VERSION 5.7 ;
  NOWIREEXTENSIONATPIN ON ;
  DIVIDERCHAR "/" ;
  BUSBITCHARS "[]" ;
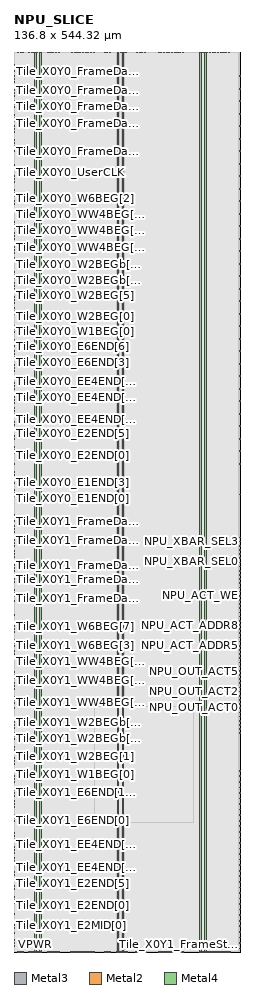
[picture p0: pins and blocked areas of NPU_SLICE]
MACRO NPU_SLICE
  CLASS BLOCK ;
  FOREIGN NPU_SLICE ;
  ORIGIN 0.000 0.000 ;
  SIZE 136.800 BY 544.320 ;
  PIN FAB_USER_CLK
    DIRECTION OUTPUT ;
    USE SIGNAL ;
    ANTENNADIFFAREA 2.724000 ;
    PORT
      LAYER Metal3 ;
        RECT 136.400 250.540 136.800 250.940 ;
    END
  END FAB_USER_CLK
  PIN NPU_ACT_ADDR0
    DIRECTION OUTPUT ;
    USE SIGNAL ;
    ANTENNADIFFAREA 2.647800 ;
    PORT
      LAYER Metal3 ;
        RECT 136.400 172.420 136.800 172.820 ;
    END
  END NPU_ACT_ADDR0
  PIN NPU_ACT_ADDR1
    DIRECTION OUTPUT ;
    USE SIGNAL ;
    ANTENNADIFFAREA 2.647800 ;
    PORT
      LAYER Metal3 ;
        RECT 136.400 174.940 136.800 175.340 ;
    END
  END NPU_ACT_ADDR1
  PIN NPU_ACT_ADDR2
    DIRECTION OUTPUT ;
    USE SIGNAL ;
    ANTENNADIFFAREA 2.647800 ;
    PORT
      LAYER Metal3 ;
        RECT 136.400 177.460 136.800 177.860 ;
    END
  END NPU_ACT_ADDR2
  PIN NPU_ACT_ADDR3
    DIRECTION OUTPUT ;
    USE SIGNAL ;
    ANTENNADIFFAREA 2.647800 ;
    PORT
      LAYER Metal3 ;
        RECT 136.400 179.980 136.800 180.380 ;
    END
  END NPU_ACT_ADDR3
  PIN NPU_ACT_ADDR4
    DIRECTION OUTPUT ;
    USE SIGNAL ;
    ANTENNADIFFAREA 2.647800 ;
    PORT
      LAYER Metal3 ;
        RECT 136.400 182.500 136.800 182.900 ;
    END
  END NPU_ACT_ADDR4
  PIN NPU_ACT_ADDR5
    DIRECTION OUTPUT ;
    USE SIGNAL ;
    ANTENNADIFFAREA 2.647800 ;
    PORT
      LAYER Metal3 ;
        RECT 136.400 185.020 136.800 185.420 ;
    END
  END NPU_ACT_ADDR5
  PIN NPU_ACT_ADDR6
    DIRECTION OUTPUT ;
    USE SIGNAL ;
    ANTENNADIFFAREA 2.647800 ;
    PORT
      LAYER Metal3 ;
        RECT 136.400 187.540 136.800 187.940 ;
    END
  END NPU_ACT_ADDR6
  PIN NPU_ACT_ADDR7
    DIRECTION OUTPUT ;
    USE SIGNAL ;
    ANTENNADIFFAREA 2.647800 ;
    PORT
      LAYER Metal3 ;
        RECT 136.400 190.060 136.800 190.460 ;
    END
  END NPU_ACT_ADDR7
  PIN NPU_ACT_ADDR8
    DIRECTION OUTPUT ;
    USE SIGNAL ;
    ANTENNADIFFAREA 2.647800 ;
    PORT
      LAYER Metal3 ;
        RECT 136.400 192.580 136.800 192.980 ;
    END
  END NPU_ACT_ADDR8
  PIN NPU_ACT_RDATA0
    DIRECTION INPUT ;
    USE SIGNAL ;
    ANTENNAGATEAREA 0.109200 ;
    PORT
      LAYER Metal3 ;
        RECT 136.400 132.100 136.800 132.500 ;
    END
  END NPU_ACT_RDATA0
  PIN NPU_ACT_RDATA1
    DIRECTION INPUT ;
    USE SIGNAL ;
    ANTENNAGATEAREA 0.109200 ;
    PORT
      LAYER Metal3 ;
        RECT 136.400 134.620 136.800 135.020 ;
    END
  END NPU_ACT_RDATA1
  PIN NPU_ACT_RDATA2
    DIRECTION INPUT ;
    USE SIGNAL ;
    ANTENNAGATEAREA 0.109200 ;
    PORT
      LAYER Metal3 ;
        RECT 136.400 137.140 136.800 137.540 ;
    END
  END NPU_ACT_RDATA2
  PIN NPU_ACT_RDATA3
    DIRECTION INPUT ;
    USE SIGNAL ;
    ANTENNAGATEAREA 0.109200 ;
    PORT
      LAYER Metal3 ;
        RECT 136.400 139.660 136.800 140.060 ;
    END
  END NPU_ACT_RDATA3
  PIN NPU_ACT_RDATA4
    DIRECTION INPUT ;
    USE SIGNAL ;
    ANTENNAGATEAREA 0.109200 ;
    PORT
      LAYER Metal3 ;
        RECT 136.400 142.180 136.800 142.580 ;
    END
  END NPU_ACT_RDATA4
  PIN NPU_ACT_RDATA5
    DIRECTION INPUT ;
    USE SIGNAL ;
    ANTENNAGATEAREA 0.109200 ;
    PORT
      LAYER Metal3 ;
        RECT 136.400 144.700 136.800 145.100 ;
    END
  END NPU_ACT_RDATA5
  PIN NPU_ACT_RDATA6
    DIRECTION INPUT ;
    USE SIGNAL ;
    ANTENNAGATEAREA 0.109200 ;
    PORT
      LAYER Metal3 ;
        RECT 136.400 147.220 136.800 147.620 ;
    END
  END NPU_ACT_RDATA6
  PIN NPU_ACT_RDATA7
    DIRECTION INPUT ;
    USE SIGNAL ;
    ANTENNAGATEAREA 0.109200 ;
    PORT
      LAYER Metal3 ;
        RECT 136.400 149.740 136.800 150.140 ;
    END
  END NPU_ACT_RDATA7
  PIN NPU_ACT_WDATA0
    DIRECTION OUTPUT ;
    USE SIGNAL ;
    ANTENNADIFFAREA 2.647800 ;
    PORT
      LAYER Metal3 ;
        RECT 136.400 195.100 136.800 195.500 ;
    END
  END NPU_ACT_WDATA0
  PIN NPU_ACT_WDATA1
    DIRECTION OUTPUT ;
    USE SIGNAL ;
    ANTENNADIFFAREA 2.647800 ;
    PORT
      LAYER Metal3 ;
        RECT 136.400 197.620 136.800 198.020 ;
    END
  END NPU_ACT_WDATA1
  PIN NPU_ACT_WDATA2
    DIRECTION OUTPUT ;
    USE SIGNAL ;
    ANTENNADIFFAREA 2.647800 ;
    PORT
      LAYER Metal3 ;
        RECT 136.400 200.140 136.800 200.540 ;
    END
  END NPU_ACT_WDATA2
  PIN NPU_ACT_WDATA3
    DIRECTION OUTPUT ;
    USE SIGNAL ;
    ANTENNADIFFAREA 2.647800 ;
    PORT
      LAYER Metal3 ;
        RECT 136.400 202.660 136.800 203.060 ;
    END
  END NPU_ACT_WDATA3
  PIN NPU_ACT_WDATA4
    DIRECTION OUTPUT ;
    USE SIGNAL ;
    ANTENNADIFFAREA 2.647800 ;
    PORT
      LAYER Metal3 ;
        RECT 136.400 205.180 136.800 205.580 ;
    END
  END NPU_ACT_WDATA4
  PIN NPU_ACT_WDATA5
    DIRECTION OUTPUT ;
    USE SIGNAL ;
    ANTENNADIFFAREA 2.647800 ;
    PORT
      LAYER Metal3 ;
        RECT 136.400 207.700 136.800 208.100 ;
    END
  END NPU_ACT_WDATA5
  PIN NPU_ACT_WDATA6
    DIRECTION OUTPUT ;
    USE SIGNAL ;
    ANTENNADIFFAREA 2.647800 ;
    PORT
      LAYER Metal3 ;
        RECT 136.400 210.220 136.800 210.620 ;
    END
  END NPU_ACT_WDATA6
  PIN NPU_ACT_WDATA7
    DIRECTION OUTPUT ;
    USE SIGNAL ;
    ANTENNADIFFAREA 2.647800 ;
    PORT
      LAYER Metal3 ;
        RECT 136.400 212.740 136.800 213.140 ;
    END
  END NPU_ACT_WDATA7
  PIN NPU_ACT_WE
    DIRECTION OUTPUT ;
    USE SIGNAL ;
    ANTENNADIFFAREA 2.647800 ;
    PORT
      LAYER Metal3 ;
        RECT 136.400 215.260 136.800 215.660 ;
    END
  END NPU_ACT_WE
  PIN NPU_OUT_ACT0
    DIRECTION INPUT ;
    USE SIGNAL ;
    ANTENNAGATEAREA 0.109200 ;
    ANTENNADIFFAREA 2.015400 ;
    PORT
      LAYER Metal3 ;
        RECT 136.400 152.260 136.800 152.660 ;
    END
  END NPU_OUT_ACT0
  PIN NPU_OUT_ACT1
    DIRECTION INPUT ;
    USE SIGNAL ;
    ANTENNAGATEAREA 0.109200 ;
    PORT
      LAYER Metal3 ;
        RECT 136.400 154.780 136.800 155.180 ;
    END
  END NPU_OUT_ACT1
  PIN NPU_OUT_ACT2
    DIRECTION INPUT ;
    USE SIGNAL ;
    ANTENNAGATEAREA 0.109200 ;
    PORT
      LAYER Metal3 ;
        RECT 136.400 157.300 136.800 157.700 ;
    END
  END NPU_OUT_ACT2
  PIN NPU_OUT_ACT3
    DIRECTION INPUT ;
    USE SIGNAL ;
    ANTENNAGATEAREA 0.109200 ;
    ANTENNADIFFAREA 2.015400 ;
    PORT
      LAYER Metal3 ;
        RECT 136.400 159.820 136.800 160.220 ;
    END
  END NPU_OUT_ACT3
  PIN NPU_OUT_ACT4
    DIRECTION INPUT ;
    USE SIGNAL ;
    ANTENNAGATEAREA 0.109200 ;
    ANTENNADIFFAREA 2.015400 ;
    PORT
      LAYER Metal3 ;
        RECT 136.400 162.340 136.800 162.740 ;
    END
  END NPU_OUT_ACT4
  PIN NPU_OUT_ACT5
    DIRECTION INPUT ;
    USE SIGNAL ;
    ANTENNAGATEAREA 0.109200 ;
    ANTENNADIFFAREA 2.015400 ;
    PORT
      LAYER Metal3 ;
        RECT 136.400 164.860 136.800 165.260 ;
    END
  END NPU_OUT_ACT5
  PIN NPU_OUT_ACT6
    DIRECTION INPUT ;
    USE SIGNAL ;
    ANTENNAGATEAREA 0.109200 ;
    ANTENNADIFFAREA 2.015400 ;
    PORT
      LAYER Metal3 ;
        RECT 136.400 167.380 136.800 167.780 ;
    END
  END NPU_OUT_ACT6
  PIN NPU_OUT_ACT7
    DIRECTION INPUT ;
    USE SIGNAL ;
    ANTENNAGATEAREA 0.109200 ;
    ANTENNADIFFAREA 2.015400 ;
    PORT
      LAYER Metal3 ;
        RECT 136.400 169.900 136.800 170.300 ;
    END
  END NPU_OUT_ACT7
  PIN NPU_WEIGHT_IN0
    DIRECTION OUTPUT ;
    USE SIGNAL ;
    ANTENNADIFFAREA 2.647800 ;
    PORT
      LAYER Metal3 ;
        RECT 136.400 217.780 136.800 218.180 ;
    END
  END NPU_WEIGHT_IN0
  PIN NPU_WEIGHT_IN1
    DIRECTION OUTPUT ;
    USE SIGNAL ;
    ANTENNADIFFAREA 2.647800 ;
    PORT
      LAYER Metal3 ;
        RECT 136.400 220.300 136.800 220.700 ;
    END
  END NPU_WEIGHT_IN1
  PIN NPU_WEIGHT_IN2
    DIRECTION OUTPUT ;
    USE SIGNAL ;
    ANTENNADIFFAREA 2.647800 ;
    PORT
      LAYER Metal3 ;
        RECT 136.400 222.820 136.800 223.220 ;
    END
  END NPU_WEIGHT_IN2
  PIN NPU_WEIGHT_IN3
    DIRECTION OUTPUT ;
    USE SIGNAL ;
    ANTENNADIFFAREA 2.647800 ;
    PORT
      LAYER Metal3 ;
        RECT 136.400 225.340 136.800 225.740 ;
    END
  END NPU_WEIGHT_IN3
  PIN NPU_WEIGHT_IN4
    DIRECTION OUTPUT ;
    USE SIGNAL ;
    ANTENNADIFFAREA 2.647800 ;
    PORT
      LAYER Metal3 ;
        RECT 136.400 227.860 136.800 228.260 ;
    END
  END NPU_WEIGHT_IN4
  PIN NPU_WEIGHT_IN5
    DIRECTION OUTPUT ;
    USE SIGNAL ;
    ANTENNADIFFAREA 2.647800 ;
    PORT
      LAYER Metal3 ;
        RECT 136.400 230.380 136.800 230.780 ;
    END
  END NPU_WEIGHT_IN5
  PIN NPU_WEIGHT_IN6
    DIRECTION OUTPUT ;
    USE SIGNAL ;
    ANTENNADIFFAREA 2.647800 ;
    PORT
      LAYER Metal3 ;
        RECT 136.400 232.900 136.800 233.300 ;
    END
  END NPU_WEIGHT_IN6
  PIN NPU_WEIGHT_IN7
    DIRECTION OUTPUT ;
    USE SIGNAL ;
    ANTENNADIFFAREA 2.647800 ;
    PORT
      LAYER Metal3 ;
        RECT 136.400 235.420 136.800 235.820 ;
    END
  END NPU_WEIGHT_IN7
  PIN NPU_WEIGHT_SHIFT_EN
    DIRECTION OUTPUT ;
    USE SIGNAL ;
    ANTENNADIFFAREA 2.647800 ;
    PORT
      LAYER Metal3 ;
        RECT 136.400 237.940 136.800 238.340 ;
    END
  END NPU_WEIGHT_SHIFT_EN
  PIN NPU_XBAR_SEL0
    DIRECTION OUTPUT ;
    USE SIGNAL ;
    ANTENNADIFFAREA 2.647800 ;
    PORT
      LAYER Metal3 ;
        RECT 136.400 240.460 136.800 240.860 ;
    END
  END NPU_XBAR_SEL0
  PIN NPU_XBAR_SEL1
    DIRECTION OUTPUT ;
    USE SIGNAL ;
    ANTENNADIFFAREA 2.647800 ;
    PORT
      LAYER Metal3 ;
        RECT 136.400 242.980 136.800 243.380 ;
    END
  END NPU_XBAR_SEL1
  PIN NPU_XBAR_SEL2
    DIRECTION OUTPUT ;
    USE SIGNAL ;
    ANTENNADIFFAREA 2.647800 ;
    PORT
      LAYER Metal3 ;
        RECT 136.400 245.500 136.800 245.900 ;
    END
  END NPU_XBAR_SEL2
  PIN NPU_XBAR_SEL3
    DIRECTION OUTPUT ;
    USE SIGNAL ;
    ANTENNADIFFAREA 2.647800 ;
    PORT
      LAYER Metal3 ;
        RECT 136.400 248.020 136.800 248.420 ;
    END
  END NPU_XBAR_SEL3
  PIN Tile_X0Y0_E1END[0]
    DIRECTION INPUT ;
    USE SIGNAL ;
    ANTENNAGATEAREA 1.279200 ;
    PORT
      LAYER Metal3 ;
        RECT 0.000 274.060 0.400 274.460 ;
    END
  END Tile_X0Y0_E1END[0]
  PIN Tile_X0Y0_E1END[1]
    DIRECTION INPUT ;
    USE SIGNAL ;
    ANTENNAGATEAREA 1.279200 ;
    PORT
      LAYER Metal3 ;
        RECT 0.000 275.740 0.400 276.140 ;
    END
  END Tile_X0Y0_E1END[1]
  PIN Tile_X0Y0_E1END[2]
    DIRECTION INPUT ;
    USE SIGNAL ;
    ANTENNAGATEAREA 1.279200 ;
    PORT
      LAYER Metal3 ;
        RECT 0.000 277.420 0.400 277.820 ;
    END
  END Tile_X0Y0_E1END[2]
  PIN Tile_X0Y0_E1END[3]
    DIRECTION INPUT ;
    USE SIGNAL ;
    ANTENNAGATEAREA 1.066000 ;
    PORT
      LAYER Metal3 ;
        RECT 0.000 279.100 0.400 279.500 ;
    END
  END Tile_X0Y0_E1END[3]
  PIN Tile_X0Y0_E2END[0]
    DIRECTION INPUT ;
    USE SIGNAL ;
    ANTENNAGATEAREA 0.639600 ;
    PORT
      LAYER Metal3 ;
        RECT 0.000 300.100 0.400 300.500 ;
    END
  END Tile_X0Y0_E2END[0]
  PIN Tile_X0Y0_E2END[1]
    DIRECTION INPUT ;
    USE SIGNAL ;
    ANTENNAGATEAREA 0.639600 ;
    PORT
      LAYER Metal3 ;
        RECT 0.000 301.780 0.400 302.180 ;
    END
  END Tile_X0Y0_E2END[1]
  PIN Tile_X0Y0_E2END[2]
    DIRECTION INPUT ;
    USE SIGNAL ;
    ANTENNAGATEAREA 0.639600 ;
    PORT
      LAYER Metal3 ;
        RECT 0.000 303.460 0.400 303.860 ;
    END
  END Tile_X0Y0_E2END[2]
  PIN Tile_X0Y0_E2END[3]
    DIRECTION INPUT ;
    USE SIGNAL ;
    ANTENNAGATEAREA 0.639600 ;
    PORT
      LAYER Metal3 ;
        RECT 0.000 305.140 0.400 305.540 ;
    END
  END Tile_X0Y0_E2END[3]
  PIN Tile_X0Y0_E2END[4]
    DIRECTION INPUT ;
    USE SIGNAL ;
    ANTENNAGATEAREA 0.639600 ;
    PORT
      LAYER Metal3 ;
        RECT 0.000 306.820 0.400 307.220 ;
    END
  END Tile_X0Y0_E2END[4]
  PIN Tile_X0Y0_E2END[5]
    DIRECTION INPUT ;
    USE SIGNAL ;
    ANTENNAGATEAREA 0.639600 ;
    PORT
      LAYER Metal3 ;
        RECT 0.000 308.500 0.400 308.900 ;
    END
  END Tile_X0Y0_E2END[5]
  PIN Tile_X0Y0_E2END[6]
    DIRECTION INPUT ;
    USE SIGNAL ;
    ANTENNAGATEAREA 0.639600 ;
    PORT
      LAYER Metal3 ;
        RECT 0.000 310.180 0.400 310.580 ;
    END
  END Tile_X0Y0_E2END[6]
  PIN Tile_X0Y0_E2END[7]
    DIRECTION INPUT ;
    USE SIGNAL ;
    ANTENNAGATEAREA 0.639600 ;
    PORT
      LAYER Metal3 ;
        RECT 0.000 311.860 0.400 312.260 ;
    END
  END Tile_X0Y0_E2END[7]
  PIN Tile_X0Y0_E2MID[0]
    DIRECTION INPUT ;
    USE SIGNAL ;
    ANTENNAGATEAREA 0.639600 ;
    PORT
      LAYER Metal3 ;
        RECT 0.000 283.300 0.400 283.700 ;
    END
  END Tile_X0Y0_E2MID[0]
  PIN Tile_X0Y0_E2MID[1]
    DIRECTION INPUT ;
    USE SIGNAL ;
    ANTENNAGATEAREA 0.639600 ;
    PORT
      LAYER Metal3 ;
        RECT 0.000 284.980 0.400 285.380 ;
    END
  END Tile_X0Y0_E2MID[1]
  PIN Tile_X0Y0_E2MID[2]
    DIRECTION INPUT ;
    USE SIGNAL ;
    ANTENNAGATEAREA 0.639600 ;
    PORT
      LAYER Metal3 ;
        RECT 0.000 286.660 0.400 287.060 ;
    END
  END Tile_X0Y0_E2MID[2]
  PIN Tile_X0Y0_E2MID[3]
    DIRECTION INPUT ;
    USE SIGNAL ;
    ANTENNAGATEAREA 0.639600 ;
    PORT
      LAYER Metal3 ;
        RECT 0.000 288.340 0.400 288.740 ;
    END
  END Tile_X0Y0_E2MID[3]
  PIN Tile_X0Y0_E2MID[4]
    DIRECTION INPUT ;
    USE SIGNAL ;
    ANTENNAGATEAREA 0.639600 ;
    PORT
      LAYER Metal3 ;
        RECT 0.000 290.020 0.400 290.420 ;
    END
  END Tile_X0Y0_E2MID[4]
  PIN Tile_X0Y0_E2MID[5]
    DIRECTION INPUT ;
    USE SIGNAL ;
    ANTENNAGATEAREA 0.639600 ;
    PORT
      LAYER Metal3 ;
        RECT 0.000 291.700 0.400 292.100 ;
    END
  END Tile_X0Y0_E2MID[5]
  PIN Tile_X0Y0_E2MID[6]
    DIRECTION INPUT ;
    USE SIGNAL ;
    ANTENNAGATEAREA 0.639600 ;
    PORT
      LAYER Metal3 ;
        RECT 0.000 293.380 0.400 293.780 ;
    END
  END Tile_X0Y0_E2MID[6]
  PIN Tile_X0Y0_E2MID[7]
    DIRECTION INPUT ;
    USE SIGNAL ;
    ANTENNAGATEAREA 0.639600 ;
    PORT
      LAYER Metal3 ;
        RECT 0.000 295.060 0.400 295.460 ;
    END
  END Tile_X0Y0_E2MID[7]
  PIN Tile_X0Y0_E6END[0]
    DIRECTION INPUT ;
    USE SIGNAL ;
    ANTENNAGATEAREA 0.852800 ;
    PORT
      LAYER Metal3 ;
        RECT 0.000 351.340 0.400 351.740 ;
    END
  END Tile_X0Y0_E6END[0]
  PIN Tile_X0Y0_E6END[10]
    DIRECTION INPUT ;
    USE SIGNAL ;
    ANTENNAGATEAREA 0.639600 ;
    PORT
      LAYER Metal3 ;
        RECT 0.000 368.140 0.400 368.540 ;
    END
  END Tile_X0Y0_E6END[10]
  PIN Tile_X0Y0_E6END[11]
    DIRECTION INPUT ;
    USE SIGNAL ;
    ANTENNAGATEAREA 0.639600 ;
    PORT
      LAYER Metal3 ;
        RECT 0.000 369.820 0.400 370.220 ;
    END
  END Tile_X0Y0_E6END[11]
  PIN Tile_X0Y0_E6END[1]
    DIRECTION INPUT ;
    USE SIGNAL ;
    ANTENNAGATEAREA 0.852800 ;
    PORT
      LAYER Metal3 ;
        RECT 0.000 353.020 0.400 353.420 ;
    END
  END Tile_X0Y0_E6END[1]
  PIN Tile_X0Y0_E6END[2]
    DIRECTION INPUT ;
    USE SIGNAL ;
    ANTENNAGATEAREA 0.852800 ;
    PORT
      LAYER Metal3 ;
        RECT 0.000 354.700 0.400 355.100 ;
    END
  END Tile_X0Y0_E6END[2]
  PIN Tile_X0Y0_E6END[3]
    DIRECTION INPUT ;
    USE SIGNAL ;
    ANTENNAGATEAREA 0.639600 ;
    PORT
      LAYER Metal3 ;
        RECT 0.000 356.380 0.400 356.780 ;
    END
  END Tile_X0Y0_E6END[3]
  PIN Tile_X0Y0_E6END[4]
    DIRECTION INPUT ;
    USE SIGNAL ;
    ANTENNAGATEAREA 0.639600 ;
    PORT
      LAYER Metal3 ;
        RECT 0.000 358.060 0.400 358.460 ;
    END
  END Tile_X0Y0_E6END[4]
  PIN Tile_X0Y0_E6END[5]
    DIRECTION INPUT ;
    USE SIGNAL ;
    ANTENNAGATEAREA 0.639600 ;
    PORT
      LAYER Metal3 ;
        RECT 0.000 359.740 0.400 360.140 ;
    END
  END Tile_X0Y0_E6END[5]
  PIN Tile_X0Y0_E6END[6]
    DIRECTION INPUT ;
    USE SIGNAL ;
    ANTENNAGATEAREA 0.639600 ;
    PORT
      LAYER Metal3 ;
        RECT 0.000 361.420 0.400 361.820 ;
    END
  END Tile_X0Y0_E6END[6]
  PIN Tile_X0Y0_E6END[7]
    DIRECTION INPUT ;
    USE SIGNAL ;
    ANTENNAGATEAREA 0.639600 ;
    PORT
      LAYER Metal3 ;
        RECT 0.000 363.100 0.400 363.500 ;
    END
  END Tile_X0Y0_E6END[7]
  PIN Tile_X0Y0_E6END[8]
    DIRECTION INPUT ;
    USE SIGNAL ;
    ANTENNAGATEAREA 0.639600 ;
    PORT
      LAYER Metal3 ;
        RECT 0.000 364.780 0.400 365.180 ;
    END
  END Tile_X0Y0_E6END[8]
  PIN Tile_X0Y0_E6END[9]
    DIRECTION INPUT ;
    USE SIGNAL ;
    ANTENNAGATEAREA 0.639600 ;
    PORT
      LAYER Metal3 ;
        RECT 0.000 366.460 0.400 366.860 ;
    END
  END Tile_X0Y0_E6END[9]
  PIN Tile_X0Y0_EE4END[0]
    DIRECTION INPUT ;
    USE SIGNAL ;
    ANTENNAGATEAREA 0.426400 ;
    PORT
      LAYER Metal3 ;
        RECT 0.000 318.580 0.400 318.980 ;
    END
  END Tile_X0Y0_EE4END[0]
  PIN Tile_X0Y0_EE4END[10]
    DIRECTION INPUT ;
    USE SIGNAL ;
    ANTENNAGATEAREA 0.426400 ;
    PORT
      LAYER Metal3 ;
        RECT 0.000 335.380 0.400 335.780 ;
    END
  END Tile_X0Y0_EE4END[10]
  PIN Tile_X0Y0_EE4END[11]
    DIRECTION INPUT ;
    USE SIGNAL ;
    ANTENNAGATEAREA 0.426400 ;
    PORT
      LAYER Metal3 ;
        RECT 0.000 337.060 0.400 337.460 ;
    END
  END Tile_X0Y0_EE4END[11]
  PIN Tile_X0Y0_EE4END[12]
    DIRECTION INPUT ;
    USE SIGNAL ;
    ANTENNAGATEAREA 0.426400 ;
    PORT
      LAYER Metal3 ;
        RECT 0.000 338.740 0.400 339.140 ;
    END
  END Tile_X0Y0_EE4END[12]
  PIN Tile_X0Y0_EE4END[13]
    DIRECTION INPUT ;
    USE SIGNAL ;
    ANTENNAGATEAREA 0.426400 ;
    PORT
      LAYER Metal3 ;
        RECT 0.000 340.420 0.400 340.820 ;
    END
  END Tile_X0Y0_EE4END[13]
  PIN Tile_X0Y0_EE4END[14]
    DIRECTION INPUT ;
    USE SIGNAL ;
    ANTENNAGATEAREA 0.426400 ;
    PORT
      LAYER Metal3 ;
        RECT 0.000 342.100 0.400 342.500 ;
    END
  END Tile_X0Y0_EE4END[14]
  PIN Tile_X0Y0_EE4END[15]
    DIRECTION INPUT ;
    USE SIGNAL ;
    ANTENNAGATEAREA 0.426400 ;
    PORT
      LAYER Metal3 ;
        RECT 0.000 343.780 0.400 344.180 ;
    END
  END Tile_X0Y0_EE4END[15]
  PIN Tile_X0Y0_EE4END[1]
    DIRECTION INPUT ;
    USE SIGNAL ;
    ANTENNAGATEAREA 0.426400 ;
    PORT
      LAYER Metal3 ;
        RECT 0.000 320.260 0.400 320.660 ;
    END
  END Tile_X0Y0_EE4END[1]
  PIN Tile_X0Y0_EE4END[2]
    DIRECTION INPUT ;
    USE SIGNAL ;
    ANTENNAGATEAREA 0.426400 ;
    PORT
      LAYER Metal3 ;
        RECT 0.000 321.940 0.400 322.340 ;
    END
  END Tile_X0Y0_EE4END[2]
  PIN Tile_X0Y0_EE4END[3]
    DIRECTION INPUT ;
    USE SIGNAL ;
    ANTENNAGATEAREA 0.426400 ;
    PORT
      LAYER Metal3 ;
        RECT 0.000 323.620 0.400 324.020 ;
    END
  END Tile_X0Y0_EE4END[3]
  PIN Tile_X0Y0_EE4END[4]
    DIRECTION INPUT ;
    USE SIGNAL ;
    ANTENNAGATEAREA 0.426400 ;
    PORT
      LAYER Metal3 ;
        RECT 0.000 325.300 0.400 325.700 ;
    END
  END Tile_X0Y0_EE4END[4]
  PIN Tile_X0Y0_EE4END[5]
    DIRECTION INPUT ;
    USE SIGNAL ;
    ANTENNAGATEAREA 0.426400 ;
    PORT
      LAYER Metal3 ;
        RECT 0.000 326.980 0.400 327.380 ;
    END
  END Tile_X0Y0_EE4END[5]
  PIN Tile_X0Y0_EE4END[6]
    DIRECTION INPUT ;
    USE SIGNAL ;
    ANTENNAGATEAREA 0.426400 ;
    PORT
      LAYER Metal3 ;
        RECT 0.000 328.660 0.400 329.060 ;
    END
  END Tile_X0Y0_EE4END[6]
  PIN Tile_X0Y0_EE4END[7]
    DIRECTION INPUT ;
    USE SIGNAL ;
    ANTENNAGATEAREA 0.426400 ;
    PORT
      LAYER Metal3 ;
        RECT 0.000 330.340 0.400 330.740 ;
    END
  END Tile_X0Y0_EE4END[7]
  PIN Tile_X0Y0_EE4END[8]
    DIRECTION INPUT ;
    USE SIGNAL ;
    ANTENNAGATEAREA 0.426400 ;
    PORT
      LAYER Metal3 ;
        RECT 0.000 332.020 0.400 332.420 ;
    END
  END Tile_X0Y0_EE4END[8]
  PIN Tile_X0Y0_EE4END[9]
    DIRECTION INPUT ;
    USE SIGNAL ;
    ANTENNAGATEAREA 0.426400 ;
    PORT
      LAYER Metal3 ;
        RECT 0.000 333.700 0.400 334.100 ;
    END
  END Tile_X0Y0_EE4END[9]
  PIN Tile_X0Y0_FrameData[0]
    DIRECTION INPUT ;
    USE SIGNAL ;
    ANTENNAGATEAREA 1.445600 ;
    PORT
      LAYER Metal3 ;
        RECT 0.000 484.060 0.400 484.460 ;
    END
  END Tile_X0Y0_FrameData[0]
  PIN Tile_X0Y0_FrameData[10]
    DIRECTION INPUT ;
    USE SIGNAL ;
    ANTENNAGATEAREA 1.626300 ;
    PORT
      LAYER Metal3 ;
        RECT 0.000 500.860 0.400 501.260 ;
    END
  END Tile_X0Y0_FrameData[10]
  PIN Tile_X0Y0_FrameData[11]
    DIRECTION INPUT ;
    USE SIGNAL ;
    ANTENNAGATEAREA 1.626300 ;
    PORT
      LAYER Metal3 ;
        RECT 0.000 502.540 0.400 502.940 ;
    END
  END Tile_X0Y0_FrameData[11]
  PIN Tile_X0Y0_FrameData[12]
    DIRECTION INPUT ;
    USE SIGNAL ;
    ANTENNAGATEAREA 1.626300 ;
    PORT
      LAYER Metal3 ;
        RECT 0.000 504.220 0.400 504.620 ;
    END
  END Tile_X0Y0_FrameData[12]
  PIN Tile_X0Y0_FrameData[13]
    DIRECTION INPUT ;
    USE SIGNAL ;
    ANTENNAGATEAREA 1.626300 ;
    PORT
      LAYER Metal3 ;
        RECT 0.000 505.900 0.400 506.300 ;
    END
  END Tile_X0Y0_FrameData[13]
  PIN Tile_X0Y0_FrameData[14]
    DIRECTION INPUT ;
    USE SIGNAL ;
    ANTENNAGATEAREA 1.626300 ;
    PORT
      LAYER Metal3 ;
        RECT 0.000 507.580 0.400 507.980 ;
    END
  END Tile_X0Y0_FrameData[14]
  PIN Tile_X0Y0_FrameData[15]
    DIRECTION INPUT ;
    USE SIGNAL ;
    ANTENNAGATEAREA 1.626300 ;
    PORT
      LAYER Metal3 ;
        RECT 0.000 509.260 0.400 509.660 ;
    END
  END Tile_X0Y0_FrameData[15]
  PIN Tile_X0Y0_FrameData[16]
    DIRECTION INPUT ;
    USE SIGNAL ;
    ANTENNAGATEAREA 1.626300 ;
    PORT
      LAYER Metal3 ;
        RECT 0.000 510.940 0.400 511.340 ;
    END
  END Tile_X0Y0_FrameData[16]
  PIN Tile_X0Y0_FrameData[17]
    DIRECTION INPUT ;
    USE SIGNAL ;
    ANTENNAGATEAREA 1.626300 ;
    PORT
      LAYER Metal3 ;
        RECT 0.000 512.620 0.400 513.020 ;
    END
  END Tile_X0Y0_FrameData[17]
  PIN Tile_X0Y0_FrameData[18]
    DIRECTION INPUT ;
    USE SIGNAL ;
    ANTENNAGATEAREA 1.626300 ;
    PORT
      LAYER Metal3 ;
        RECT 0.000 514.300 0.400 514.700 ;
    END
  END Tile_X0Y0_FrameData[18]
  PIN Tile_X0Y0_FrameData[19]
    DIRECTION INPUT ;
    USE SIGNAL ;
    ANTENNAGATEAREA 1.626300 ;
    PORT
      LAYER Metal3 ;
        RECT 0.000 515.980 0.400 516.380 ;
    END
  END Tile_X0Y0_FrameData[19]
  PIN Tile_X0Y0_FrameData[1]
    DIRECTION INPUT ;
    USE SIGNAL ;
    ANTENNAGATEAREA 1.445600 ;
    PORT
      LAYER Metal3 ;
        RECT 0.000 485.740 0.400 486.140 ;
    END
  END Tile_X0Y0_FrameData[1]
  PIN Tile_X0Y0_FrameData[20]
    DIRECTION INPUT ;
    USE SIGNAL ;
    ANTENNAGATEAREA 1.626300 ;
    PORT
      LAYER Metal3 ;
        RECT 0.000 517.660 0.400 518.060 ;
    END
  END Tile_X0Y0_FrameData[20]
  PIN Tile_X0Y0_FrameData[21]
    DIRECTION INPUT ;
    USE SIGNAL ;
    ANTENNAGATEAREA 1.626300 ;
    PORT
      LAYER Metal3 ;
        RECT 0.000 519.340 0.400 519.740 ;
    END
  END Tile_X0Y0_FrameData[21]
  PIN Tile_X0Y0_FrameData[22]
    DIRECTION INPUT ;
    USE SIGNAL ;
    ANTENNAGATEAREA 1.626300 ;
    PORT
      LAYER Metal3 ;
        RECT 0.000 521.020 0.400 521.420 ;
    END
  END Tile_X0Y0_FrameData[22]
  PIN Tile_X0Y0_FrameData[23]
    DIRECTION INPUT ;
    USE SIGNAL ;
    ANTENNAGATEAREA 1.626300 ;
    PORT
      LAYER Metal3 ;
        RECT 0.000 522.700 0.400 523.100 ;
    END
  END Tile_X0Y0_FrameData[23]
  PIN Tile_X0Y0_FrameData[24]
    DIRECTION INPUT ;
    USE SIGNAL ;
    ANTENNAGATEAREA 1.626300 ;
    PORT
      LAYER Metal3 ;
        RECT 0.000 524.380 0.400 524.780 ;
    END
  END Tile_X0Y0_FrameData[24]
  PIN Tile_X0Y0_FrameData[25]
    DIRECTION INPUT ;
    USE SIGNAL ;
    ANTENNAGATEAREA 1.626300 ;
    PORT
      LAYER Metal3 ;
        RECT 0.000 526.060 0.400 526.460 ;
    END
  END Tile_X0Y0_FrameData[25]
  PIN Tile_X0Y0_FrameData[26]
    DIRECTION INPUT ;
    USE SIGNAL ;
    ANTENNAGATEAREA 1.626300 ;
    PORT
      LAYER Metal3 ;
        RECT 0.000 527.740 0.400 528.140 ;
    END
  END Tile_X0Y0_FrameData[26]
  PIN Tile_X0Y0_FrameData[27]
    DIRECTION INPUT ;
    USE SIGNAL ;
    ANTENNAGATEAREA 1.626300 ;
    PORT
      LAYER Metal3 ;
        RECT 0.000 529.420 0.400 529.820 ;
    END
  END Tile_X0Y0_FrameData[27]
  PIN Tile_X0Y0_FrameData[28]
    DIRECTION INPUT ;
    USE SIGNAL ;
    ANTENNAGATEAREA 1.626300 ;
    PORT
      LAYER Metal3 ;
        RECT 0.000 531.100 0.400 531.500 ;
    END
  END Tile_X0Y0_FrameData[28]
  PIN Tile_X0Y0_FrameData[29]
    DIRECTION INPUT ;
    USE SIGNAL ;
    ANTENNAGATEAREA 1.626300 ;
    PORT
      LAYER Metal3 ;
        RECT 0.000 532.780 0.400 533.180 ;
    END
  END Tile_X0Y0_FrameData[29]
  PIN Tile_X0Y0_FrameData[2]
    DIRECTION INPUT ;
    USE SIGNAL ;
    ANTENNAGATEAREA 1.626300 ;
    PORT
      LAYER Metal3 ;
        RECT 0.000 487.420 0.400 487.820 ;
    END
  END Tile_X0Y0_FrameData[2]
  PIN Tile_X0Y0_FrameData[30]
    DIRECTION INPUT ;
    USE SIGNAL ;
    ANTENNAGATEAREA 1.626300 ;
    PORT
      LAYER Metal3 ;
        RECT 0.000 534.460 0.400 534.860 ;
    END
  END Tile_X0Y0_FrameData[30]
  PIN Tile_X0Y0_FrameData[31]
    DIRECTION INPUT ;
    USE SIGNAL ;
    ANTENNAGATEAREA 1.626300 ;
    PORT
      LAYER Metal3 ;
        RECT 0.000 536.140 0.400 536.540 ;
    END
  END Tile_X0Y0_FrameData[31]
  PIN Tile_X0Y0_FrameData[3]
    DIRECTION INPUT ;
    USE SIGNAL ;
    ANTENNAGATEAREA 1.626300 ;
    PORT
      LAYER Metal3 ;
        RECT 0.000 489.100 0.400 489.500 ;
    END
  END Tile_X0Y0_FrameData[3]
  PIN Tile_X0Y0_FrameData[4]
    DIRECTION INPUT ;
    USE SIGNAL ;
    ANTENNAGATEAREA 1.626300 ;
    PORT
      LAYER Metal3 ;
        RECT 0.000 490.780 0.400 491.180 ;
    END
  END Tile_X0Y0_FrameData[4]
  PIN Tile_X0Y0_FrameData[5]
    DIRECTION INPUT ;
    USE SIGNAL ;
    ANTENNAGATEAREA 1.626300 ;
    PORT
      LAYER Metal3 ;
        RECT 0.000 492.460 0.400 492.860 ;
    END
  END Tile_X0Y0_FrameData[5]
  PIN Tile_X0Y0_FrameData[6]
    DIRECTION INPUT ;
    USE SIGNAL ;
    ANTENNAGATEAREA 1.626300 ;
    PORT
      LAYER Metal3 ;
        RECT 0.000 494.140 0.400 494.540 ;
    END
  END Tile_X0Y0_FrameData[6]
  PIN Tile_X0Y0_FrameData[7]
    DIRECTION INPUT ;
    USE SIGNAL ;
    ANTENNAGATEAREA 1.626300 ;
    PORT
      LAYER Metal3 ;
        RECT 0.000 495.820 0.400 496.220 ;
    END
  END Tile_X0Y0_FrameData[7]
  PIN Tile_X0Y0_FrameData[8]
    DIRECTION INPUT ;
    USE SIGNAL ;
    ANTENNAGATEAREA 1.626300 ;
    PORT
      LAYER Metal3 ;
        RECT 0.000 497.500 0.400 497.900 ;
    END
  END Tile_X0Y0_FrameData[8]
  PIN Tile_X0Y0_FrameData[9]
    DIRECTION INPUT ;
    USE SIGNAL ;
    ANTENNAGATEAREA 1.626300 ;
    PORT
      LAYER Metal3 ;
        RECT 0.000 499.180 0.400 499.580 ;
    END
  END Tile_X0Y0_FrameData[9]
  PIN Tile_X0Y0_FrameData_O[0]
    DIRECTION OUTPUT ;
    USE SIGNAL ;
    ANTENNADIFFAREA 2.724000 ;
    PORT
      LAYER Metal3 ;
        RECT 136.400 295.060 136.800 295.460 ;
    END
  END Tile_X0Y0_FrameData_O[0]
  PIN Tile_X0Y0_FrameData_O[10]
    DIRECTION OUTPUT ;
    USE SIGNAL ;
    ANTENNADIFFAREA 2.724000 ;
    PORT
      LAYER Metal3 ;
        RECT 136.400 370.660 136.800 371.060 ;
    END
  END Tile_X0Y0_FrameData_O[10]
  PIN Tile_X0Y0_FrameData_O[11]
    DIRECTION OUTPUT ;
    USE SIGNAL ;
    ANTENNADIFFAREA 2.724000 ;
    PORT
      LAYER Metal3 ;
        RECT 136.400 378.220 136.800 378.620 ;
    END
  END Tile_X0Y0_FrameData_O[11]
  PIN Tile_X0Y0_FrameData_O[12]
    DIRECTION OUTPUT ;
    USE SIGNAL ;
    ANTENNADIFFAREA 2.724000 ;
    PORT
      LAYER Metal3 ;
        RECT 136.400 385.780 136.800 386.180 ;
    END
  END Tile_X0Y0_FrameData_O[12]
  PIN Tile_X0Y0_FrameData_O[13]
    DIRECTION OUTPUT ;
    USE SIGNAL ;
    ANTENNADIFFAREA 2.724000 ;
    PORT
      LAYER Metal3 ;
        RECT 136.400 393.340 136.800 393.740 ;
    END
  END Tile_X0Y0_FrameData_O[13]
  PIN Tile_X0Y0_FrameData_O[14]
    DIRECTION OUTPUT ;
    USE SIGNAL ;
    ANTENNADIFFAREA 2.724000 ;
    PORT
      LAYER Metal3 ;
        RECT 136.400 400.900 136.800 401.300 ;
    END
  END Tile_X0Y0_FrameData_O[14]
  PIN Tile_X0Y0_FrameData_O[15]
    DIRECTION OUTPUT ;
    USE SIGNAL ;
    ANTENNADIFFAREA 2.724000 ;
    PORT
      LAYER Metal3 ;
        RECT 136.400 408.460 136.800 408.860 ;
    END
  END Tile_X0Y0_FrameData_O[15]
  PIN Tile_X0Y0_FrameData_O[16]
    DIRECTION OUTPUT ;
    USE SIGNAL ;
    ANTENNADIFFAREA 2.724000 ;
    PORT
      LAYER Metal3 ;
        RECT 136.400 416.020 136.800 416.420 ;
    END
  END Tile_X0Y0_FrameData_O[16]
  PIN Tile_X0Y0_FrameData_O[17]
    DIRECTION OUTPUT ;
    USE SIGNAL ;
    ANTENNADIFFAREA 2.724000 ;
    PORT
      LAYER Metal3 ;
        RECT 136.400 423.580 136.800 423.980 ;
    END
  END Tile_X0Y0_FrameData_O[17]
  PIN Tile_X0Y0_FrameData_O[18]
    DIRECTION OUTPUT ;
    USE SIGNAL ;
    ANTENNADIFFAREA 2.724000 ;
    PORT
      LAYER Metal3 ;
        RECT 136.400 431.140 136.800 431.540 ;
    END
  END Tile_X0Y0_FrameData_O[18]
  PIN Tile_X0Y0_FrameData_O[19]
    DIRECTION OUTPUT ;
    USE SIGNAL ;
    ANTENNADIFFAREA 2.724000 ;
    PORT
      LAYER Metal3 ;
        RECT 136.400 438.700 136.800 439.100 ;
    END
  END Tile_X0Y0_FrameData_O[19]
  PIN Tile_X0Y0_FrameData_O[1]
    DIRECTION OUTPUT ;
    USE SIGNAL ;
    ANTENNADIFFAREA 2.724000 ;
    PORT
      LAYER Metal3 ;
        RECT 136.400 302.620 136.800 303.020 ;
    END
  END Tile_X0Y0_FrameData_O[1]
  PIN Tile_X0Y0_FrameData_O[20]
    DIRECTION OUTPUT ;
    USE SIGNAL ;
    ANTENNADIFFAREA 2.724000 ;
    PORT
      LAYER Metal3 ;
        RECT 136.400 446.260 136.800 446.660 ;
    END
  END Tile_X0Y0_FrameData_O[20]
  PIN Tile_X0Y0_FrameData_O[21]
    DIRECTION OUTPUT ;
    USE SIGNAL ;
    ANTENNADIFFAREA 2.724000 ;
    PORT
      LAYER Metal3 ;
        RECT 136.400 453.820 136.800 454.220 ;
    END
  END Tile_X0Y0_FrameData_O[21]
  PIN Tile_X0Y0_FrameData_O[22]
    DIRECTION OUTPUT ;
    USE SIGNAL ;
    ANTENNADIFFAREA 2.724000 ;
    PORT
      LAYER Metal3 ;
        RECT 136.400 461.380 136.800 461.780 ;
    END
  END Tile_X0Y0_FrameData_O[22]
  PIN Tile_X0Y0_FrameData_O[23]
    DIRECTION OUTPUT ;
    USE SIGNAL ;
    ANTENNADIFFAREA 2.724000 ;
    PORT
      LAYER Metal3 ;
        RECT 136.400 468.940 136.800 469.340 ;
    END
  END Tile_X0Y0_FrameData_O[23]
  PIN Tile_X0Y0_FrameData_O[24]
    DIRECTION OUTPUT ;
    USE SIGNAL ;
    ANTENNADIFFAREA 2.724000 ;
    PORT
      LAYER Metal3 ;
        RECT 136.400 476.500 136.800 476.900 ;
    END
  END Tile_X0Y0_FrameData_O[24]
  PIN Tile_X0Y0_FrameData_O[25]
    DIRECTION OUTPUT ;
    USE SIGNAL ;
    ANTENNADIFFAREA 2.724000 ;
    PORT
      LAYER Metal3 ;
        RECT 136.400 484.060 136.800 484.460 ;
    END
  END Tile_X0Y0_FrameData_O[25]
  PIN Tile_X0Y0_FrameData_O[26]
    DIRECTION OUTPUT ;
    USE SIGNAL ;
    ANTENNADIFFAREA 2.724000 ;
    PORT
      LAYER Metal3 ;
        RECT 136.400 491.620 136.800 492.020 ;
    END
  END Tile_X0Y0_FrameData_O[26]
  PIN Tile_X0Y0_FrameData_O[27]
    DIRECTION OUTPUT ;
    USE SIGNAL ;
    ANTENNADIFFAREA 2.724000 ;
    PORT
      LAYER Metal3 ;
        RECT 136.400 499.180 136.800 499.580 ;
    END
  END Tile_X0Y0_FrameData_O[27]
  PIN Tile_X0Y0_FrameData_O[28]
    DIRECTION OUTPUT ;
    USE SIGNAL ;
    ANTENNADIFFAREA 2.724000 ;
    PORT
      LAYER Metal3 ;
        RECT 136.400 506.740 136.800 507.140 ;
    END
  END Tile_X0Y0_FrameData_O[28]
  PIN Tile_X0Y0_FrameData_O[29]
    DIRECTION OUTPUT ;
    USE SIGNAL ;
    ANTENNADIFFAREA 2.724000 ;
    PORT
      LAYER Metal3 ;
        RECT 136.400 514.300 136.800 514.700 ;
    END
  END Tile_X0Y0_FrameData_O[29]
  PIN Tile_X0Y0_FrameData_O[2]
    DIRECTION OUTPUT ;
    USE SIGNAL ;
    ANTENNADIFFAREA 2.724000 ;
    PORT
      LAYER Metal3 ;
        RECT 136.400 310.180 136.800 310.580 ;
    END
  END Tile_X0Y0_FrameData_O[2]
  PIN Tile_X0Y0_FrameData_O[30]
    DIRECTION OUTPUT ;
    USE SIGNAL ;
    ANTENNADIFFAREA 2.724000 ;
    PORT
      LAYER Metal3 ;
        RECT 136.400 521.860 136.800 522.260 ;
    END
  END Tile_X0Y0_FrameData_O[30]
  PIN Tile_X0Y0_FrameData_O[31]
    DIRECTION OUTPUT ;
    USE SIGNAL ;
    ANTENNADIFFAREA 2.724000 ;
    PORT
      LAYER Metal3 ;
        RECT 136.400 529.420 136.800 529.820 ;
    END
  END Tile_X0Y0_FrameData_O[31]
  PIN Tile_X0Y0_FrameData_O[3]
    DIRECTION OUTPUT ;
    USE SIGNAL ;
    ANTENNADIFFAREA 2.724000 ;
    PORT
      LAYER Metal3 ;
        RECT 136.400 317.740 136.800 318.140 ;
    END
  END Tile_X0Y0_FrameData_O[3]
  PIN Tile_X0Y0_FrameData_O[4]
    DIRECTION OUTPUT ;
    USE SIGNAL ;
    ANTENNADIFFAREA 2.724000 ;
    PORT
      LAYER Metal3 ;
        RECT 136.400 325.300 136.800 325.700 ;
    END
  END Tile_X0Y0_FrameData_O[4]
  PIN Tile_X0Y0_FrameData_O[5]
    DIRECTION OUTPUT ;
    USE SIGNAL ;
    ANTENNADIFFAREA 2.724000 ;
    PORT
      LAYER Metal3 ;
        RECT 136.400 332.860 136.800 333.260 ;
    END
  END Tile_X0Y0_FrameData_O[5]
  PIN Tile_X0Y0_FrameData_O[6]
    DIRECTION OUTPUT ;
    USE SIGNAL ;
    ANTENNADIFFAREA 2.724000 ;
    PORT
      LAYER Metal3 ;
        RECT 136.400 340.420 136.800 340.820 ;
    END
  END Tile_X0Y0_FrameData_O[6]
  PIN Tile_X0Y0_FrameData_O[7]
    DIRECTION OUTPUT ;
    USE SIGNAL ;
    ANTENNADIFFAREA 2.724000 ;
    PORT
      LAYER Metal3 ;
        RECT 136.400 347.980 136.800 348.380 ;
    END
  END Tile_X0Y0_FrameData_O[7]
  PIN Tile_X0Y0_FrameData_O[8]
    DIRECTION OUTPUT ;
    USE SIGNAL ;
    ANTENNADIFFAREA 2.724000 ;
    PORT
      LAYER Metal3 ;
        RECT 136.400 355.540 136.800 355.940 ;
    END
  END Tile_X0Y0_FrameData_O[8]
  PIN Tile_X0Y0_FrameData_O[9]
    DIRECTION OUTPUT ;
    USE SIGNAL ;
    ANTENNADIFFAREA 2.724000 ;
    PORT
      LAYER Metal3 ;
        RECT 136.400 363.100 136.800 363.500 ;
    END
  END Tile_X0Y0_FrameData_O[9]
  PIN Tile_X0Y0_FrameStrobe_O[0]
    DIRECTION OUTPUT ;
    USE SIGNAL ;
    ANTENNADIFFAREA 2.724000 ;
    PORT
      LAYER Metal2 ;
        RECT 112.600 543.920 113.000 544.320 ;
    END
  END Tile_X0Y0_FrameStrobe_O[0]
  PIN Tile_X0Y0_FrameStrobe_O[10]
    DIRECTION OUTPUT ;
    USE SIGNAL ;
    ANTENNADIFFAREA 2.724000 ;
    PORT
      LAYER Metal2 ;
        RECT 122.200 543.920 122.600 544.320 ;
    END
  END Tile_X0Y0_FrameStrobe_O[10]
  PIN Tile_X0Y0_FrameStrobe_O[11]
    DIRECTION OUTPUT ;
    USE SIGNAL ;
    ANTENNADIFFAREA 2.724000 ;
    PORT
      LAYER Metal2 ;
        RECT 123.160 543.920 123.560 544.320 ;
    END
  END Tile_X0Y0_FrameStrobe_O[11]
  PIN Tile_X0Y0_FrameStrobe_O[12]
    DIRECTION OUTPUT ;
    USE SIGNAL ;
    ANTENNADIFFAREA 2.724000 ;
    PORT
      LAYER Metal2 ;
        RECT 124.120 543.920 124.520 544.320 ;
    END
  END Tile_X0Y0_FrameStrobe_O[12]
  PIN Tile_X0Y0_FrameStrobe_O[13]
    DIRECTION OUTPUT ;
    USE SIGNAL ;
    ANTENNADIFFAREA 2.724000 ;
    PORT
      LAYER Metal2 ;
        RECT 125.080 543.920 125.480 544.320 ;
    END
  END Tile_X0Y0_FrameStrobe_O[13]
  PIN Tile_X0Y0_FrameStrobe_O[14]
    DIRECTION OUTPUT ;
    USE SIGNAL ;
    ANTENNADIFFAREA 2.724000 ;
    PORT
      LAYER Metal2 ;
        RECT 126.040 543.920 126.440 544.320 ;
    END
  END Tile_X0Y0_FrameStrobe_O[14]
  PIN Tile_X0Y0_FrameStrobe_O[15]
    DIRECTION OUTPUT ;
    USE SIGNAL ;
    ANTENNADIFFAREA 2.724000 ;
    PORT
      LAYER Metal2 ;
        RECT 127.000 543.920 127.400 544.320 ;
    END
  END Tile_X0Y0_FrameStrobe_O[15]
  PIN Tile_X0Y0_FrameStrobe_O[16]
    DIRECTION OUTPUT ;
    USE SIGNAL ;
    ANTENNADIFFAREA 2.724000 ;
    PORT
      LAYER Metal2 ;
        RECT 127.960 543.920 128.360 544.320 ;
    END
  END Tile_X0Y0_FrameStrobe_O[16]
  PIN Tile_X0Y0_FrameStrobe_O[17]
    DIRECTION OUTPUT ;
    USE SIGNAL ;
    ANTENNADIFFAREA 2.724000 ;
    PORT
      LAYER Metal2 ;
        RECT 128.920 543.920 129.320 544.320 ;
    END
  END Tile_X0Y0_FrameStrobe_O[17]
  PIN Tile_X0Y0_FrameStrobe_O[18]
    DIRECTION OUTPUT ;
    USE SIGNAL ;
    ANTENNADIFFAREA 2.724000 ;
    PORT
      LAYER Metal2 ;
        RECT 129.880 543.920 130.280 544.320 ;
    END
  END Tile_X0Y0_FrameStrobe_O[18]
  PIN Tile_X0Y0_FrameStrobe_O[19]
    DIRECTION OUTPUT ;
    USE SIGNAL ;
    ANTENNADIFFAREA 2.724000 ;
    PORT
      LAYER Metal2 ;
        RECT 130.840 543.920 131.240 544.320 ;
    END
  END Tile_X0Y0_FrameStrobe_O[19]
  PIN Tile_X0Y0_FrameStrobe_O[1]
    DIRECTION OUTPUT ;
    USE SIGNAL ;
    ANTENNADIFFAREA 2.724000 ;
    PORT
      LAYER Metal2 ;
        RECT 113.560 543.920 113.960 544.320 ;
    END
  END Tile_X0Y0_FrameStrobe_O[1]
  PIN Tile_X0Y0_FrameStrobe_O[2]
    DIRECTION OUTPUT ;
    USE SIGNAL ;
    ANTENNADIFFAREA 2.724000 ;
    PORT
      LAYER Metal2 ;
        RECT 114.520 543.920 114.920 544.320 ;
    END
  END Tile_X0Y0_FrameStrobe_O[2]
  PIN Tile_X0Y0_FrameStrobe_O[3]
    DIRECTION OUTPUT ;
    USE SIGNAL ;
    ANTENNADIFFAREA 2.724000 ;
    PORT
      LAYER Metal2 ;
        RECT 115.480 543.920 115.880 544.320 ;
    END
  END Tile_X0Y0_FrameStrobe_O[3]
  PIN Tile_X0Y0_FrameStrobe_O[4]
    DIRECTION OUTPUT ;
    USE SIGNAL ;
    ANTENNADIFFAREA 2.724000 ;
    PORT
      LAYER Metal2 ;
        RECT 116.440 543.920 116.840 544.320 ;
    END
  END Tile_X0Y0_FrameStrobe_O[4]
  PIN Tile_X0Y0_FrameStrobe_O[5]
    DIRECTION OUTPUT ;
    USE SIGNAL ;
    ANTENNADIFFAREA 2.724000 ;
    PORT
      LAYER Metal2 ;
        RECT 117.400 543.920 117.800 544.320 ;
    END
  END Tile_X0Y0_FrameStrobe_O[5]
  PIN Tile_X0Y0_FrameStrobe_O[6]
    DIRECTION OUTPUT ;
    USE SIGNAL ;
    ANTENNADIFFAREA 2.724000 ;
    PORT
      LAYER Metal2 ;
        RECT 118.360 543.920 118.760 544.320 ;
    END
  END Tile_X0Y0_FrameStrobe_O[6]
  PIN Tile_X0Y0_FrameStrobe_O[7]
    DIRECTION OUTPUT ;
    USE SIGNAL ;
    ANTENNADIFFAREA 2.724000 ;
    PORT
      LAYER Metal2 ;
        RECT 119.320 543.920 119.720 544.320 ;
    END
  END Tile_X0Y0_FrameStrobe_O[7]
  PIN Tile_X0Y0_FrameStrobe_O[8]
    DIRECTION OUTPUT ;
    USE SIGNAL ;
    ANTENNADIFFAREA 2.724000 ;
    PORT
      LAYER Metal2 ;
        RECT 120.280 543.920 120.680 544.320 ;
    END
  END Tile_X0Y0_FrameStrobe_O[8]
  PIN Tile_X0Y0_FrameStrobe_O[9]
    DIRECTION OUTPUT ;
    USE SIGNAL ;
    ANTENNADIFFAREA 2.724000 ;
    PORT
      LAYER Metal2 ;
        RECT 121.240 543.920 121.640 544.320 ;
    END
  END Tile_X0Y0_FrameStrobe_O[9]
  PIN Tile_X0Y0_N1BEG[0]
    DIRECTION OUTPUT ;
    USE SIGNAL ;
    ANTENNADIFFAREA 2.724000 ;
    PORT
      LAYER Metal2 ;
        RECT 2.200 543.920 2.600 544.320 ;
    END
  END Tile_X0Y0_N1BEG[0]
  PIN Tile_X0Y0_N1BEG[1]
    DIRECTION OUTPUT ;
    USE SIGNAL ;
    ANTENNADIFFAREA 2.724000 ;
    PORT
      LAYER Metal2 ;
        RECT 3.160 543.920 3.560 544.320 ;
    END
  END Tile_X0Y0_N1BEG[1]
  PIN Tile_X0Y0_N1BEG[2]
    DIRECTION OUTPUT ;
    USE SIGNAL ;
    ANTENNADIFFAREA 2.724000 ;
    PORT
      LAYER Metal2 ;
        RECT 4.120 543.920 4.520 544.320 ;
    END
  END Tile_X0Y0_N1BEG[2]
  PIN Tile_X0Y0_N1BEG[3]
    DIRECTION OUTPUT ;
    USE SIGNAL ;
    ANTENNADIFFAREA 2.724000 ;
    PORT
      LAYER Metal2 ;
        RECT 5.080 543.920 5.480 544.320 ;
    END
  END Tile_X0Y0_N1BEG[3]
  PIN Tile_X0Y0_N2BEG[0]
    DIRECTION OUTPUT ;
    USE SIGNAL ;
    ANTENNADIFFAREA 2.724000 ;
    PORT
      LAYER Metal2 ;
        RECT 8.920 543.920 9.320 544.320 ;
    END
  END Tile_X0Y0_N2BEG[0]
  PIN Tile_X0Y0_N2BEG[1]
    DIRECTION OUTPUT ;
    USE SIGNAL ;
    ANTENNADIFFAREA 2.724000 ;
    PORT
      LAYER Metal2 ;
        RECT 9.880 543.920 10.280 544.320 ;
    END
  END Tile_X0Y0_N2BEG[1]
  PIN Tile_X0Y0_N2BEG[2]
    DIRECTION OUTPUT ;
    USE SIGNAL ;
    ANTENNADIFFAREA 2.724000 ;
    PORT
      LAYER Metal2 ;
        RECT 10.840 543.920 11.240 544.320 ;
    END
  END Tile_X0Y0_N2BEG[2]
  PIN Tile_X0Y0_N2BEG[3]
    DIRECTION OUTPUT ;
    USE SIGNAL ;
    ANTENNADIFFAREA 2.724000 ;
    PORT
      LAYER Metal2 ;
        RECT 11.800 543.920 12.200 544.320 ;
    END
  END Tile_X0Y0_N2BEG[3]
  PIN Tile_X0Y0_N2BEG[4]
    DIRECTION OUTPUT ;
    USE SIGNAL ;
    ANTENNADIFFAREA 2.724000 ;
    PORT
      LAYER Metal2 ;
        RECT 12.760 543.920 13.160 544.320 ;
    END
  END Tile_X0Y0_N2BEG[4]
  PIN Tile_X0Y0_N2BEG[5]
    DIRECTION OUTPUT ;
    USE SIGNAL ;
    ANTENNADIFFAREA 2.724000 ;
    PORT
      LAYER Metal2 ;
        RECT 13.720 543.920 14.120 544.320 ;
    END
  END Tile_X0Y0_N2BEG[5]
  PIN Tile_X0Y0_N2BEG[6]
    DIRECTION OUTPUT ;
    USE SIGNAL ;
    ANTENNADIFFAREA 2.724000 ;
    PORT
      LAYER Metal2 ;
        RECT 14.680 543.920 15.080 544.320 ;
    END
  END Tile_X0Y0_N2BEG[6]
  PIN Tile_X0Y0_N2BEG[7]
    DIRECTION OUTPUT ;
    USE SIGNAL ;
    ANTENNADIFFAREA 2.724000 ;
    PORT
      LAYER Metal2 ;
        RECT 15.640 543.920 16.040 544.320 ;
    END
  END Tile_X0Y0_N2BEG[7]
  PIN Tile_X0Y0_N2BEGb[0]
    DIRECTION OUTPUT ;
    USE SIGNAL ;
    ANTENNADIFFAREA 2.724000 ;
    PORT
      LAYER Metal2 ;
        RECT 20.440 543.920 20.840 544.320 ;
    END
  END Tile_X0Y0_N2BEGb[0]
  PIN Tile_X0Y0_N2BEGb[1]
    DIRECTION OUTPUT ;
    USE SIGNAL ;
    ANTENNADIFFAREA 2.724000 ;
    PORT
      LAYER Metal2 ;
        RECT 21.400 543.920 21.800 544.320 ;
    END
  END Tile_X0Y0_N2BEGb[1]
  PIN Tile_X0Y0_N2BEGb[2]
    DIRECTION OUTPUT ;
    USE SIGNAL ;
    ANTENNADIFFAREA 2.724000 ;
    PORT
      LAYER Metal2 ;
        RECT 22.360 543.920 22.760 544.320 ;
    END
  END Tile_X0Y0_N2BEGb[2]
  PIN Tile_X0Y0_N2BEGb[3]
    DIRECTION OUTPUT ;
    USE SIGNAL ;
    ANTENNADIFFAREA 2.724000 ;
    PORT
      LAYER Metal2 ;
        RECT 23.320 543.920 23.720 544.320 ;
    END
  END Tile_X0Y0_N2BEGb[3]
  PIN Tile_X0Y0_N2BEGb[4]
    DIRECTION OUTPUT ;
    USE SIGNAL ;
    ANTENNADIFFAREA 2.724000 ;
    PORT
      LAYER Metal2 ;
        RECT 24.280 543.920 24.680 544.320 ;
    END
  END Tile_X0Y0_N2BEGb[4]
  PIN Tile_X0Y0_N2BEGb[5]
    DIRECTION OUTPUT ;
    USE SIGNAL ;
    ANTENNADIFFAREA 2.724000 ;
    PORT
      LAYER Metal2 ;
        RECT 25.240 543.920 25.640 544.320 ;
    END
  END Tile_X0Y0_N2BEGb[5]
  PIN Tile_X0Y0_N2BEGb[6]
    DIRECTION OUTPUT ;
    USE SIGNAL ;
    ANTENNADIFFAREA 2.724000 ;
    PORT
      LAYER Metal2 ;
        RECT 26.200 543.920 26.600 544.320 ;
    END
  END Tile_X0Y0_N2BEGb[6]
  PIN Tile_X0Y0_N2BEGb[7]
    DIRECTION OUTPUT ;
    USE SIGNAL ;
    ANTENNADIFFAREA 2.724000 ;
    PORT
      LAYER Metal2 ;
        RECT 27.160 543.920 27.560 544.320 ;
    END
  END Tile_X0Y0_N2BEGb[7]
  PIN Tile_X0Y0_N4BEG[0]
    DIRECTION OUTPUT ;
    USE SIGNAL ;
    ANTENNADIFFAREA 2.724000 ;
    PORT
      LAYER Metal2 ;
        RECT 33.880 543.920 34.280 544.320 ;
    END
  END Tile_X0Y0_N4BEG[0]
  PIN Tile_X0Y0_N4BEG[10]
    DIRECTION OUTPUT ;
    USE SIGNAL ;
    ANTENNADIFFAREA 2.724000 ;
    PORT
      LAYER Metal2 ;
        RECT 43.480 543.920 43.880 544.320 ;
    END
  END Tile_X0Y0_N4BEG[10]
  PIN Tile_X0Y0_N4BEG[11]
    DIRECTION OUTPUT ;
    USE SIGNAL ;
    ANTENNADIFFAREA 2.724000 ;
    PORT
      LAYER Metal2 ;
        RECT 44.440 543.920 44.840 544.320 ;
    END
  END Tile_X0Y0_N4BEG[11]
  PIN Tile_X0Y0_N4BEG[12]
    DIRECTION OUTPUT ;
    USE SIGNAL ;
    ANTENNADIFFAREA 2.724000 ;
    PORT
      LAYER Metal2 ;
        RECT 45.400 543.920 45.800 544.320 ;
    END
  END Tile_X0Y0_N4BEG[12]
  PIN Tile_X0Y0_N4BEG[13]
    DIRECTION OUTPUT ;
    USE SIGNAL ;
    ANTENNADIFFAREA 2.724000 ;
    PORT
      LAYER Metal2 ;
        RECT 46.360 543.920 46.760 544.320 ;
    END
  END Tile_X0Y0_N4BEG[13]
  PIN Tile_X0Y0_N4BEG[14]
    DIRECTION OUTPUT ;
    USE SIGNAL ;
    ANTENNADIFFAREA 2.724000 ;
    PORT
      LAYER Metal2 ;
        RECT 47.320 543.920 47.720 544.320 ;
    END
  END Tile_X0Y0_N4BEG[14]
  PIN Tile_X0Y0_N4BEG[15]
    DIRECTION OUTPUT ;
    USE SIGNAL ;
    ANTENNADIFFAREA 2.724000 ;
    PORT
      LAYER Metal2 ;
        RECT 48.280 543.920 48.680 544.320 ;
    END
  END Tile_X0Y0_N4BEG[15]
  PIN Tile_X0Y0_N4BEG[1]
    DIRECTION OUTPUT ;
    USE SIGNAL ;
    ANTENNADIFFAREA 2.724000 ;
    PORT
      LAYER Metal2 ;
        RECT 34.840 543.920 35.240 544.320 ;
    END
  END Tile_X0Y0_N4BEG[1]
  PIN Tile_X0Y0_N4BEG[2]
    DIRECTION OUTPUT ;
    USE SIGNAL ;
    ANTENNADIFFAREA 2.724000 ;
    PORT
      LAYER Metal2 ;
        RECT 35.800 543.920 36.200 544.320 ;
    END
  END Tile_X0Y0_N4BEG[2]
  PIN Tile_X0Y0_N4BEG[3]
    DIRECTION OUTPUT ;
    USE SIGNAL ;
    ANTENNADIFFAREA 2.724000 ;
    PORT
      LAYER Metal2 ;
        RECT 36.760 543.920 37.160 544.320 ;
    END
  END Tile_X0Y0_N4BEG[3]
  PIN Tile_X0Y0_N4BEG[4]
    DIRECTION OUTPUT ;
    USE SIGNAL ;
    ANTENNADIFFAREA 2.724000 ;
    PORT
      LAYER Metal2 ;
        RECT 37.720 543.920 38.120 544.320 ;
    END
  END Tile_X0Y0_N4BEG[4]
  PIN Tile_X0Y0_N4BEG[5]
    DIRECTION OUTPUT ;
    USE SIGNAL ;
    ANTENNADIFFAREA 2.724000 ;
    PORT
      LAYER Metal2 ;
        RECT 38.680 543.920 39.080 544.320 ;
    END
  END Tile_X0Y0_N4BEG[5]
  PIN Tile_X0Y0_N4BEG[6]
    DIRECTION OUTPUT ;
    USE SIGNAL ;
    ANTENNADIFFAREA 2.724000 ;
    PORT
      LAYER Metal2 ;
        RECT 39.640 543.920 40.040 544.320 ;
    END
  END Tile_X0Y0_N4BEG[6]
  PIN Tile_X0Y0_N4BEG[7]
    DIRECTION OUTPUT ;
    USE SIGNAL ;
    ANTENNADIFFAREA 2.724000 ;
    PORT
      LAYER Metal2 ;
        RECT 40.600 543.920 41.000 544.320 ;
    END
  END Tile_X0Y0_N4BEG[7]
  PIN Tile_X0Y0_N4BEG[8]
    DIRECTION OUTPUT ;
    USE SIGNAL ;
    ANTENNADIFFAREA 2.724000 ;
    PORT
      LAYER Metal2 ;
        RECT 41.560 543.920 41.960 544.320 ;
    END
  END Tile_X0Y0_N4BEG[8]
  PIN Tile_X0Y0_N4BEG[9]
    DIRECTION OUTPUT ;
    USE SIGNAL ;
    ANTENNADIFFAREA 2.724000 ;
    PORT
      LAYER Metal2 ;
        RECT 42.520 543.920 42.920 544.320 ;
    END
  END Tile_X0Y0_N4BEG[9]
  PIN Tile_X0Y0_S1END[0]
    DIRECTION INPUT ;
    USE SIGNAL ;
    ANTENNAGATEAREA 1.279200 ;
    PORT
      LAYER Metal2 ;
        RECT 55.000 543.920 55.400 544.320 ;
    END
  END Tile_X0Y0_S1END[0]
  PIN Tile_X0Y0_S1END[1]
    DIRECTION INPUT ;
    USE SIGNAL ;
    ANTENNAGATEAREA 1.279200 ;
    PORT
      LAYER Metal2 ;
        RECT 55.960 543.920 56.360 544.320 ;
    END
  END Tile_X0Y0_S1END[1]
  PIN Tile_X0Y0_S1END[2]
    DIRECTION INPUT ;
    USE SIGNAL ;
    ANTENNAGATEAREA 1.279200 ;
    PORT
      LAYER Metal2 ;
        RECT 56.920 543.920 57.320 544.320 ;
    END
  END Tile_X0Y0_S1END[2]
  PIN Tile_X0Y0_S1END[3]
    DIRECTION INPUT ;
    USE SIGNAL ;
    ANTENNAGATEAREA 1.279200 ;
    PORT
      LAYER Metal2 ;
        RECT 57.880 543.920 58.280 544.320 ;
    END
  END Tile_X0Y0_S1END[3]
  PIN Tile_X0Y0_S2END[0]
    DIRECTION INPUT ;
    USE SIGNAL ;
    ANTENNAGATEAREA 0.213200 ;
    PORT
      LAYER Metal2 ;
        RECT 73.240 543.920 73.640 544.320 ;
    END
  END Tile_X0Y0_S2END[0]
  PIN Tile_X0Y0_S2END[1]
    DIRECTION INPUT ;
    USE SIGNAL ;
    ANTENNAGATEAREA 0.213200 ;
    PORT
      LAYER Metal2 ;
        RECT 74.200 543.920 74.600 544.320 ;
    END
  END Tile_X0Y0_S2END[1]
  PIN Tile_X0Y0_S2END[2]
    DIRECTION INPUT ;
    USE SIGNAL ;
    ANTENNAGATEAREA 0.213200 ;
    PORT
      LAYER Metal2 ;
        RECT 75.160 543.920 75.560 544.320 ;
    END
  END Tile_X0Y0_S2END[2]
  PIN Tile_X0Y0_S2END[3]
    DIRECTION INPUT ;
    USE SIGNAL ;
    ANTENNAGATEAREA 0.213200 ;
    PORT
      LAYER Metal2 ;
        RECT 76.120 543.920 76.520 544.320 ;
    END
  END Tile_X0Y0_S2END[3]
  PIN Tile_X0Y0_S2END[4]
    DIRECTION INPUT ;
    USE SIGNAL ;
    ANTENNAGATEAREA 0.213200 ;
    PORT
      LAYER Metal2 ;
        RECT 77.080 543.920 77.480 544.320 ;
    END
  END Tile_X0Y0_S2END[4]
  PIN Tile_X0Y0_S2END[5]
    DIRECTION INPUT ;
    USE SIGNAL ;
    ANTENNAGATEAREA 0.213200 ;
    PORT
      LAYER Metal2 ;
        RECT 78.040 543.920 78.440 544.320 ;
    END
  END Tile_X0Y0_S2END[5]
  PIN Tile_X0Y0_S2END[6]
    DIRECTION INPUT ;
    USE SIGNAL ;
    ANTENNAGATEAREA 0.213200 ;
    PORT
      LAYER Metal2 ;
        RECT 79.000 543.920 79.400 544.320 ;
    END
  END Tile_X0Y0_S2END[6]
  PIN Tile_X0Y0_S2END[7]
    DIRECTION INPUT ;
    USE SIGNAL ;
    ANTENNAGATEAREA 0.213200 ;
    PORT
      LAYER Metal2 ;
        RECT 79.960 543.920 80.360 544.320 ;
    END
  END Tile_X0Y0_S2END[7]
  PIN Tile_X0Y0_S2MID[0]
    DIRECTION INPUT ;
    USE SIGNAL ;
    ANTENNAGATEAREA 0.426400 ;
    ANTENNADIFFAREA 4.030800 ;
    PORT
      LAYER Metal2 ;
        RECT 61.720 543.920 62.120 544.320 ;
    END
  END Tile_X0Y0_S2MID[0]
  PIN Tile_X0Y0_S2MID[1]
    DIRECTION INPUT ;
    USE SIGNAL ;
    ANTENNAGATEAREA 0.426400 ;
    ANTENNADIFFAREA 4.030800 ;
    PORT
      LAYER Metal2 ;
        RECT 62.680 543.920 63.080 544.320 ;
    END
  END Tile_X0Y0_S2MID[1]
  PIN Tile_X0Y0_S2MID[2]
    DIRECTION INPUT ;
    USE SIGNAL ;
    ANTENNAGATEAREA 0.426400 ;
    ANTENNADIFFAREA 4.030800 ;
    PORT
      LAYER Metal2 ;
        RECT 63.640 543.920 64.040 544.320 ;
    END
  END Tile_X0Y0_S2MID[2]
  PIN Tile_X0Y0_S2MID[3]
    DIRECTION INPUT ;
    USE SIGNAL ;
    ANTENNAGATEAREA 0.426400 ;
    ANTENNADIFFAREA 4.030800 ;
    PORT
      LAYER Metal2 ;
        RECT 64.600 543.920 65.000 544.320 ;
    END
  END Tile_X0Y0_S2MID[3]
  PIN Tile_X0Y0_S2MID[4]
    DIRECTION INPUT ;
    USE SIGNAL ;
    ANTENNAGATEAREA 0.426400 ;
    ANTENNADIFFAREA 4.030800 ;
    PORT
      LAYER Metal2 ;
        RECT 65.560 543.920 65.960 544.320 ;
    END
  END Tile_X0Y0_S2MID[4]
  PIN Tile_X0Y0_S2MID[5]
    DIRECTION INPUT ;
    USE SIGNAL ;
    ANTENNAGATEAREA 0.426400 ;
    ANTENNADIFFAREA 4.030800 ;
    PORT
      LAYER Metal2 ;
        RECT 66.520 543.920 66.920 544.320 ;
    END
  END Tile_X0Y0_S2MID[5]
  PIN Tile_X0Y0_S2MID[6]
    DIRECTION INPUT ;
    USE SIGNAL ;
    ANTENNAGATEAREA 0.426400 ;
    ANTENNADIFFAREA 4.030800 ;
    PORT
      LAYER Metal2 ;
        RECT 67.480 543.920 67.880 544.320 ;
    END
  END Tile_X0Y0_S2MID[6]
  PIN Tile_X0Y0_S2MID[7]
    DIRECTION INPUT ;
    USE SIGNAL ;
    ANTENNAGATEAREA 0.426400 ;
    ANTENNADIFFAREA 4.030800 ;
    PORT
      LAYER Metal2 ;
        RECT 68.440 543.920 68.840 544.320 ;
    END
  END Tile_X0Y0_S2MID[7]
  PIN Tile_X0Y0_S4END[0]
    DIRECTION INPUT ;
    USE SIGNAL ;
    ANTENNAGATEAREA 1.066000 ;
    PORT
      LAYER Metal2 ;
        RECT 87.640 543.920 88.040 544.320 ;
    END
  END Tile_X0Y0_S4END[0]
  PIN Tile_X0Y0_S4END[10]
    DIRECTION INPUT ;
    USE SIGNAL ;
    ANTENNAGATEAREA 0.180700 ;
    PORT
      LAYER Metal2 ;
        RECT 97.240 543.920 97.640 544.320 ;
    END
  END Tile_X0Y0_S4END[10]
  PIN Tile_X0Y0_S4END[11]
    DIRECTION INPUT ;
    USE SIGNAL ;
    ANTENNAGATEAREA 0.180700 ;
    PORT
      LAYER Metal2 ;
        RECT 98.200 543.920 98.600 544.320 ;
    END
  END Tile_X0Y0_S4END[11]
  PIN Tile_X0Y0_S4END[12]
    DIRECTION INPUT ;
    USE SIGNAL ;
    ANTENNAGATEAREA 0.180700 ;
    ANTENNADIFFAREA 2.015400 ;
    PORT
      LAYER Metal2 ;
        RECT 99.160 543.920 99.560 544.320 ;
    END
  END Tile_X0Y0_S4END[12]
  PIN Tile_X0Y0_S4END[13]
    DIRECTION INPUT ;
    USE SIGNAL ;
    ANTENNAGATEAREA 0.180700 ;
    PORT
      LAYER Metal2 ;
        RECT 100.120 543.920 100.520 544.320 ;
    END
  END Tile_X0Y0_S4END[13]
  PIN Tile_X0Y0_S4END[14]
    DIRECTION INPUT ;
    USE SIGNAL ;
    ANTENNAGATEAREA 0.180700 ;
    ANTENNADIFFAREA 2.015400 ;
    PORT
      LAYER Metal2 ;
        RECT 101.080 543.920 101.480 544.320 ;
    END
  END Tile_X0Y0_S4END[14]
  PIN Tile_X0Y0_S4END[15]
    DIRECTION INPUT ;
    USE SIGNAL ;
    ANTENNAGATEAREA 0.180700 ;
    ANTENNADIFFAREA 2.015400 ;
    PORT
      LAYER Metal2 ;
        RECT 102.040 543.920 102.440 544.320 ;
    END
  END Tile_X0Y0_S4END[15]
  PIN Tile_X0Y0_S4END[1]
    DIRECTION INPUT ;
    USE SIGNAL ;
    ANTENNAGATEAREA 1.066000 ;
    PORT
      LAYER Metal2 ;
        RECT 88.600 543.920 89.000 544.320 ;
    END
  END Tile_X0Y0_S4END[1]
  PIN Tile_X0Y0_S4END[2]
    DIRECTION INPUT ;
    USE SIGNAL ;
    ANTENNAGATEAREA 1.066000 ;
    PORT
      LAYER Metal2 ;
        RECT 89.560 543.920 89.960 544.320 ;
    END
  END Tile_X0Y0_S4END[2]
  PIN Tile_X0Y0_S4END[3]
    DIRECTION INPUT ;
    USE SIGNAL ;
    ANTENNAGATEAREA 1.066000 ;
    PORT
      LAYER Metal2 ;
        RECT 90.520 543.920 90.920 544.320 ;
    END
  END Tile_X0Y0_S4END[3]
  PIN Tile_X0Y0_S4END[4]
    DIRECTION INPUT ;
    USE SIGNAL ;
    ANTENNAGATEAREA 1.066000 ;
    PORT
      LAYER Metal2 ;
        RECT 91.480 543.920 91.880 544.320 ;
    END
  END Tile_X0Y0_S4END[4]
  PIN Tile_X0Y0_S4END[5]
    DIRECTION INPUT ;
    USE SIGNAL ;
    ANTENNAGATEAREA 1.066000 ;
    PORT
      LAYER Metal2 ;
        RECT 92.440 543.920 92.840 544.320 ;
    END
  END Tile_X0Y0_S4END[5]
  PIN Tile_X0Y0_S4END[6]
    DIRECTION INPUT ;
    USE SIGNAL ;
    ANTENNAGATEAREA 1.066000 ;
    PORT
      LAYER Metal2 ;
        RECT 93.400 543.920 93.800 544.320 ;
    END
  END Tile_X0Y0_S4END[6]
  PIN Tile_X0Y0_S4END[7]
    DIRECTION INPUT ;
    USE SIGNAL ;
    ANTENNAGATEAREA 1.066000 ;
    PORT
      LAYER Metal2 ;
        RECT 94.360 543.920 94.760 544.320 ;
    END
  END Tile_X0Y0_S4END[7]
  PIN Tile_X0Y0_S4END[8]
    DIRECTION INPUT ;
    USE SIGNAL ;
    ANTENNAGATEAREA 0.180700 ;
    PORT
      LAYER Metal2 ;
        RECT 95.320 543.920 95.720 544.320 ;
    END
  END Tile_X0Y0_S4END[8]
  PIN Tile_X0Y0_S4END[9]
    DIRECTION INPUT ;
    USE SIGNAL ;
    ANTENNAGATEAREA 0.180700 ;
    PORT
      LAYER Metal2 ;
        RECT 96.280 543.920 96.680 544.320 ;
    END
  END Tile_X0Y0_S4END[9]
  PIN Tile_X0Y0_UserCLK
    DIRECTION INPUT ;
    USE SIGNAL ;
    ANTENNAGATEAREA 0.180700 ;
    PORT
      LAYER Metal3 ;
        RECT 0.000 475.660 0.400 476.060 ;
    END
  END Tile_X0Y0_UserCLK
  PIN Tile_X0Y0_UserCLKo
    DIRECTION OUTPUT ;
    USE SIGNAL ;
    ANTENNADIFFAREA 2.724000 ;
    PORT
      LAYER Metal3 ;
        RECT 136.400 276.580 136.800 276.980 ;
    END
  END Tile_X0Y0_UserCLKo
  PIN Tile_X0Y0_W1BEG[0]
    DIRECTION OUTPUT ;
    USE SIGNAL ;
    ANTENNADIFFAREA 2.724000 ;
    PORT
      LAYER Metal3 ;
        RECT 0.000 374.860 0.400 375.260 ;
    END
  END Tile_X0Y0_W1BEG[0]
  PIN Tile_X0Y0_W1BEG[1]
    DIRECTION OUTPUT ;
    USE SIGNAL ;
    ANTENNADIFFAREA 2.724000 ;
    PORT
      LAYER Metal3 ;
        RECT 0.000 376.540 0.400 376.940 ;
    END
  END Tile_X0Y0_W1BEG[1]
  PIN Tile_X0Y0_W1BEG[2]
    DIRECTION OUTPUT ;
    USE SIGNAL ;
    ANTENNADIFFAREA 2.724000 ;
    PORT
      LAYER Metal3 ;
        RECT 0.000 378.220 0.400 378.620 ;
    END
  END Tile_X0Y0_W1BEG[2]
  PIN Tile_X0Y0_W1BEG[3]
    DIRECTION OUTPUT ;
    USE SIGNAL ;
    ANTENNADIFFAREA 2.724000 ;
    PORT
      LAYER Metal3 ;
        RECT 0.000 379.900 0.400 380.300 ;
    END
  END Tile_X0Y0_W1BEG[3]
  PIN Tile_X0Y0_W2BEG[0]
    DIRECTION OUTPUT ;
    USE SIGNAL ;
    ANTENNADIFFAREA 2.724000 ;
    PORT
      LAYER Metal3 ;
        RECT 0.000 384.100 0.400 384.500 ;
    END
  END Tile_X0Y0_W2BEG[0]
  PIN Tile_X0Y0_W2BEG[1]
    DIRECTION OUTPUT ;
    USE SIGNAL ;
    ANTENNADIFFAREA 2.724000 ;
    PORT
      LAYER Metal3 ;
        RECT 0.000 385.780 0.400 386.180 ;
    END
  END Tile_X0Y0_W2BEG[1]
  PIN Tile_X0Y0_W2BEG[2]
    DIRECTION OUTPUT ;
    USE SIGNAL ;
    ANTENNADIFFAREA 2.724000 ;
    PORT
      LAYER Metal3 ;
        RECT 0.000 387.460 0.400 387.860 ;
    END
  END Tile_X0Y0_W2BEG[2]
  PIN Tile_X0Y0_W2BEG[3]
    DIRECTION OUTPUT ;
    USE SIGNAL ;
    ANTENNADIFFAREA 2.724000 ;
    PORT
      LAYER Metal3 ;
        RECT 0.000 389.140 0.400 389.540 ;
    END
  END Tile_X0Y0_W2BEG[3]
  PIN Tile_X0Y0_W2BEG[4]
    DIRECTION OUTPUT ;
    USE SIGNAL ;
    ANTENNADIFFAREA 2.724000 ;
    PORT
      LAYER Metal3 ;
        RECT 0.000 390.820 0.400 391.220 ;
    END
  END Tile_X0Y0_W2BEG[4]
  PIN Tile_X0Y0_W2BEG[5]
    DIRECTION OUTPUT ;
    USE SIGNAL ;
    ANTENNADIFFAREA 2.724000 ;
    PORT
      LAYER Metal3 ;
        RECT 0.000 392.500 0.400 392.900 ;
    END
  END Tile_X0Y0_W2BEG[5]
  PIN Tile_X0Y0_W2BEG[6]
    DIRECTION OUTPUT ;
    USE SIGNAL ;
    ANTENNADIFFAREA 2.724000 ;
    PORT
      LAYER Metal3 ;
        RECT 0.000 394.180 0.400 394.580 ;
    END
  END Tile_X0Y0_W2BEG[6]
  PIN Tile_X0Y0_W2BEG[7]
    DIRECTION OUTPUT ;
    USE SIGNAL ;
    ANTENNADIFFAREA 2.724000 ;
    PORT
      LAYER Metal3 ;
        RECT 0.000 395.860 0.400 396.260 ;
    END
  END Tile_X0Y0_W2BEG[7]
  PIN Tile_X0Y0_W2BEGb[0]
    DIRECTION OUTPUT ;
    USE SIGNAL ;
    ANTENNADIFFAREA 2.724000 ;
    PORT
      LAYER Metal3 ;
        RECT 0.000 400.900 0.400 401.300 ;
    END
  END Tile_X0Y0_W2BEGb[0]
  PIN Tile_X0Y0_W2BEGb[1]
    DIRECTION OUTPUT ;
    USE SIGNAL ;
    ANTENNADIFFAREA 2.724000 ;
    PORT
      LAYER Metal3 ;
        RECT 0.000 402.580 0.400 402.980 ;
    END
  END Tile_X0Y0_W2BEGb[1]
  PIN Tile_X0Y0_W2BEGb[2]
    DIRECTION OUTPUT ;
    USE SIGNAL ;
    ANTENNADIFFAREA 2.724000 ;
    PORT
      LAYER Metal3 ;
        RECT 0.000 404.260 0.400 404.660 ;
    END
  END Tile_X0Y0_W2BEGb[2]
  PIN Tile_X0Y0_W2BEGb[3]
    DIRECTION OUTPUT ;
    USE SIGNAL ;
    ANTENNADIFFAREA 2.724000 ;
    PORT
      LAYER Metal3 ;
        RECT 0.000 405.940 0.400 406.340 ;
    END
  END Tile_X0Y0_W2BEGb[3]
  PIN Tile_X0Y0_W2BEGb[4]
    DIRECTION OUTPUT ;
    USE SIGNAL ;
    ANTENNADIFFAREA 2.724000 ;
    PORT
      LAYER Metal3 ;
        RECT 0.000 407.620 0.400 408.020 ;
    END
  END Tile_X0Y0_W2BEGb[4]
  PIN Tile_X0Y0_W2BEGb[5]
    DIRECTION OUTPUT ;
    USE SIGNAL ;
    ANTENNADIFFAREA 2.724000 ;
    PORT
      LAYER Metal3 ;
        RECT 0.000 409.300 0.400 409.700 ;
    END
  END Tile_X0Y0_W2BEGb[5]
  PIN Tile_X0Y0_W2BEGb[6]
    DIRECTION OUTPUT ;
    USE SIGNAL ;
    ANTENNADIFFAREA 2.724000 ;
    PORT
      LAYER Metal3 ;
        RECT 0.000 410.980 0.400 411.380 ;
    END
  END Tile_X0Y0_W2BEGb[6]
  PIN Tile_X0Y0_W2BEGb[7]
    DIRECTION OUTPUT ;
    USE SIGNAL ;
    ANTENNADIFFAREA 2.724000 ;
    PORT
      LAYER Metal3 ;
        RECT 0.000 412.660 0.400 413.060 ;
    END
  END Tile_X0Y0_W2BEGb[7]
  PIN Tile_X0Y0_W6BEG[0]
    DIRECTION OUTPUT ;
    USE SIGNAL ;
    ANTENNADIFFAREA 2.724000 ;
    PORT
      LAYER Metal3 ;
        RECT 0.000 452.140 0.400 452.540 ;
    END
  END Tile_X0Y0_W6BEG[0]
  PIN Tile_X0Y0_W6BEG[10]
    DIRECTION OUTPUT ;
    USE SIGNAL ;
    ANTENNADIFFAREA 2.724000 ;
    PORT
      LAYER Metal3 ;
        RECT 0.000 468.940 0.400 469.340 ;
    END
  END Tile_X0Y0_W6BEG[10]
  PIN Tile_X0Y0_W6BEG[11]
    DIRECTION OUTPUT ;
    USE SIGNAL ;
    ANTENNADIFFAREA 2.724000 ;
    PORT
      LAYER Metal3 ;
        RECT 0.000 470.620 0.400 471.020 ;
    END
  END Tile_X0Y0_W6BEG[11]
  PIN Tile_X0Y0_W6BEG[1]
    DIRECTION OUTPUT ;
    USE SIGNAL ;
    ANTENNADIFFAREA 2.724000 ;
    PORT
      LAYER Metal3 ;
        RECT 0.000 453.820 0.400 454.220 ;
    END
  END Tile_X0Y0_W6BEG[1]
  PIN Tile_X0Y0_W6BEG[2]
    DIRECTION OUTPUT ;
    USE SIGNAL ;
    ANTENNADIFFAREA 2.724000 ;
    PORT
      LAYER Metal3 ;
        RECT 0.000 455.500 0.400 455.900 ;
    END
  END Tile_X0Y0_W6BEG[2]
  PIN Tile_X0Y0_W6BEG[3]
    DIRECTION OUTPUT ;
    USE SIGNAL ;
    ANTENNADIFFAREA 2.724000 ;
    PORT
      LAYER Metal3 ;
        RECT 0.000 457.180 0.400 457.580 ;
    END
  END Tile_X0Y0_W6BEG[3]
  PIN Tile_X0Y0_W6BEG[4]
    DIRECTION OUTPUT ;
    USE SIGNAL ;
    ANTENNADIFFAREA 2.724000 ;
    PORT
      LAYER Metal3 ;
        RECT 0.000 458.860 0.400 459.260 ;
    END
  END Tile_X0Y0_W6BEG[4]
  PIN Tile_X0Y0_W6BEG[5]
    DIRECTION OUTPUT ;
    USE SIGNAL ;
    ANTENNADIFFAREA 2.724000 ;
    PORT
      LAYER Metal3 ;
        RECT 0.000 460.540 0.400 460.940 ;
    END
  END Tile_X0Y0_W6BEG[5]
  PIN Tile_X0Y0_W6BEG[6]
    DIRECTION OUTPUT ;
    USE SIGNAL ;
    ANTENNADIFFAREA 2.724000 ;
    PORT
      LAYER Metal3 ;
        RECT 0.000 462.220 0.400 462.620 ;
    END
  END Tile_X0Y0_W6BEG[6]
  PIN Tile_X0Y0_W6BEG[7]
    DIRECTION OUTPUT ;
    USE SIGNAL ;
    ANTENNADIFFAREA 2.724000 ;
    PORT
      LAYER Metal3 ;
        RECT 0.000 463.900 0.400 464.300 ;
    END
  END Tile_X0Y0_W6BEG[7]
  PIN Tile_X0Y0_W6BEG[8]
    DIRECTION OUTPUT ;
    USE SIGNAL ;
    ANTENNADIFFAREA 2.724000 ;
    PORT
      LAYER Metal3 ;
        RECT 0.000 465.580 0.400 465.980 ;
    END
  END Tile_X0Y0_W6BEG[8]
  PIN Tile_X0Y0_W6BEG[9]
    DIRECTION OUTPUT ;
    USE SIGNAL ;
    ANTENNADIFFAREA 2.724000 ;
    PORT
      LAYER Metal3 ;
        RECT 0.000 467.260 0.400 467.660 ;
    END
  END Tile_X0Y0_W6BEG[9]
  PIN Tile_X0Y0_WW4BEG[0]
    DIRECTION OUTPUT ;
    USE SIGNAL ;
    ANTENNADIFFAREA 2.724000 ;
    PORT
      LAYER Metal3 ;
        RECT 0.000 419.380 0.400 419.780 ;
    END
  END Tile_X0Y0_WW4BEG[0]
  PIN Tile_X0Y0_WW4BEG[10]
    DIRECTION OUTPUT ;
    USE SIGNAL ;
    ANTENNADIFFAREA 2.724000 ;
    PORT
      LAYER Metal3 ;
        RECT 0.000 436.180 0.400 436.580 ;
    END
  END Tile_X0Y0_WW4BEG[10]
  PIN Tile_X0Y0_WW4BEG[11]
    DIRECTION OUTPUT ;
    USE SIGNAL ;
    ANTENNADIFFAREA 2.724000 ;
    PORT
      LAYER Metal3 ;
        RECT 0.000 437.860 0.400 438.260 ;
    END
  END Tile_X0Y0_WW4BEG[11]
  PIN Tile_X0Y0_WW4BEG[12]
    DIRECTION OUTPUT ;
    USE SIGNAL ;
    ANTENNADIFFAREA 2.724000 ;
    PORT
      LAYER Metal3 ;
        RECT 0.000 439.540 0.400 439.940 ;
    END
  END Tile_X0Y0_WW4BEG[12]
  PIN Tile_X0Y0_WW4BEG[13]
    DIRECTION OUTPUT ;
    USE SIGNAL ;
    ANTENNADIFFAREA 2.724000 ;
    PORT
      LAYER Metal3 ;
        RECT 0.000 441.220 0.400 441.620 ;
    END
  END Tile_X0Y0_WW4BEG[13]
  PIN Tile_X0Y0_WW4BEG[14]
    DIRECTION OUTPUT ;
    USE SIGNAL ;
    ANTENNADIFFAREA 2.724000 ;
    PORT
      LAYER Metal3 ;
        RECT 0.000 442.900 0.400 443.300 ;
    END
  END Tile_X0Y0_WW4BEG[14]
  PIN Tile_X0Y0_WW4BEG[15]
    DIRECTION OUTPUT ;
    USE SIGNAL ;
    ANTENNADIFFAREA 2.724000 ;
    PORT
      LAYER Metal3 ;
        RECT 0.000 444.580 0.400 444.980 ;
    END
  END Tile_X0Y0_WW4BEG[15]
  PIN Tile_X0Y0_WW4BEG[1]
    DIRECTION OUTPUT ;
    USE SIGNAL ;
    ANTENNADIFFAREA 2.724000 ;
    PORT
      LAYER Metal3 ;
        RECT 0.000 421.060 0.400 421.460 ;
    END
  END Tile_X0Y0_WW4BEG[1]
  PIN Tile_X0Y0_WW4BEG[2]
    DIRECTION OUTPUT ;
    USE SIGNAL ;
    ANTENNADIFFAREA 2.724000 ;
    PORT
      LAYER Metal3 ;
        RECT 0.000 422.740 0.400 423.140 ;
    END
  END Tile_X0Y0_WW4BEG[2]
  PIN Tile_X0Y0_WW4BEG[3]
    DIRECTION OUTPUT ;
    USE SIGNAL ;
    ANTENNADIFFAREA 2.724000 ;
    PORT
      LAYER Metal3 ;
        RECT 0.000 424.420 0.400 424.820 ;
    END
  END Tile_X0Y0_WW4BEG[3]
  PIN Tile_X0Y0_WW4BEG[4]
    DIRECTION OUTPUT ;
    USE SIGNAL ;
    ANTENNADIFFAREA 2.724000 ;
    PORT
      LAYER Metal3 ;
        RECT 0.000 426.100 0.400 426.500 ;
    END
  END Tile_X0Y0_WW4BEG[4]
  PIN Tile_X0Y0_WW4BEG[5]
    DIRECTION OUTPUT ;
    USE SIGNAL ;
    ANTENNADIFFAREA 2.724000 ;
    PORT
      LAYER Metal3 ;
        RECT 0.000 427.780 0.400 428.180 ;
    END
  END Tile_X0Y0_WW4BEG[5]
  PIN Tile_X0Y0_WW4BEG[6]
    DIRECTION OUTPUT ;
    USE SIGNAL ;
    ANTENNADIFFAREA 2.724000 ;
    PORT
      LAYER Metal3 ;
        RECT 0.000 429.460 0.400 429.860 ;
    END
  END Tile_X0Y0_WW4BEG[6]
  PIN Tile_X0Y0_WW4BEG[7]
    DIRECTION OUTPUT ;
    USE SIGNAL ;
    ANTENNADIFFAREA 2.724000 ;
    PORT
      LAYER Metal3 ;
        RECT 0.000 431.140 0.400 431.540 ;
    END
  END Tile_X0Y0_WW4BEG[7]
  PIN Tile_X0Y0_WW4BEG[8]
    DIRECTION OUTPUT ;
    USE SIGNAL ;
    ANTENNADIFFAREA 2.724000 ;
    PORT
      LAYER Metal3 ;
        RECT 0.000 432.820 0.400 433.220 ;
    END
  END Tile_X0Y0_WW4BEG[8]
  PIN Tile_X0Y0_WW4BEG[9]
    DIRECTION OUTPUT ;
    USE SIGNAL ;
    ANTENNADIFFAREA 2.724000 ;
    PORT
      LAYER Metal3 ;
        RECT 0.000 434.500 0.400 434.900 ;
    END
  END Tile_X0Y0_WW4BEG[9]
  PIN Tile_X0Y1_E1END[0]
    DIRECTION INPUT ;
    USE SIGNAL ;
    ANTENNAGATEAREA 1.279200 ;
    PORT
      LAYER Metal3 ;
        RECT 0.000 1.900 0.400 2.300 ;
    END
  END Tile_X0Y1_E1END[0]
  PIN Tile_X0Y1_E1END[1]
    DIRECTION INPUT ;
    USE SIGNAL ;
    ANTENNAGATEAREA 1.279200 ;
    PORT
      LAYER Metal3 ;
        RECT 0.000 3.580 0.400 3.980 ;
    END
  END Tile_X0Y1_E1END[1]
  PIN Tile_X0Y1_E1END[2]
    DIRECTION INPUT ;
    USE SIGNAL ;
    ANTENNAGATEAREA 1.279200 ;
    PORT
      LAYER Metal3 ;
        RECT 0.000 5.260 0.400 5.660 ;
    END
  END Tile_X0Y1_E1END[2]
  PIN Tile_X0Y1_E1END[3]
    DIRECTION INPUT ;
    USE SIGNAL ;
    ANTENNAGATEAREA 1.279200 ;
    PORT
      LAYER Metal3 ;
        RECT 0.000 6.940 0.400 7.340 ;
    END
  END Tile_X0Y1_E1END[3]
  PIN Tile_X0Y1_E2END[0]
    DIRECTION INPUT ;
    USE SIGNAL ;
    ANTENNAGATEAREA 0.426400 ;
    PORT
      LAYER Metal3 ;
        RECT 0.000 27.940 0.400 28.340 ;
    END
  END Tile_X0Y1_E2END[0]
  PIN Tile_X0Y1_E2END[1]
    DIRECTION INPUT ;
    USE SIGNAL ;
    ANTENNAGATEAREA 0.426400 ;
    PORT
      LAYER Metal3 ;
        RECT 0.000 29.620 0.400 30.020 ;
    END
  END Tile_X0Y1_E2END[1]
  PIN Tile_X0Y1_E2END[2]
    DIRECTION INPUT ;
    USE SIGNAL ;
    ANTENNAGATEAREA 0.639600 ;
    PORT
      LAYER Metal3 ;
        RECT 0.000 31.300 0.400 31.700 ;
    END
  END Tile_X0Y1_E2END[2]
  PIN Tile_X0Y1_E2END[3]
    DIRECTION INPUT ;
    USE SIGNAL ;
    ANTENNAGATEAREA 0.639600 ;
    PORT
      LAYER Metal3 ;
        RECT 0.000 32.980 0.400 33.380 ;
    END
  END Tile_X0Y1_E2END[3]
  PIN Tile_X0Y1_E2END[4]
    DIRECTION INPUT ;
    USE SIGNAL ;
    ANTENNAGATEAREA 0.426400 ;
    PORT
      LAYER Metal3 ;
        RECT 0.000 34.660 0.400 35.060 ;
    END
  END Tile_X0Y1_E2END[4]
  PIN Tile_X0Y1_E2END[5]
    DIRECTION INPUT ;
    USE SIGNAL ;
    ANTENNAGATEAREA 0.426400 ;
    PORT
      LAYER Metal3 ;
        RECT 0.000 36.340 0.400 36.740 ;
    END
  END Tile_X0Y1_E2END[5]
  PIN Tile_X0Y1_E2END[6]
    DIRECTION INPUT ;
    USE SIGNAL ;
    ANTENNAGATEAREA 0.426400 ;
    PORT
      LAYER Metal3 ;
        RECT 0.000 38.020 0.400 38.420 ;
    END
  END Tile_X0Y1_E2END[6]
  PIN Tile_X0Y1_E2END[7]
    DIRECTION INPUT ;
    USE SIGNAL ;
    ANTENNAGATEAREA 0.426400 ;
    PORT
      LAYER Metal3 ;
        RECT 0.000 39.700 0.400 40.100 ;
    END
  END Tile_X0Y1_E2END[7]
  PIN Tile_X0Y1_E2MID[0]
    DIRECTION INPUT ;
    USE SIGNAL ;
    ANTENNAGATEAREA 0.639600 ;
    PORT
      LAYER Metal3 ;
        RECT 0.000 11.140 0.400 11.540 ;
    END
  END Tile_X0Y1_E2MID[0]
  PIN Tile_X0Y1_E2MID[1]
    DIRECTION INPUT ;
    USE SIGNAL ;
    ANTENNAGATEAREA 0.639600 ;
    PORT
      LAYER Metal3 ;
        RECT 0.000 12.820 0.400 13.220 ;
    END
  END Tile_X0Y1_E2MID[1]
  PIN Tile_X0Y1_E2MID[2]
    DIRECTION INPUT ;
    USE SIGNAL ;
    ANTENNAGATEAREA 0.639600 ;
    PORT
      LAYER Metal3 ;
        RECT 0.000 14.500 0.400 14.900 ;
    END
  END Tile_X0Y1_E2MID[2]
  PIN Tile_X0Y1_E2MID[3]
    DIRECTION INPUT ;
    USE SIGNAL ;
    ANTENNAGATEAREA 0.639600 ;
    PORT
      LAYER Metal3 ;
        RECT 0.000 16.180 0.400 16.580 ;
    END
  END Tile_X0Y1_E2MID[3]
  PIN Tile_X0Y1_E2MID[4]
    DIRECTION INPUT ;
    USE SIGNAL ;
    ANTENNAGATEAREA 0.639600 ;
    PORT
      LAYER Metal3 ;
        RECT 0.000 17.860 0.400 18.260 ;
    END
  END Tile_X0Y1_E2MID[4]
  PIN Tile_X0Y1_E2MID[5]
    DIRECTION INPUT ;
    USE SIGNAL ;
    ANTENNAGATEAREA 0.639600 ;
    PORT
      LAYER Metal3 ;
        RECT 0.000 19.540 0.400 19.940 ;
    END
  END Tile_X0Y1_E2MID[5]
  PIN Tile_X0Y1_E2MID[6]
    DIRECTION INPUT ;
    USE SIGNAL ;
    ANTENNAGATEAREA 0.426400 ;
    PORT
      LAYER Metal3 ;
        RECT 0.000 21.220 0.400 21.620 ;
    END
  END Tile_X0Y1_E2MID[6]
  PIN Tile_X0Y1_E2MID[7]
    DIRECTION INPUT ;
    USE SIGNAL ;
    ANTENNAGATEAREA 0.426400 ;
    PORT
      LAYER Metal3 ;
        RECT 0.000 22.900 0.400 23.300 ;
    END
  END Tile_X0Y1_E2MID[7]
  PIN Tile_X0Y1_E6END[0]
    DIRECTION INPUT ;
    USE SIGNAL ;
    ANTENNAGATEAREA 0.639600 ;
    PORT
      LAYER Metal3 ;
        RECT 0.000 79.180 0.400 79.580 ;
    END
  END Tile_X0Y1_E6END[0]
  PIN Tile_X0Y1_E6END[10]
    DIRECTION INPUT ;
    USE SIGNAL ;
    ANTENNAGATEAREA 0.852800 ;
    PORT
      LAYER Metal3 ;
        RECT 0.000 95.980 0.400 96.380 ;
    END
  END Tile_X0Y1_E6END[10]
  PIN Tile_X0Y1_E6END[11]
    DIRECTION INPUT ;
    USE SIGNAL ;
    ANTENNAGATEAREA 0.852800 ;
    PORT
      LAYER Metal3 ;
        RECT 0.000 97.660 0.400 98.060 ;
    END
  END Tile_X0Y1_E6END[11]
  PIN Tile_X0Y1_E6END[1]
    DIRECTION INPUT ;
    USE SIGNAL ;
    ANTENNAGATEAREA 0.639600 ;
    PORT
      LAYER Metal3 ;
        RECT 0.000 80.860 0.400 81.260 ;
    END
  END Tile_X0Y1_E6END[1]
  PIN Tile_X0Y1_E6END[2]
    DIRECTION INPUT ;
    USE SIGNAL ;
    ANTENNAGATEAREA 0.639600 ;
    PORT
      LAYER Metal3 ;
        RECT 0.000 82.540 0.400 82.940 ;
    END
  END Tile_X0Y1_E6END[2]
  PIN Tile_X0Y1_E6END[3]
    DIRECTION INPUT ;
    USE SIGNAL ;
    ANTENNAGATEAREA 0.639600 ;
    PORT
      LAYER Metal3 ;
        RECT 0.000 84.220 0.400 84.620 ;
    END
  END Tile_X0Y1_E6END[3]
  PIN Tile_X0Y1_E6END[4]
    DIRECTION INPUT ;
    USE SIGNAL ;
    ANTENNAGATEAREA 0.852800 ;
    PORT
      LAYER Metal3 ;
        RECT 0.000 85.900 0.400 86.300 ;
    END
  END Tile_X0Y1_E6END[4]
  PIN Tile_X0Y1_E6END[5]
    DIRECTION INPUT ;
    USE SIGNAL ;
    ANTENNAGATEAREA 0.852800 ;
    PORT
      LAYER Metal3 ;
        RECT 0.000 87.580 0.400 87.980 ;
    END
  END Tile_X0Y1_E6END[5]
  PIN Tile_X0Y1_E6END[6]
    DIRECTION INPUT ;
    USE SIGNAL ;
    ANTENNAGATEAREA 0.852800 ;
    PORT
      LAYER Metal3 ;
        RECT 0.000 89.260 0.400 89.660 ;
    END
  END Tile_X0Y1_E6END[6]
  PIN Tile_X0Y1_E6END[7]
    DIRECTION INPUT ;
    USE SIGNAL ;
    ANTENNAGATEAREA 0.852800 ;
    PORT
      LAYER Metal3 ;
        RECT 0.000 90.940 0.400 91.340 ;
    END
  END Tile_X0Y1_E6END[7]
  PIN Tile_X0Y1_E6END[8]
    DIRECTION INPUT ;
    USE SIGNAL ;
    ANTENNAGATEAREA 0.852800 ;
    PORT
      LAYER Metal3 ;
        RECT 0.000 92.620 0.400 93.020 ;
    END
  END Tile_X0Y1_E6END[8]
  PIN Tile_X0Y1_E6END[9]
    DIRECTION INPUT ;
    USE SIGNAL ;
    ANTENNAGATEAREA 0.852800 ;
    PORT
      LAYER Metal3 ;
        RECT 0.000 94.300 0.400 94.700 ;
    END
  END Tile_X0Y1_E6END[9]
  PIN Tile_X0Y1_EE4END[0]
    DIRECTION INPUT ;
    USE SIGNAL ;
    ANTENNAGATEAREA 0.639600 ;
    PORT
      LAYER Metal3 ;
        RECT 0.000 46.420 0.400 46.820 ;
    END
  END Tile_X0Y1_EE4END[0]
  PIN Tile_X0Y1_EE4END[10]
    DIRECTION INPUT ;
    USE SIGNAL ;
    ANTENNAGATEAREA 0.426400 ;
    PORT
      LAYER Metal3 ;
        RECT 0.000 63.220 0.400 63.620 ;
    END
  END Tile_X0Y1_EE4END[10]
  PIN Tile_X0Y1_EE4END[11]
    DIRECTION INPUT ;
    USE SIGNAL ;
    ANTENNAGATEAREA 0.426400 ;
    PORT
      LAYER Metal3 ;
        RECT 0.000 64.900 0.400 65.300 ;
    END
  END Tile_X0Y1_EE4END[11]
  PIN Tile_X0Y1_EE4END[12]
    DIRECTION INPUT ;
    USE SIGNAL ;
    ANTENNAGATEAREA 0.639600 ;
    PORT
      LAYER Metal3 ;
        RECT 0.000 66.580 0.400 66.980 ;
    END
  END Tile_X0Y1_EE4END[12]
  PIN Tile_X0Y1_EE4END[13]
    DIRECTION INPUT ;
    USE SIGNAL ;
    ANTENNAGATEAREA 0.639600 ;
    PORT
      LAYER Metal3 ;
        RECT 0.000 68.260 0.400 68.660 ;
    END
  END Tile_X0Y1_EE4END[13]
  PIN Tile_X0Y1_EE4END[14]
    DIRECTION INPUT ;
    USE SIGNAL ;
    ANTENNAGATEAREA 0.639600 ;
    PORT
      LAYER Metal3 ;
        RECT 0.000 69.940 0.400 70.340 ;
    END
  END Tile_X0Y1_EE4END[14]
  PIN Tile_X0Y1_EE4END[15]
    DIRECTION INPUT ;
    USE SIGNAL ;
    ANTENNAGATEAREA 0.639600 ;
    PORT
      LAYER Metal3 ;
        RECT 0.000 71.620 0.400 72.020 ;
    END
  END Tile_X0Y1_EE4END[15]
  PIN Tile_X0Y1_EE4END[1]
    DIRECTION INPUT ;
    USE SIGNAL ;
    ANTENNAGATEAREA 0.639600 ;
    PORT
      LAYER Metal3 ;
        RECT 0.000 48.100 0.400 48.500 ;
    END
  END Tile_X0Y1_EE4END[1]
  PIN Tile_X0Y1_EE4END[2]
    DIRECTION INPUT ;
    USE SIGNAL ;
    ANTENNAGATEAREA 0.639600 ;
    PORT
      LAYER Metal3 ;
        RECT 0.000 49.780 0.400 50.180 ;
    END
  END Tile_X0Y1_EE4END[2]
  PIN Tile_X0Y1_EE4END[3]
    DIRECTION INPUT ;
    USE SIGNAL ;
    ANTENNAGATEAREA 0.639600 ;
    PORT
      LAYER Metal3 ;
        RECT 0.000 51.460 0.400 51.860 ;
    END
  END Tile_X0Y1_EE4END[3]
  PIN Tile_X0Y1_EE4END[4]
    DIRECTION INPUT ;
    USE SIGNAL ;
    ANTENNAGATEAREA 0.639600 ;
    PORT
      LAYER Metal3 ;
        RECT 0.000 53.140 0.400 53.540 ;
    END
  END Tile_X0Y1_EE4END[4]
  PIN Tile_X0Y1_EE4END[5]
    DIRECTION INPUT ;
    USE SIGNAL ;
    ANTENNAGATEAREA 0.639600 ;
    PORT
      LAYER Metal3 ;
        RECT 0.000 54.820 0.400 55.220 ;
    END
  END Tile_X0Y1_EE4END[5]
  PIN Tile_X0Y1_EE4END[6]
    DIRECTION INPUT ;
    USE SIGNAL ;
    ANTENNAGATEAREA 0.426400 ;
    PORT
      LAYER Metal3 ;
        RECT 0.000 56.500 0.400 56.900 ;
    END
  END Tile_X0Y1_EE4END[6]
  PIN Tile_X0Y1_EE4END[7]
    DIRECTION INPUT ;
    USE SIGNAL ;
    ANTENNAGATEAREA 0.426400 ;
    PORT
      LAYER Metal3 ;
        RECT 0.000 58.180 0.400 58.580 ;
    END
  END Tile_X0Y1_EE4END[7]
  PIN Tile_X0Y1_EE4END[8]
    DIRECTION INPUT ;
    USE SIGNAL ;
    ANTENNAGATEAREA 0.639600 ;
    PORT
      LAYER Metal3 ;
        RECT 0.000 59.860 0.400 60.260 ;
    END
  END Tile_X0Y1_EE4END[8]
  PIN Tile_X0Y1_EE4END[9]
    DIRECTION INPUT ;
    USE SIGNAL ;
    ANTENNAGATEAREA 0.639600 ;
    PORT
      LAYER Metal3 ;
        RECT 0.000 61.540 0.400 61.940 ;
    END
  END Tile_X0Y1_EE4END[9]
  PIN Tile_X0Y1_FrameData[0]
    DIRECTION INPUT ;
    USE SIGNAL ;
    ANTENNAGATEAREA 1.626300 ;
    PORT
      LAYER Metal3 ;
        RECT 0.000 211.900 0.400 212.300 ;
    END
  END Tile_X0Y1_FrameData[0]
  PIN Tile_X0Y1_FrameData[10]
    DIRECTION INPUT ;
    USE SIGNAL ;
    ANTENNAGATEAREA 1.626300 ;
    PORT
      LAYER Metal3 ;
        RECT 0.000 228.700 0.400 229.100 ;
    END
  END Tile_X0Y1_FrameData[10]
  PIN Tile_X0Y1_FrameData[11]
    DIRECTION INPUT ;
    USE SIGNAL ;
    ANTENNAGATEAREA 1.626300 ;
    PORT
      LAYER Metal3 ;
        RECT 0.000 230.380 0.400 230.780 ;
    END
  END Tile_X0Y1_FrameData[11]
  PIN Tile_X0Y1_FrameData[12]
    DIRECTION INPUT ;
    USE SIGNAL ;
    ANTENNAGATEAREA 1.626300 ;
    PORT
      LAYER Metal3 ;
        RECT 0.000 232.060 0.400 232.460 ;
    END
  END Tile_X0Y1_FrameData[12]
  PIN Tile_X0Y1_FrameData[13]
    DIRECTION INPUT ;
    USE SIGNAL ;
    ANTENNAGATEAREA 1.626300 ;
    PORT
      LAYER Metal3 ;
        RECT 0.000 233.740 0.400 234.140 ;
    END
  END Tile_X0Y1_FrameData[13]
  PIN Tile_X0Y1_FrameData[14]
    DIRECTION INPUT ;
    USE SIGNAL ;
    ANTENNAGATEAREA 1.626300 ;
    PORT
      LAYER Metal3 ;
        RECT 0.000 235.420 0.400 235.820 ;
    END
  END Tile_X0Y1_FrameData[14]
  PIN Tile_X0Y1_FrameData[15]
    DIRECTION INPUT ;
    USE SIGNAL ;
    ANTENNAGATEAREA 1.626300 ;
    PORT
      LAYER Metal3 ;
        RECT 0.000 237.100 0.400 237.500 ;
    END
  END Tile_X0Y1_FrameData[15]
  PIN Tile_X0Y1_FrameData[16]
    DIRECTION INPUT ;
    USE SIGNAL ;
    ANTENNAGATEAREA 1.626300 ;
    PORT
      LAYER Metal3 ;
        RECT 0.000 238.780 0.400 239.180 ;
    END
  END Tile_X0Y1_FrameData[16]
  PIN Tile_X0Y1_FrameData[17]
    DIRECTION INPUT ;
    USE SIGNAL ;
    ANTENNAGATEAREA 1.626300 ;
    PORT
      LAYER Metal3 ;
        RECT 0.000 240.460 0.400 240.860 ;
    END
  END Tile_X0Y1_FrameData[17]
  PIN Tile_X0Y1_FrameData[18]
    DIRECTION INPUT ;
    USE SIGNAL ;
    ANTENNAGATEAREA 1.626300 ;
    PORT
      LAYER Metal3 ;
        RECT 0.000 242.140 0.400 242.540 ;
    END
  END Tile_X0Y1_FrameData[18]
  PIN Tile_X0Y1_FrameData[19]
    DIRECTION INPUT ;
    USE SIGNAL ;
    ANTENNAGATEAREA 1.626300 ;
    ANTENNADIFFAREA 50.384998 ;
    PORT
      LAYER Metal3 ;
        RECT 0.000 243.820 0.400 244.220 ;
    END
  END Tile_X0Y1_FrameData[19]
  PIN Tile_X0Y1_FrameData[1]
    DIRECTION INPUT ;
    USE SIGNAL ;
    ANTENNAGATEAREA 1.626300 ;
    PORT
      LAYER Metal3 ;
        RECT 0.000 213.580 0.400 213.980 ;
    END
  END Tile_X0Y1_FrameData[1]
  PIN Tile_X0Y1_FrameData[20]
    DIRECTION INPUT ;
    USE SIGNAL ;
    ANTENNAGATEAREA 1.626300 ;
    PORT
      LAYER Metal3 ;
        RECT 0.000 245.500 0.400 245.900 ;
    END
  END Tile_X0Y1_FrameData[20]
  PIN Tile_X0Y1_FrameData[21]
    DIRECTION INPUT ;
    USE SIGNAL ;
    ANTENNAGATEAREA 1.626300 ;
    PORT
      LAYER Metal3 ;
        RECT 0.000 247.180 0.400 247.580 ;
    END
  END Tile_X0Y1_FrameData[21]
  PIN Tile_X0Y1_FrameData[22]
    DIRECTION INPUT ;
    USE SIGNAL ;
    ANTENNAGATEAREA 1.626300 ;
    PORT
      LAYER Metal3 ;
        RECT 0.000 248.860 0.400 249.260 ;
    END
  END Tile_X0Y1_FrameData[22]
  PIN Tile_X0Y1_FrameData[23]
    DIRECTION INPUT ;
    USE SIGNAL ;
    ANTENNAGATEAREA 1.626300 ;
    ANTENNADIFFAREA 42.323399 ;
    PORT
      LAYER Metal3 ;
        RECT 0.000 250.540 0.400 250.940 ;
    END
  END Tile_X0Y1_FrameData[23]
  PIN Tile_X0Y1_FrameData[24]
    DIRECTION INPUT ;
    USE SIGNAL ;
    ANTENNAGATEAREA 1.626300 ;
    PORT
      LAYER Metal3 ;
        RECT 0.000 252.220 0.400 252.620 ;
    END
  END Tile_X0Y1_FrameData[24]
  PIN Tile_X0Y1_FrameData[25]
    DIRECTION INPUT ;
    USE SIGNAL ;
    ANTENNAGATEAREA 1.626300 ;
    PORT
      LAYER Metal3 ;
        RECT 0.000 253.900 0.400 254.300 ;
    END
  END Tile_X0Y1_FrameData[25]
  PIN Tile_X0Y1_FrameData[26]
    DIRECTION INPUT ;
    USE SIGNAL ;
    ANTENNAGATEAREA 1.807000 ;
    PORT
      LAYER Metal3 ;
        RECT 0.000 255.580 0.400 255.980 ;
    END
  END Tile_X0Y1_FrameData[26]
  PIN Tile_X0Y1_FrameData[27]
    DIRECTION INPUT ;
    USE SIGNAL ;
    ANTENNAGATEAREA 1.807000 ;
    PORT
      LAYER Metal3 ;
        RECT 0.000 257.260 0.400 257.660 ;
    END
  END Tile_X0Y1_FrameData[27]
  PIN Tile_X0Y1_FrameData[28]
    DIRECTION INPUT ;
    USE SIGNAL ;
    ANTENNAGATEAREA 1.807000 ;
    PORT
      LAYER Metal3 ;
        RECT 0.000 258.940 0.400 259.340 ;
    END
  END Tile_X0Y1_FrameData[28]
  PIN Tile_X0Y1_FrameData[29]
    DIRECTION INPUT ;
    USE SIGNAL ;
    ANTENNAGATEAREA 1.807000 ;
    PORT
      LAYER Metal3 ;
        RECT 0.000 260.620 0.400 261.020 ;
    END
  END Tile_X0Y1_FrameData[29]
  PIN Tile_X0Y1_FrameData[2]
    DIRECTION INPUT ;
    USE SIGNAL ;
    ANTENNAGATEAREA 1.626300 ;
    PORT
      LAYER Metal3 ;
        RECT 0.000 215.260 0.400 215.660 ;
    END
  END Tile_X0Y1_FrameData[2]
  PIN Tile_X0Y1_FrameData[30]
    DIRECTION INPUT ;
    USE SIGNAL ;
    ANTENNAGATEAREA 1.807000 ;
    PORT
      LAYER Metal3 ;
        RECT 0.000 262.300 0.400 262.700 ;
    END
  END Tile_X0Y1_FrameData[30]
  PIN Tile_X0Y1_FrameData[31]
    DIRECTION INPUT ;
    USE SIGNAL ;
    ANTENNAGATEAREA 1.807000 ;
    PORT
      LAYER Metal3 ;
        RECT 0.000 263.980 0.400 264.380 ;
    END
  END Tile_X0Y1_FrameData[31]
  PIN Tile_X0Y1_FrameData[3]
    DIRECTION INPUT ;
    USE SIGNAL ;
    ANTENNAGATEAREA 1.626300 ;
    PORT
      LAYER Metal3 ;
        RECT 0.000 216.940 0.400 217.340 ;
    END
  END Tile_X0Y1_FrameData[3]
  PIN Tile_X0Y1_FrameData[4]
    DIRECTION INPUT ;
    USE SIGNAL ;
    ANTENNAGATEAREA 1.626300 ;
    PORT
      LAYER Metal3 ;
        RECT 0.000 218.620 0.400 219.020 ;
    END
  END Tile_X0Y1_FrameData[4]
  PIN Tile_X0Y1_FrameData[5]
    DIRECTION INPUT ;
    USE SIGNAL ;
    ANTENNAGATEAREA 1.626300 ;
    PORT
      LAYER Metal3 ;
        RECT 0.000 220.300 0.400 220.700 ;
    END
  END Tile_X0Y1_FrameData[5]
  PIN Tile_X0Y1_FrameData[6]
    DIRECTION INPUT ;
    USE SIGNAL ;
    ANTENNAGATEAREA 1.626300 ;
    PORT
      LAYER Metal3 ;
        RECT 0.000 221.980 0.400 222.380 ;
    END
  END Tile_X0Y1_FrameData[6]
  PIN Tile_X0Y1_FrameData[7]
    DIRECTION INPUT ;
    USE SIGNAL ;
    ANTENNAGATEAREA 1.626300 ;
    PORT
      LAYER Metal3 ;
        RECT 0.000 223.660 0.400 224.060 ;
    END
  END Tile_X0Y1_FrameData[7]
  PIN Tile_X0Y1_FrameData[8]
    DIRECTION INPUT ;
    USE SIGNAL ;
    ANTENNAGATEAREA 1.626300 ;
    PORT
      LAYER Metal3 ;
        RECT 0.000 225.340 0.400 225.740 ;
    END
  END Tile_X0Y1_FrameData[8]
  PIN Tile_X0Y1_FrameData[9]
    DIRECTION INPUT ;
    USE SIGNAL ;
    ANTENNAGATEAREA 1.626300 ;
    PORT
      LAYER Metal3 ;
        RECT 0.000 227.020 0.400 227.420 ;
    END
  END Tile_X0Y1_FrameData[9]
  PIN Tile_X0Y1_FrameData_O[0]
    DIRECTION OUTPUT ;
    USE SIGNAL ;
    ANTENNADIFFAREA 2.724000 ;
    PORT
      LAYER Metal3 ;
        RECT 136.400 5.260 136.800 5.660 ;
    END
  END Tile_X0Y1_FrameData_O[0]
  PIN Tile_X0Y1_FrameData_O[10]
    DIRECTION OUTPUT ;
    USE SIGNAL ;
    ANTENNADIFFAREA 2.724000 ;
    PORT
      LAYER Metal3 ;
        RECT 136.400 38.860 136.800 39.260 ;
    END
  END Tile_X0Y1_FrameData_O[10]
  PIN Tile_X0Y1_FrameData_O[11]
    DIRECTION OUTPUT ;
    USE SIGNAL ;
    ANTENNADIFFAREA 2.724000 ;
    PORT
      LAYER Metal3 ;
        RECT 136.400 42.220 136.800 42.620 ;
    END
  END Tile_X0Y1_FrameData_O[11]
  PIN Tile_X0Y1_FrameData_O[12]
    DIRECTION OUTPUT ;
    USE SIGNAL ;
    ANTENNADIFFAREA 2.724000 ;
    PORT
      LAYER Metal3 ;
        RECT 136.400 45.580 136.800 45.980 ;
    END
  END Tile_X0Y1_FrameData_O[12]
  PIN Tile_X0Y1_FrameData_O[13]
    DIRECTION OUTPUT ;
    USE SIGNAL ;
    ANTENNADIFFAREA 2.724000 ;
    PORT
      LAYER Metal3 ;
        RECT 136.400 48.940 136.800 49.340 ;
    END
  END Tile_X0Y1_FrameData_O[13]
  PIN Tile_X0Y1_FrameData_O[14]
    DIRECTION OUTPUT ;
    USE SIGNAL ;
    ANTENNADIFFAREA 2.724000 ;
    PORT
      LAYER Metal3 ;
        RECT 136.400 52.300 136.800 52.700 ;
    END
  END Tile_X0Y1_FrameData_O[14]
  PIN Tile_X0Y1_FrameData_O[15]
    DIRECTION OUTPUT ;
    USE SIGNAL ;
    ANTENNADIFFAREA 2.724000 ;
    PORT
      LAYER Metal3 ;
        RECT 136.400 55.660 136.800 56.060 ;
    END
  END Tile_X0Y1_FrameData_O[15]
  PIN Tile_X0Y1_FrameData_O[16]
    DIRECTION OUTPUT ;
    USE SIGNAL ;
    ANTENNADIFFAREA 2.724000 ;
    PORT
      LAYER Metal3 ;
        RECT 136.400 59.020 136.800 59.420 ;
    END
  END Tile_X0Y1_FrameData_O[16]
  PIN Tile_X0Y1_FrameData_O[17]
    DIRECTION OUTPUT ;
    USE SIGNAL ;
    ANTENNADIFFAREA 2.724000 ;
    PORT
      LAYER Metal3 ;
        RECT 136.400 62.380 136.800 62.780 ;
    END
  END Tile_X0Y1_FrameData_O[17]
  PIN Tile_X0Y1_FrameData_O[18]
    DIRECTION OUTPUT ;
    USE SIGNAL ;
    ANTENNADIFFAREA 2.724000 ;
    PORT
      LAYER Metal3 ;
        RECT 136.400 65.740 136.800 66.140 ;
    END
  END Tile_X0Y1_FrameData_O[18]
  PIN Tile_X0Y1_FrameData_O[19]
    DIRECTION OUTPUT ;
    USE SIGNAL ;
    ANTENNADIFFAREA 2.724000 ;
    PORT
      LAYER Metal3 ;
        RECT 136.400 69.100 136.800 69.500 ;
    END
  END Tile_X0Y1_FrameData_O[19]
  PIN Tile_X0Y1_FrameData_O[1]
    DIRECTION OUTPUT ;
    USE SIGNAL ;
    ANTENNADIFFAREA 2.724000 ;
    PORT
      LAYER Metal3 ;
        RECT 136.400 8.620 136.800 9.020 ;
    END
  END Tile_X0Y1_FrameData_O[1]
  PIN Tile_X0Y1_FrameData_O[20]
    DIRECTION OUTPUT ;
    USE SIGNAL ;
    ANTENNADIFFAREA 2.724000 ;
    PORT
      LAYER Metal3 ;
        RECT 136.400 72.460 136.800 72.860 ;
    END
  END Tile_X0Y1_FrameData_O[20]
  PIN Tile_X0Y1_FrameData_O[21]
    DIRECTION OUTPUT ;
    USE SIGNAL ;
    ANTENNADIFFAREA 2.724000 ;
    PORT
      LAYER Metal3 ;
        RECT 136.400 75.820 136.800 76.220 ;
    END
  END Tile_X0Y1_FrameData_O[21]
  PIN Tile_X0Y1_FrameData_O[22]
    DIRECTION OUTPUT ;
    USE SIGNAL ;
    ANTENNADIFFAREA 2.724000 ;
    PORT
      LAYER Metal3 ;
        RECT 136.400 79.180 136.800 79.580 ;
    END
  END Tile_X0Y1_FrameData_O[22]
  PIN Tile_X0Y1_FrameData_O[23]
    DIRECTION OUTPUT ;
    USE SIGNAL ;
    ANTENNADIFFAREA 2.724000 ;
    PORT
      LAYER Metal3 ;
        RECT 136.400 82.540 136.800 82.940 ;
    END
  END Tile_X0Y1_FrameData_O[23]
  PIN Tile_X0Y1_FrameData_O[24]
    DIRECTION OUTPUT ;
    USE SIGNAL ;
    ANTENNADIFFAREA 2.724000 ;
    PORT
      LAYER Metal3 ;
        RECT 136.400 85.900 136.800 86.300 ;
    END
  END Tile_X0Y1_FrameData_O[24]
  PIN Tile_X0Y1_FrameData_O[25]
    DIRECTION OUTPUT ;
    USE SIGNAL ;
    ANTENNADIFFAREA 2.724000 ;
    PORT
      LAYER Metal3 ;
        RECT 136.400 89.260 136.800 89.660 ;
    END
  END Tile_X0Y1_FrameData_O[25]
  PIN Tile_X0Y1_FrameData_O[26]
    DIRECTION OUTPUT ;
    USE SIGNAL ;
    ANTENNADIFFAREA 2.724000 ;
    PORT
      LAYER Metal3 ;
        RECT 136.400 92.620 136.800 93.020 ;
    END
  END Tile_X0Y1_FrameData_O[26]
  PIN Tile_X0Y1_FrameData_O[27]
    DIRECTION OUTPUT ;
    USE SIGNAL ;
    ANTENNADIFFAREA 2.724000 ;
    PORT
      LAYER Metal3 ;
        RECT 136.400 95.980 136.800 96.380 ;
    END
  END Tile_X0Y1_FrameData_O[27]
  PIN Tile_X0Y1_FrameData_O[28]
    DIRECTION OUTPUT ;
    USE SIGNAL ;
    ANTENNADIFFAREA 2.724000 ;
    PORT
      LAYER Metal3 ;
        RECT 136.400 99.340 136.800 99.740 ;
    END
  END Tile_X0Y1_FrameData_O[28]
  PIN Tile_X0Y1_FrameData_O[29]
    DIRECTION OUTPUT ;
    USE SIGNAL ;
    ANTENNADIFFAREA 2.724000 ;
    PORT
      LAYER Metal3 ;
        RECT 136.400 102.700 136.800 103.100 ;
    END
  END Tile_X0Y1_FrameData_O[29]
  PIN Tile_X0Y1_FrameData_O[2]
    DIRECTION OUTPUT ;
    USE SIGNAL ;
    ANTENNADIFFAREA 2.724000 ;
    PORT
      LAYER Metal3 ;
        RECT 136.400 11.980 136.800 12.380 ;
    END
  END Tile_X0Y1_FrameData_O[2]
  PIN Tile_X0Y1_FrameData_O[30]
    DIRECTION OUTPUT ;
    USE SIGNAL ;
    ANTENNADIFFAREA 2.724000 ;
    PORT
      LAYER Metal3 ;
        RECT 136.400 106.060 136.800 106.460 ;
    END
  END Tile_X0Y1_FrameData_O[30]
  PIN Tile_X0Y1_FrameData_O[31]
    DIRECTION OUTPUT ;
    USE SIGNAL ;
    ANTENNADIFFAREA 2.724000 ;
    PORT
      LAYER Metal3 ;
        RECT 136.400 109.420 136.800 109.820 ;
    END
  END Tile_X0Y1_FrameData_O[31]
  PIN Tile_X0Y1_FrameData_O[3]
    DIRECTION OUTPUT ;
    USE SIGNAL ;
    ANTENNADIFFAREA 2.724000 ;
    PORT
      LAYER Metal3 ;
        RECT 136.400 15.340 136.800 15.740 ;
    END
  END Tile_X0Y1_FrameData_O[3]
  PIN Tile_X0Y1_FrameData_O[4]
    DIRECTION OUTPUT ;
    USE SIGNAL ;
    ANTENNADIFFAREA 2.724000 ;
    PORT
      LAYER Metal3 ;
        RECT 136.400 18.700 136.800 19.100 ;
    END
  END Tile_X0Y1_FrameData_O[4]
  PIN Tile_X0Y1_FrameData_O[5]
    DIRECTION OUTPUT ;
    USE SIGNAL ;
    ANTENNADIFFAREA 2.724000 ;
    PORT
      LAYER Metal3 ;
        RECT 136.400 22.060 136.800 22.460 ;
    END
  END Tile_X0Y1_FrameData_O[5]
  PIN Tile_X0Y1_FrameData_O[6]
    DIRECTION OUTPUT ;
    USE SIGNAL ;
    ANTENNADIFFAREA 2.724000 ;
    PORT
      LAYER Metal3 ;
        RECT 136.400 25.420 136.800 25.820 ;
    END
  END Tile_X0Y1_FrameData_O[6]
  PIN Tile_X0Y1_FrameData_O[7]
    DIRECTION OUTPUT ;
    USE SIGNAL ;
    ANTENNADIFFAREA 2.724000 ;
    PORT
      LAYER Metal3 ;
        RECT 136.400 28.780 136.800 29.180 ;
    END
  END Tile_X0Y1_FrameData_O[7]
  PIN Tile_X0Y1_FrameData_O[8]
    DIRECTION OUTPUT ;
    USE SIGNAL ;
    ANTENNADIFFAREA 2.724000 ;
    PORT
      LAYER Metal3 ;
        RECT 136.400 32.140 136.800 32.540 ;
    END
  END Tile_X0Y1_FrameData_O[8]
  PIN Tile_X0Y1_FrameData_O[9]
    DIRECTION OUTPUT ;
    USE SIGNAL ;
    ANTENNADIFFAREA 2.724000 ;
    PORT
      LAYER Metal3 ;
        RECT 136.400 35.500 136.800 35.900 ;
    END
  END Tile_X0Y1_FrameData_O[9]
  PIN Tile_X0Y1_FrameStrobe[0]
    DIRECTION INPUT ;
    USE SIGNAL ;
    ANTENNAGATEAREA 23.310299 ;
    PORT
      LAYER Metal2 ;
        RECT 112.600 0.000 113.000 0.400 ;
    END
  END Tile_X0Y1_FrameStrobe[0]
  PIN Tile_X0Y1_FrameStrobe[10]
    DIRECTION INPUT ;
    USE SIGNAL ;
    ANTENNAGATEAREA 0.180700 ;
    PORT
      LAYER Metal2 ;
        RECT 122.200 0.000 122.600 0.400 ;
    END
  END Tile_X0Y1_FrameStrobe[10]
  PIN Tile_X0Y1_FrameStrobe[11]
    DIRECTION INPUT ;
    USE SIGNAL ;
    ANTENNAGATEAREA 0.180700 ;
    PORT
      LAYER Metal2 ;
        RECT 123.160 0.000 123.560 0.400 ;
    END
  END Tile_X0Y1_FrameStrobe[11]
  PIN Tile_X0Y1_FrameStrobe[12]
    DIRECTION INPUT ;
    USE SIGNAL ;
    ANTENNAGATEAREA 0.180700 ;
    PORT
      LAYER Metal2 ;
        RECT 124.120 0.000 124.520 0.400 ;
    END
  END Tile_X0Y1_FrameStrobe[12]
  PIN Tile_X0Y1_FrameStrobe[13]
    DIRECTION INPUT ;
    USE SIGNAL ;
    ANTENNAGATEAREA 0.180700 ;
    PORT
      LAYER Metal2 ;
        RECT 125.080 0.000 125.480 0.400 ;
    END
  END Tile_X0Y1_FrameStrobe[13]
  PIN Tile_X0Y1_FrameStrobe[14]
    DIRECTION INPUT ;
    USE SIGNAL ;
    ANTENNAGATEAREA 0.180700 ;
    PORT
      LAYER Metal2 ;
        RECT 126.040 0.000 126.440 0.400 ;
    END
  END Tile_X0Y1_FrameStrobe[14]
  PIN Tile_X0Y1_FrameStrobe[15]
    DIRECTION INPUT ;
    USE SIGNAL ;
    ANTENNAGATEAREA 0.180700 ;
    PORT
      LAYER Metal2 ;
        RECT 127.000 0.000 127.400 0.400 ;
    END
  END Tile_X0Y1_FrameStrobe[15]
  PIN Tile_X0Y1_FrameStrobe[16]
    DIRECTION INPUT ;
    USE SIGNAL ;
    ANTENNAGATEAREA 0.180700 ;
    PORT
      LAYER Metal2 ;
        RECT 127.960 0.000 128.360 0.400 ;
    END
  END Tile_X0Y1_FrameStrobe[16]
  PIN Tile_X0Y1_FrameStrobe[17]
    DIRECTION INPUT ;
    USE SIGNAL ;
    ANTENNAGATEAREA 0.180700 ;
    PORT
      LAYER Metal2 ;
        RECT 128.920 0.000 129.320 0.400 ;
    END
  END Tile_X0Y1_FrameStrobe[17]
  PIN Tile_X0Y1_FrameStrobe[18]
    DIRECTION INPUT ;
    USE SIGNAL ;
    ANTENNAGATEAREA 0.180700 ;
    PORT
      LAYER Metal2 ;
        RECT 129.880 0.000 130.280 0.400 ;
    END
  END Tile_X0Y1_FrameStrobe[18]
  PIN Tile_X0Y1_FrameStrobe[19]
    DIRECTION INPUT ;
    USE SIGNAL ;
    ANTENNAGATEAREA 0.180700 ;
    PORT
      LAYER Metal2 ;
        RECT 130.840 0.000 131.240 0.400 ;
    END
  END Tile_X0Y1_FrameStrobe[19]
  PIN Tile_X0Y1_FrameStrobe[1]
    DIRECTION INPUT ;
    USE SIGNAL ;
    ANTENNAGATEAREA 23.310299 ;
    PORT
      LAYER Metal2 ;
        RECT 113.560 0.000 113.960 0.400 ;
    END
  END Tile_X0Y1_FrameStrobe[1]
  PIN Tile_X0Y1_FrameStrobe[2]
    DIRECTION INPUT ;
    USE SIGNAL ;
    ANTENNAGATEAREA 23.310299 ;
    PORT
      LAYER Metal2 ;
        RECT 114.520 0.000 114.920 0.400 ;
    END
  END Tile_X0Y1_FrameStrobe[2]
  PIN Tile_X0Y1_FrameStrobe[3]
    DIRECTION INPUT ;
    USE SIGNAL ;
    ANTENNAGATEAREA 23.310299 ;
    PORT
      LAYER Metal2 ;
        RECT 115.480 0.000 115.880 0.400 ;
    END
  END Tile_X0Y1_FrameStrobe[3]
  PIN Tile_X0Y1_FrameStrobe[4]
    DIRECTION INPUT ;
    USE SIGNAL ;
    ANTENNAGATEAREA 23.310299 ;
    PORT
      LAYER Metal2 ;
        RECT 116.440 0.000 116.840 0.400 ;
    END
  END Tile_X0Y1_FrameStrobe[4]
  PIN Tile_X0Y1_FrameStrobe[5]
    DIRECTION INPUT ;
    USE SIGNAL ;
    ANTENNAGATEAREA 23.310299 ;
    PORT
      LAYER Metal2 ;
        RECT 117.400 0.000 117.800 0.400 ;
    END
  END Tile_X0Y1_FrameStrobe[5]
  PIN Tile_X0Y1_FrameStrobe[6]
    DIRECTION INPUT ;
    USE SIGNAL ;
    ANTENNAGATEAREA 23.310299 ;
    PORT
      LAYER Metal2 ;
        RECT 118.360 0.000 118.760 0.400 ;
    END
  END Tile_X0Y1_FrameStrobe[6]
  PIN Tile_X0Y1_FrameStrobe[7]
    DIRECTION INPUT ;
    USE SIGNAL ;
    ANTENNAGATEAREA 22.587500 ;
    PORT
      LAYER Metal2 ;
        RECT 119.320 0.000 119.720 0.400 ;
    END
  END Tile_X0Y1_FrameStrobe[7]
  PIN Tile_X0Y1_FrameStrobe[8]
    DIRECTION INPUT ;
    USE SIGNAL ;
    ANTENNAGATEAREA 2.349100 ;
    PORT
      LAYER Metal2 ;
        RECT 120.280 0.000 120.680 0.400 ;
    END
  END Tile_X0Y1_FrameStrobe[8]
  PIN Tile_X0Y1_FrameStrobe[9]
    DIRECTION INPUT ;
    USE SIGNAL ;
    ANTENNAGATEAREA 0.180700 ;
    PORT
      LAYER Metal2 ;
        RECT 121.240 0.000 121.640 0.400 ;
    END
  END Tile_X0Y1_FrameStrobe[9]
  PIN Tile_X0Y1_N1END[0]
    DIRECTION INPUT ;
    USE SIGNAL ;
    ANTENNAGATEAREA 1.279200 ;
    PORT
      LAYER Metal2 ;
        RECT 2.200 0.000 2.600 0.400 ;
    END
  END Tile_X0Y1_N1END[0]
  PIN Tile_X0Y1_N1END[1]
    DIRECTION INPUT ;
    USE SIGNAL ;
    ANTENNAGATEAREA 1.279200 ;
    PORT
      LAYER Metal2 ;
        RECT 3.160 0.000 3.560 0.400 ;
    END
  END Tile_X0Y1_N1END[1]
  PIN Tile_X0Y1_N1END[2]
    DIRECTION INPUT ;
    USE SIGNAL ;
    ANTENNAGATEAREA 1.279200 ;
    PORT
      LAYER Metal2 ;
        RECT 4.120 0.000 4.520 0.400 ;
    END
  END Tile_X0Y1_N1END[2]
  PIN Tile_X0Y1_N1END[3]
    DIRECTION INPUT ;
    USE SIGNAL ;
    ANTENNAGATEAREA 1.279200 ;
    PORT
      LAYER Metal2 ;
        RECT 5.080 0.000 5.480 0.400 ;
    END
  END Tile_X0Y1_N1END[3]
  PIN Tile_X0Y1_N2END[0]
    DIRECTION INPUT ;
    USE SIGNAL ;
    ANTENNAGATEAREA 0.213200 ;
    PORT
      LAYER Metal2 ;
        RECT 20.440 0.000 20.840 0.400 ;
    END
  END Tile_X0Y1_N2END[0]
  PIN Tile_X0Y1_N2END[1]
    DIRECTION INPUT ;
    USE SIGNAL ;
    ANTENNAGATEAREA 0.213200 ;
    PORT
      LAYER Metal2 ;
        RECT 21.400 0.000 21.800 0.400 ;
    END
  END Tile_X0Y1_N2END[1]
  PIN Tile_X0Y1_N2END[2]
    DIRECTION INPUT ;
    USE SIGNAL ;
    ANTENNAGATEAREA 0.213200 ;
    PORT
      LAYER Metal2 ;
        RECT 22.360 0.000 22.760 0.400 ;
    END
  END Tile_X0Y1_N2END[2]
  PIN Tile_X0Y1_N2END[3]
    DIRECTION INPUT ;
    USE SIGNAL ;
    ANTENNAGATEAREA 0.213200 ;
    PORT
      LAYER Metal2 ;
        RECT 23.320 0.000 23.720 0.400 ;
    END
  END Tile_X0Y1_N2END[3]
  PIN Tile_X0Y1_N2END[4]
    DIRECTION INPUT ;
    USE SIGNAL ;
    ANTENNAGATEAREA 0.213200 ;
    PORT
      LAYER Metal2 ;
        RECT 24.280 0.000 24.680 0.400 ;
    END
  END Tile_X0Y1_N2END[4]
  PIN Tile_X0Y1_N2END[5]
    DIRECTION INPUT ;
    USE SIGNAL ;
    ANTENNAGATEAREA 0.213200 ;
    PORT
      LAYER Metal2 ;
        RECT 25.240 0.000 25.640 0.400 ;
    END
  END Tile_X0Y1_N2END[5]
  PIN Tile_X0Y1_N2END[6]
    DIRECTION INPUT ;
    USE SIGNAL ;
    ANTENNAGATEAREA 0.213200 ;
    PORT
      LAYER Metal2 ;
        RECT 26.200 0.000 26.600 0.400 ;
    END
  END Tile_X0Y1_N2END[6]
  PIN Tile_X0Y1_N2END[7]
    DIRECTION INPUT ;
    USE SIGNAL ;
    ANTENNAGATEAREA 0.213200 ;
    PORT
      LAYER Metal2 ;
        RECT 27.160 0.000 27.560 0.400 ;
    END
  END Tile_X0Y1_N2END[7]
  PIN Tile_X0Y1_N2MID[0]
    DIRECTION INPUT ;
    USE SIGNAL ;
    ANTENNAGATEAREA 0.426400 ;
    ANTENNADIFFAREA 10.077000 ;
    PORT
      LAYER Metal2 ;
        RECT 8.920 0.000 9.320 0.400 ;
    END
  END Tile_X0Y1_N2MID[0]
  PIN Tile_X0Y1_N2MID[1]
    DIRECTION INPUT ;
    USE SIGNAL ;
    ANTENNAGATEAREA 0.426400 ;
    ANTENNADIFFAREA 10.077000 ;
    PORT
      LAYER Metal2 ;
        RECT 9.880 0.000 10.280 0.400 ;
    END
  END Tile_X0Y1_N2MID[1]
  PIN Tile_X0Y1_N2MID[2]
    DIRECTION INPUT ;
    USE SIGNAL ;
    ANTENNAGATEAREA 0.426400 ;
    ANTENNADIFFAREA 8.061600 ;
    PORT
      LAYER Metal2 ;
        RECT 10.840 0.000 11.240 0.400 ;
    END
  END Tile_X0Y1_N2MID[2]
  PIN Tile_X0Y1_N2MID[3]
    DIRECTION INPUT ;
    USE SIGNAL ;
    ANTENNAGATEAREA 0.426400 ;
    ANTENNADIFFAREA 10.077000 ;
    PORT
      LAYER Metal2 ;
        RECT 11.800 0.000 12.200 0.400 ;
    END
  END Tile_X0Y1_N2MID[3]
  PIN Tile_X0Y1_N2MID[4]
    DIRECTION INPUT ;
    USE SIGNAL ;
    ANTENNAGATEAREA 0.426400 ;
    PORT
      LAYER Metal2 ;
        RECT 12.760 0.000 13.160 0.400 ;
    END
  END Tile_X0Y1_N2MID[4]
  PIN Tile_X0Y1_N2MID[5]
    DIRECTION INPUT ;
    USE SIGNAL ;
    ANTENNAGATEAREA 0.426400 ;
    ANTENNADIFFAREA 10.077000 ;
    PORT
      LAYER Metal2 ;
        RECT 13.720 0.000 14.120 0.400 ;
    END
  END Tile_X0Y1_N2MID[5]
  PIN Tile_X0Y1_N2MID[6]
    DIRECTION INPUT ;
    USE SIGNAL ;
    ANTENNAGATEAREA 0.426400 ;
    ANTENNADIFFAREA 10.077000 ;
    PORT
      LAYER Metal2 ;
        RECT 14.680 0.000 15.080 0.400 ;
    END
  END Tile_X0Y1_N2MID[6]
  PIN Tile_X0Y1_N2MID[7]
    DIRECTION INPUT ;
    USE SIGNAL ;
    ANTENNAGATEAREA 0.426400 ;
    PORT
      LAYER Metal2 ;
        RECT 15.640 0.000 16.040 0.400 ;
    END
  END Tile_X0Y1_N2MID[7]
  PIN Tile_X0Y1_N4END[0]
    DIRECTION INPUT ;
    USE SIGNAL ;
    ANTENNAGATEAREA 1.066000 ;
    PORT
      LAYER Metal2 ;
        RECT 33.880 0.000 34.280 0.400 ;
    END
  END Tile_X0Y1_N4END[0]
  PIN Tile_X0Y1_N4END[10]
    DIRECTION INPUT ;
    USE SIGNAL ;
    ANTENNAGATEAREA 0.180700 ;
    PORT
      LAYER Metal2 ;
        RECT 43.480 0.000 43.880 0.400 ;
    END
  END Tile_X0Y1_N4END[10]
  PIN Tile_X0Y1_N4END[11]
    DIRECTION INPUT ;
    USE SIGNAL ;
    ANTENNAGATEAREA 0.180700 ;
    PORT
      LAYER Metal2 ;
        RECT 44.440 0.000 44.840 0.400 ;
    END
  END Tile_X0Y1_N4END[11]
  PIN Tile_X0Y1_N4END[12]
    DIRECTION INPUT ;
    USE SIGNAL ;
    ANTENNAGATEAREA 0.180700 ;
    PORT
      LAYER Metal2 ;
        RECT 45.400 0.000 45.800 0.400 ;
    END
  END Tile_X0Y1_N4END[12]
  PIN Tile_X0Y1_N4END[13]
    DIRECTION INPUT ;
    USE SIGNAL ;
    ANTENNAGATEAREA 0.180700 ;
    PORT
      LAYER Metal2 ;
        RECT 46.360 0.000 46.760 0.400 ;
    END
  END Tile_X0Y1_N4END[13]
  PIN Tile_X0Y1_N4END[14]
    DIRECTION INPUT ;
    USE SIGNAL ;
    ANTENNAGATEAREA 0.180700 ;
    PORT
      LAYER Metal2 ;
        RECT 47.320 0.000 47.720 0.400 ;
    END
  END Tile_X0Y1_N4END[14]
  PIN Tile_X0Y1_N4END[15]
    DIRECTION INPUT ;
    USE SIGNAL ;
    ANTENNAGATEAREA 0.180700 ;
    PORT
      LAYER Metal2 ;
        RECT 48.280 0.000 48.680 0.400 ;
    END
  END Tile_X0Y1_N4END[15]
  PIN Tile_X0Y1_N4END[1]
    DIRECTION INPUT ;
    USE SIGNAL ;
    ANTENNAGATEAREA 1.066000 ;
    PORT
      LAYER Metal2 ;
        RECT 34.840 0.000 35.240 0.400 ;
    END
  END Tile_X0Y1_N4END[1]
  PIN Tile_X0Y1_N4END[2]
    DIRECTION INPUT ;
    USE SIGNAL ;
    ANTENNAGATEAREA 1.066000 ;
    PORT
      LAYER Metal2 ;
        RECT 35.800 0.000 36.200 0.400 ;
    END
  END Tile_X0Y1_N4END[2]
  PIN Tile_X0Y1_N4END[3]
    DIRECTION INPUT ;
    USE SIGNAL ;
    ANTENNAGATEAREA 1.066000 ;
    PORT
      LAYER Metal2 ;
        RECT 36.760 0.000 37.160 0.400 ;
    END
  END Tile_X0Y1_N4END[3]
  PIN Tile_X0Y1_N4END[4]
    DIRECTION INPUT ;
    USE SIGNAL ;
    ANTENNAGATEAREA 1.066000 ;
    ANTENNADIFFAREA 50.384998 ;
    PORT
      LAYER Metal2 ;
        RECT 37.720 0.000 38.120 0.400 ;
    END
  END Tile_X0Y1_N4END[4]
  PIN Tile_X0Y1_N4END[5]
    DIRECTION INPUT ;
    USE SIGNAL ;
    ANTENNAGATEAREA 1.066000 ;
    PORT
      LAYER Metal2 ;
        RECT 38.680 0.000 39.080 0.400 ;
    END
  END Tile_X0Y1_N4END[5]
  PIN Tile_X0Y1_N4END[6]
    DIRECTION INPUT ;
    USE SIGNAL ;
    ANTENNAGATEAREA 1.066000 ;
    PORT
      LAYER Metal2 ;
        RECT 39.640 0.000 40.040 0.400 ;
    END
  END Tile_X0Y1_N4END[6]
  PIN Tile_X0Y1_N4END[7]
    DIRECTION INPUT ;
    USE SIGNAL ;
    ANTENNAGATEAREA 1.066000 ;
    PORT
      LAYER Metal2 ;
        RECT 40.600 0.000 41.000 0.400 ;
    END
  END Tile_X0Y1_N4END[7]
  PIN Tile_X0Y1_N4END[8]
    DIRECTION INPUT ;
    USE SIGNAL ;
    ANTENNAGATEAREA 0.180700 ;
    PORT
      LAYER Metal2 ;
        RECT 41.560 0.000 41.960 0.400 ;
    END
  END Tile_X0Y1_N4END[8]
  PIN Tile_X0Y1_N4END[9]
    DIRECTION INPUT ;
    USE SIGNAL ;
    ANTENNAGATEAREA 0.180700 ;
    PORT
      LAYER Metal2 ;
        RECT 42.520 0.000 42.920 0.400 ;
    END
  END Tile_X0Y1_N4END[9]
  PIN Tile_X0Y1_S1BEG[0]
    DIRECTION OUTPUT ;
    USE SIGNAL ;
    ANTENNADIFFAREA 2.724000 ;
    PORT
      LAYER Metal2 ;
        RECT 55.000 0.000 55.400 0.400 ;
    END
  END Tile_X0Y1_S1BEG[0]
  PIN Tile_X0Y1_S1BEG[1]
    DIRECTION OUTPUT ;
    USE SIGNAL ;
    ANTENNADIFFAREA 2.724000 ;
    PORT
      LAYER Metal2 ;
        RECT 55.960 0.000 56.360 0.400 ;
    END
  END Tile_X0Y1_S1BEG[1]
  PIN Tile_X0Y1_S1BEG[2]
    DIRECTION OUTPUT ;
    USE SIGNAL ;
    ANTENNADIFFAREA 2.724000 ;
    PORT
      LAYER Metal2 ;
        RECT 56.920 0.000 57.320 0.400 ;
    END
  END Tile_X0Y1_S1BEG[2]
  PIN Tile_X0Y1_S1BEG[3]
    DIRECTION OUTPUT ;
    USE SIGNAL ;
    ANTENNADIFFAREA 2.724000 ;
    PORT
      LAYER Metal2 ;
        RECT 57.880 0.000 58.280 0.400 ;
    END
  END Tile_X0Y1_S1BEG[3]
  PIN Tile_X0Y1_S2BEG[0]
    DIRECTION OUTPUT ;
    USE SIGNAL ;
    ANTENNADIFFAREA 2.724000 ;
    PORT
      LAYER Metal2 ;
        RECT 61.720 0.000 62.120 0.400 ;
    END
  END Tile_X0Y1_S2BEG[0]
  PIN Tile_X0Y1_S2BEG[1]
    DIRECTION OUTPUT ;
    USE SIGNAL ;
    ANTENNADIFFAREA 2.724000 ;
    PORT
      LAYER Metal2 ;
        RECT 62.680 0.000 63.080 0.400 ;
    END
  END Tile_X0Y1_S2BEG[1]
  PIN Tile_X0Y1_S2BEG[2]
    DIRECTION OUTPUT ;
    USE SIGNAL ;
    ANTENNADIFFAREA 2.724000 ;
    PORT
      LAYER Metal2 ;
        RECT 63.640 0.000 64.040 0.400 ;
    END
  END Tile_X0Y1_S2BEG[2]
  PIN Tile_X0Y1_S2BEG[3]
    DIRECTION OUTPUT ;
    USE SIGNAL ;
    ANTENNADIFFAREA 2.724000 ;
    PORT
      LAYER Metal2 ;
        RECT 64.600 0.000 65.000 0.400 ;
    END
  END Tile_X0Y1_S2BEG[3]
  PIN Tile_X0Y1_S2BEG[4]
    DIRECTION OUTPUT ;
    USE SIGNAL ;
    ANTENNADIFFAREA 2.724000 ;
    PORT
      LAYER Metal2 ;
        RECT 65.560 0.000 65.960 0.400 ;
    END
  END Tile_X0Y1_S2BEG[4]
  PIN Tile_X0Y1_S2BEG[5]
    DIRECTION OUTPUT ;
    USE SIGNAL ;
    ANTENNADIFFAREA 2.724000 ;
    PORT
      LAYER Metal2 ;
        RECT 66.520 0.000 66.920 0.400 ;
    END
  END Tile_X0Y1_S2BEG[5]
  PIN Tile_X0Y1_S2BEG[6]
    DIRECTION OUTPUT ;
    USE SIGNAL ;
    ANTENNADIFFAREA 2.724000 ;
    PORT
      LAYER Metal2 ;
        RECT 67.480 0.000 67.880 0.400 ;
    END
  END Tile_X0Y1_S2BEG[6]
  PIN Tile_X0Y1_S2BEG[7]
    DIRECTION OUTPUT ;
    USE SIGNAL ;
    ANTENNADIFFAREA 2.724000 ;
    PORT
      LAYER Metal2 ;
        RECT 68.440 0.000 68.840 0.400 ;
    END
  END Tile_X0Y1_S2BEG[7]
  PIN Tile_X0Y1_S2BEGb[0]
    DIRECTION OUTPUT ;
    USE SIGNAL ;
    ANTENNADIFFAREA 2.724000 ;
    PORT
      LAYER Metal2 ;
        RECT 73.240 0.000 73.640 0.400 ;
    END
  END Tile_X0Y1_S2BEGb[0]
  PIN Tile_X0Y1_S2BEGb[1]
    DIRECTION OUTPUT ;
    USE SIGNAL ;
    ANTENNADIFFAREA 2.724000 ;
    PORT
      LAYER Metal2 ;
        RECT 74.200 0.000 74.600 0.400 ;
    END
  END Tile_X0Y1_S2BEGb[1]
  PIN Tile_X0Y1_S2BEGb[2]
    DIRECTION OUTPUT ;
    USE SIGNAL ;
    ANTENNADIFFAREA 2.724000 ;
    PORT
      LAYER Metal2 ;
        RECT 75.160 0.000 75.560 0.400 ;
    END
  END Tile_X0Y1_S2BEGb[2]
  PIN Tile_X0Y1_S2BEGb[3]
    DIRECTION OUTPUT ;
    USE SIGNAL ;
    ANTENNADIFFAREA 2.724000 ;
    PORT
      LAYER Metal2 ;
        RECT 76.120 0.000 76.520 0.400 ;
    END
  END Tile_X0Y1_S2BEGb[3]
  PIN Tile_X0Y1_S2BEGb[4]
    DIRECTION OUTPUT ;
    USE SIGNAL ;
    ANTENNADIFFAREA 2.724000 ;
    PORT
      LAYER Metal2 ;
        RECT 77.080 0.000 77.480 0.400 ;
    END
  END Tile_X0Y1_S2BEGb[4]
  PIN Tile_X0Y1_S2BEGb[5]
    DIRECTION OUTPUT ;
    USE SIGNAL ;
    ANTENNADIFFAREA 2.724000 ;
    PORT
      LAYER Metal2 ;
        RECT 78.040 0.000 78.440 0.400 ;
    END
  END Tile_X0Y1_S2BEGb[5]
  PIN Tile_X0Y1_S2BEGb[6]
    DIRECTION OUTPUT ;
    USE SIGNAL ;
    ANTENNADIFFAREA 2.724000 ;
    PORT
      LAYER Metal2 ;
        RECT 79.000 0.000 79.400 0.400 ;
    END
  END Tile_X0Y1_S2BEGb[6]
  PIN Tile_X0Y1_S2BEGb[7]
    DIRECTION OUTPUT ;
    USE SIGNAL ;
    ANTENNADIFFAREA 2.724000 ;
    PORT
      LAYER Metal2 ;
        RECT 79.960 0.000 80.360 0.400 ;
    END
  END Tile_X0Y1_S2BEGb[7]
  PIN Tile_X0Y1_S4BEG[0]
    DIRECTION OUTPUT ;
    USE SIGNAL ;
    ANTENNADIFFAREA 2.724000 ;
    PORT
      LAYER Metal2 ;
        RECT 87.640 0.000 88.040 0.400 ;
    END
  END Tile_X0Y1_S4BEG[0]
  PIN Tile_X0Y1_S4BEG[10]
    DIRECTION OUTPUT ;
    USE SIGNAL ;
    ANTENNADIFFAREA 2.724000 ;
    PORT
      LAYER Metal2 ;
        RECT 97.240 0.000 97.640 0.400 ;
    END
  END Tile_X0Y1_S4BEG[10]
  PIN Tile_X0Y1_S4BEG[11]
    DIRECTION OUTPUT ;
    USE SIGNAL ;
    ANTENNADIFFAREA 2.724000 ;
    PORT
      LAYER Metal2 ;
        RECT 98.200 0.000 98.600 0.400 ;
    END
  END Tile_X0Y1_S4BEG[11]
  PIN Tile_X0Y1_S4BEG[12]
    DIRECTION OUTPUT ;
    USE SIGNAL ;
    ANTENNADIFFAREA 2.724000 ;
    PORT
      LAYER Metal2 ;
        RECT 99.160 0.000 99.560 0.400 ;
    END
  END Tile_X0Y1_S4BEG[12]
  PIN Tile_X0Y1_S4BEG[13]
    DIRECTION OUTPUT ;
    USE SIGNAL ;
    ANTENNADIFFAREA 2.724000 ;
    PORT
      LAYER Metal2 ;
        RECT 100.120 0.000 100.520 0.400 ;
    END
  END Tile_X0Y1_S4BEG[13]
  PIN Tile_X0Y1_S4BEG[14]
    DIRECTION OUTPUT ;
    USE SIGNAL ;
    ANTENNADIFFAREA 2.724000 ;
    PORT
      LAYER Metal2 ;
        RECT 101.080 0.000 101.480 0.400 ;
    END
  END Tile_X0Y1_S4BEG[14]
  PIN Tile_X0Y1_S4BEG[15]
    DIRECTION OUTPUT ;
    USE SIGNAL ;
    ANTENNADIFFAREA 2.724000 ;
    PORT
      LAYER Metal2 ;
        RECT 102.040 0.000 102.440 0.400 ;
    END
  END Tile_X0Y1_S4BEG[15]
  PIN Tile_X0Y1_S4BEG[1]
    DIRECTION OUTPUT ;
    USE SIGNAL ;
    ANTENNADIFFAREA 2.724000 ;
    PORT
      LAYER Metal2 ;
        RECT 88.600 0.000 89.000 0.400 ;
    END
  END Tile_X0Y1_S4BEG[1]
  PIN Tile_X0Y1_S4BEG[2]
    DIRECTION OUTPUT ;
    USE SIGNAL ;
    ANTENNADIFFAREA 2.724000 ;
    PORT
      LAYER Metal2 ;
        RECT 89.560 0.000 89.960 0.400 ;
    END
  END Tile_X0Y1_S4BEG[2]
  PIN Tile_X0Y1_S4BEG[3]
    DIRECTION OUTPUT ;
    USE SIGNAL ;
    ANTENNADIFFAREA 2.724000 ;
    PORT
      LAYER Metal2 ;
        RECT 90.520 0.000 90.920 0.400 ;
    END
  END Tile_X0Y1_S4BEG[3]
  PIN Tile_X0Y1_S4BEG[4]
    DIRECTION OUTPUT ;
    USE SIGNAL ;
    ANTENNADIFFAREA 2.724000 ;
    PORT
      LAYER Metal2 ;
        RECT 91.480 0.000 91.880 0.400 ;
    END
  END Tile_X0Y1_S4BEG[4]
  PIN Tile_X0Y1_S4BEG[5]
    DIRECTION OUTPUT ;
    USE SIGNAL ;
    ANTENNADIFFAREA 2.724000 ;
    PORT
      LAYER Metal2 ;
        RECT 92.440 0.000 92.840 0.400 ;
    END
  END Tile_X0Y1_S4BEG[5]
  PIN Tile_X0Y1_S4BEG[6]
    DIRECTION OUTPUT ;
    USE SIGNAL ;
    ANTENNADIFFAREA 2.724000 ;
    PORT
      LAYER Metal2 ;
        RECT 93.400 0.000 93.800 0.400 ;
    END
  END Tile_X0Y1_S4BEG[6]
  PIN Tile_X0Y1_S4BEG[7]
    DIRECTION OUTPUT ;
    USE SIGNAL ;
    ANTENNADIFFAREA 2.724000 ;
    PORT
      LAYER Metal2 ;
        RECT 94.360 0.000 94.760 0.400 ;
    END
  END Tile_X0Y1_S4BEG[7]
  PIN Tile_X0Y1_S4BEG[8]
    DIRECTION OUTPUT ;
    USE SIGNAL ;
    ANTENNADIFFAREA 2.724000 ;
    PORT
      LAYER Metal2 ;
        RECT 95.320 0.000 95.720 0.400 ;
    END
  END Tile_X0Y1_S4BEG[8]
  PIN Tile_X0Y1_S4BEG[9]
    DIRECTION OUTPUT ;
    USE SIGNAL ;
    ANTENNADIFFAREA 2.724000 ;
    PORT
      LAYER Metal2 ;
        RECT 96.280 0.000 96.680 0.400 ;
    END
  END Tile_X0Y1_S4BEG[9]
  PIN Tile_X0Y1_UserCLK
    DIRECTION INPUT ;
    USE SIGNAL ;
    ANTENNAGATEAREA 11.726000 ;
    PORT
      LAYER Metal3 ;
        RECT 0.000 203.500 0.400 203.900 ;
    END
  END Tile_X0Y1_UserCLK
  PIN Tile_X0Y1_UserCLKo
    DIRECTION OUTPUT ;
    USE SIGNAL ;
    ANTENNADIFFAREA 2.724000 ;
    PORT
      LAYER Metal3 ;
        RECT 136.400 1.900 136.800 2.300 ;
    END
  END Tile_X0Y1_UserCLKo
  PIN Tile_X0Y1_W1BEG[0]
    DIRECTION OUTPUT ;
    USE SIGNAL ;
    ANTENNADIFFAREA 2.724000 ;
    PORT
      LAYER Metal3 ;
        RECT 0.000 102.700 0.400 103.100 ;
    END
  END Tile_X0Y1_W1BEG[0]
  PIN Tile_X0Y1_W1BEG[1]
    DIRECTION OUTPUT ;
    USE SIGNAL ;
    ANTENNADIFFAREA 2.724000 ;
    PORT
      LAYER Metal3 ;
        RECT 0.000 104.380 0.400 104.780 ;
    END
  END Tile_X0Y1_W1BEG[1]
  PIN Tile_X0Y1_W1BEG[2]
    DIRECTION OUTPUT ;
    USE SIGNAL ;
    ANTENNADIFFAREA 2.724000 ;
    PORT
      LAYER Metal3 ;
        RECT 0.000 106.060 0.400 106.460 ;
    END
  END Tile_X0Y1_W1BEG[2]
  PIN Tile_X0Y1_W1BEG[3]
    DIRECTION OUTPUT ;
    USE SIGNAL ;
    ANTENNADIFFAREA 2.724000 ;
    PORT
      LAYER Metal3 ;
        RECT 0.000 107.740 0.400 108.140 ;
    END
  END Tile_X0Y1_W1BEG[3]
  PIN Tile_X0Y1_W2BEG[0]
    DIRECTION OUTPUT ;
    USE SIGNAL ;
    ANTENNADIFFAREA 2.724000 ;
    PORT
      LAYER Metal3 ;
        RECT 0.000 111.940 0.400 112.340 ;
    END
  END Tile_X0Y1_W2BEG[0]
  PIN Tile_X0Y1_W2BEG[1]
    DIRECTION OUTPUT ;
    USE SIGNAL ;
    ANTENNADIFFAREA 2.724000 ;
    PORT
      LAYER Metal3 ;
        RECT 0.000 113.620 0.400 114.020 ;
    END
  END Tile_X0Y1_W2BEG[1]
  PIN Tile_X0Y1_W2BEG[2]
    DIRECTION OUTPUT ;
    USE SIGNAL ;
    ANTENNADIFFAREA 2.724000 ;
    PORT
      LAYER Metal3 ;
        RECT 0.000 115.300 0.400 115.700 ;
    END
  END Tile_X0Y1_W2BEG[2]
  PIN Tile_X0Y1_W2BEG[3]
    DIRECTION OUTPUT ;
    USE SIGNAL ;
    ANTENNADIFFAREA 2.724000 ;
    PORT
      LAYER Metal3 ;
        RECT 0.000 116.980 0.400 117.380 ;
    END
  END Tile_X0Y1_W2BEG[3]
  PIN Tile_X0Y1_W2BEG[4]
    DIRECTION OUTPUT ;
    USE SIGNAL ;
    ANTENNADIFFAREA 2.724000 ;
    PORT
      LAYER Metal3 ;
        RECT 0.000 118.660 0.400 119.060 ;
    END
  END Tile_X0Y1_W2BEG[4]
  PIN Tile_X0Y1_W2BEG[5]
    DIRECTION OUTPUT ;
    USE SIGNAL ;
    ANTENNADIFFAREA 2.724000 ;
    PORT
      LAYER Metal3 ;
        RECT 0.000 120.340 0.400 120.740 ;
    END
  END Tile_X0Y1_W2BEG[5]
  PIN Tile_X0Y1_W2BEG[6]
    DIRECTION OUTPUT ;
    USE SIGNAL ;
    ANTENNADIFFAREA 2.724000 ;
    PORT
      LAYER Metal3 ;
        RECT 0.000 122.020 0.400 122.420 ;
    END
  END Tile_X0Y1_W2BEG[6]
  PIN Tile_X0Y1_W2BEG[7]
    DIRECTION OUTPUT ;
    USE SIGNAL ;
    ANTENNADIFFAREA 2.724000 ;
    PORT
      LAYER Metal3 ;
        RECT 0.000 123.700 0.400 124.100 ;
    END
  END Tile_X0Y1_W2BEG[7]
  PIN Tile_X0Y1_W2BEGb[0]
    DIRECTION OUTPUT ;
    USE SIGNAL ;
    ANTENNADIFFAREA 2.724000 ;
    PORT
      LAYER Metal3 ;
        RECT 0.000 128.740 0.400 129.140 ;
    END
  END Tile_X0Y1_W2BEGb[0]
  PIN Tile_X0Y1_W2BEGb[1]
    DIRECTION OUTPUT ;
    USE SIGNAL ;
    ANTENNADIFFAREA 2.724000 ;
    PORT
      LAYER Metal3 ;
        RECT 0.000 130.420 0.400 130.820 ;
    END
  END Tile_X0Y1_W2BEGb[1]
  PIN Tile_X0Y1_W2BEGb[2]
    DIRECTION OUTPUT ;
    USE SIGNAL ;
    ANTENNADIFFAREA 2.724000 ;
    PORT
      LAYER Metal3 ;
        RECT 0.000 132.100 0.400 132.500 ;
    END
  END Tile_X0Y1_W2BEGb[2]
  PIN Tile_X0Y1_W2BEGb[3]
    DIRECTION OUTPUT ;
    USE SIGNAL ;
    ANTENNADIFFAREA 2.724000 ;
    PORT
      LAYER Metal3 ;
        RECT 0.000 133.780 0.400 134.180 ;
    END
  END Tile_X0Y1_W2BEGb[3]
  PIN Tile_X0Y1_W2BEGb[4]
    DIRECTION OUTPUT ;
    USE SIGNAL ;
    ANTENNADIFFAREA 2.724000 ;
    PORT
      LAYER Metal3 ;
        RECT 0.000 135.460 0.400 135.860 ;
    END
  END Tile_X0Y1_W2BEGb[4]
  PIN Tile_X0Y1_W2BEGb[5]
    DIRECTION OUTPUT ;
    USE SIGNAL ;
    ANTENNADIFFAREA 2.724000 ;
    PORT
      LAYER Metal3 ;
        RECT 0.000 137.140 0.400 137.540 ;
    END
  END Tile_X0Y1_W2BEGb[5]
  PIN Tile_X0Y1_W2BEGb[6]
    DIRECTION OUTPUT ;
    USE SIGNAL ;
    ANTENNADIFFAREA 2.724000 ;
    PORT
      LAYER Metal3 ;
        RECT 0.000 138.820 0.400 139.220 ;
    END
  END Tile_X0Y1_W2BEGb[6]
  PIN Tile_X0Y1_W2BEGb[7]
    DIRECTION OUTPUT ;
    USE SIGNAL ;
    ANTENNADIFFAREA 2.724000 ;
    PORT
      LAYER Metal3 ;
        RECT 0.000 140.500 0.400 140.900 ;
    END
  END Tile_X0Y1_W2BEGb[7]
  PIN Tile_X0Y1_W6BEG[0]
    DIRECTION OUTPUT ;
    USE SIGNAL ;
    ANTENNADIFFAREA 2.724000 ;
    PORT
      LAYER Metal3 ;
        RECT 0.000 179.980 0.400 180.380 ;
    END
  END Tile_X0Y1_W6BEG[0]
  PIN Tile_X0Y1_W6BEG[10]
    DIRECTION OUTPUT ;
    USE SIGNAL ;
    ANTENNADIFFAREA 2.724000 ;
    PORT
      LAYER Metal3 ;
        RECT 0.000 196.780 0.400 197.180 ;
    END
  END Tile_X0Y1_W6BEG[10]
  PIN Tile_X0Y1_W6BEG[11]
    DIRECTION OUTPUT ;
    USE SIGNAL ;
    ANTENNADIFFAREA 2.724000 ;
    PORT
      LAYER Metal3 ;
        RECT 0.000 198.460 0.400 198.860 ;
    END
  END Tile_X0Y1_W6BEG[11]
  PIN Tile_X0Y1_W6BEG[1]
    DIRECTION OUTPUT ;
    USE SIGNAL ;
    ANTENNADIFFAREA 2.724000 ;
    PORT
      LAYER Metal3 ;
        RECT 0.000 181.660 0.400 182.060 ;
    END
  END Tile_X0Y1_W6BEG[1]
  PIN Tile_X0Y1_W6BEG[2]
    DIRECTION OUTPUT ;
    USE SIGNAL ;
    ANTENNADIFFAREA 2.724000 ;
    PORT
      LAYER Metal3 ;
        RECT 0.000 183.340 0.400 183.740 ;
    END
  END Tile_X0Y1_W6BEG[2]
  PIN Tile_X0Y1_W6BEG[3]
    DIRECTION OUTPUT ;
    USE SIGNAL ;
    ANTENNADIFFAREA 2.724000 ;
    PORT
      LAYER Metal3 ;
        RECT 0.000 185.020 0.400 185.420 ;
    END
  END Tile_X0Y1_W6BEG[3]
  PIN Tile_X0Y1_W6BEG[4]
    DIRECTION OUTPUT ;
    USE SIGNAL ;
    ANTENNADIFFAREA 2.724000 ;
    PORT
      LAYER Metal3 ;
        RECT 0.000 186.700 0.400 187.100 ;
    END
  END Tile_X0Y1_W6BEG[4]
  PIN Tile_X0Y1_W6BEG[5]
    DIRECTION OUTPUT ;
    USE SIGNAL ;
    ANTENNADIFFAREA 2.724000 ;
    PORT
      LAYER Metal3 ;
        RECT 0.000 188.380 0.400 188.780 ;
    END
  END Tile_X0Y1_W6BEG[5]
  PIN Tile_X0Y1_W6BEG[6]
    DIRECTION OUTPUT ;
    USE SIGNAL ;
    ANTENNADIFFAREA 2.724000 ;
    PORT
      LAYER Metal3 ;
        RECT 0.000 190.060 0.400 190.460 ;
    END
  END Tile_X0Y1_W6BEG[6]
  PIN Tile_X0Y1_W6BEG[7]
    DIRECTION OUTPUT ;
    USE SIGNAL ;
    ANTENNADIFFAREA 2.724000 ;
    PORT
      LAYER Metal3 ;
        RECT 0.000 191.740 0.400 192.140 ;
    END
  END Tile_X0Y1_W6BEG[7]
  PIN Tile_X0Y1_W6BEG[8]
    DIRECTION OUTPUT ;
    USE SIGNAL ;
    ANTENNADIFFAREA 2.724000 ;
    PORT
      LAYER Metal3 ;
        RECT 0.000 193.420 0.400 193.820 ;
    END
  END Tile_X0Y1_W6BEG[8]
  PIN Tile_X0Y1_W6BEG[9]
    DIRECTION OUTPUT ;
    USE SIGNAL ;
    ANTENNADIFFAREA 2.724000 ;
    PORT
      LAYER Metal3 ;
        RECT 0.000 195.100 0.400 195.500 ;
    END
  END Tile_X0Y1_W6BEG[9]
  PIN Tile_X0Y1_WW4BEG[0]
    DIRECTION OUTPUT ;
    USE SIGNAL ;
    ANTENNADIFFAREA 2.724000 ;
    PORT
      LAYER Metal3 ;
        RECT 0.000 147.220 0.400 147.620 ;
    END
  END Tile_X0Y1_WW4BEG[0]
  PIN Tile_X0Y1_WW4BEG[10]
    DIRECTION OUTPUT ;
    USE SIGNAL ;
    ANTENNADIFFAREA 2.724000 ;
    PORT
      LAYER Metal3 ;
        RECT 0.000 164.020 0.400 164.420 ;
    END
  END Tile_X0Y1_WW4BEG[10]
  PIN Tile_X0Y1_WW4BEG[11]
    DIRECTION OUTPUT ;
    USE SIGNAL ;
    ANTENNADIFFAREA 2.724000 ;
    PORT
      LAYER Metal3 ;
        RECT 0.000 165.700 0.400 166.100 ;
    END
  END Tile_X0Y1_WW4BEG[11]
  PIN Tile_X0Y1_WW4BEG[12]
    DIRECTION OUTPUT ;
    USE SIGNAL ;
    ANTENNADIFFAREA 2.724000 ;
    PORT
      LAYER Metal3 ;
        RECT 0.000 167.380 0.400 167.780 ;
    END
  END Tile_X0Y1_WW4BEG[12]
  PIN Tile_X0Y1_WW4BEG[13]
    DIRECTION OUTPUT ;
    USE SIGNAL ;
    ANTENNADIFFAREA 2.724000 ;
    PORT
      LAYER Metal3 ;
        RECT 0.000 169.060 0.400 169.460 ;
    END
  END Tile_X0Y1_WW4BEG[13]
  PIN Tile_X0Y1_WW4BEG[14]
    DIRECTION OUTPUT ;
    USE SIGNAL ;
    ANTENNADIFFAREA 2.724000 ;
    PORT
      LAYER Metal3 ;
        RECT 0.000 170.740 0.400 171.140 ;
    END
  END Tile_X0Y1_WW4BEG[14]
  PIN Tile_X0Y1_WW4BEG[15]
    DIRECTION OUTPUT ;
    USE SIGNAL ;
    ANTENNADIFFAREA 2.724000 ;
    PORT
      LAYER Metal3 ;
        RECT 0.000 172.420 0.400 172.820 ;
    END
  END Tile_X0Y1_WW4BEG[15]
  PIN Tile_X0Y1_WW4BEG[1]
    DIRECTION OUTPUT ;
    USE SIGNAL ;
    ANTENNADIFFAREA 2.724000 ;
    PORT
      LAYER Metal3 ;
        RECT 0.000 148.900 0.400 149.300 ;
    END
  END Tile_X0Y1_WW4BEG[1]
  PIN Tile_X0Y1_WW4BEG[2]
    DIRECTION OUTPUT ;
    USE SIGNAL ;
    ANTENNADIFFAREA 2.724000 ;
    PORT
      LAYER Metal3 ;
        RECT 0.000 150.580 0.400 150.980 ;
    END
  END Tile_X0Y1_WW4BEG[2]
  PIN Tile_X0Y1_WW4BEG[3]
    DIRECTION OUTPUT ;
    USE SIGNAL ;
    ANTENNADIFFAREA 2.724000 ;
    PORT
      LAYER Metal3 ;
        RECT 0.000 152.260 0.400 152.660 ;
    END
  END Tile_X0Y1_WW4BEG[3]
  PIN Tile_X0Y1_WW4BEG[4]
    DIRECTION OUTPUT ;
    USE SIGNAL ;
    ANTENNADIFFAREA 2.724000 ;
    PORT
      LAYER Metal3 ;
        RECT 0.000 153.940 0.400 154.340 ;
    END
  END Tile_X0Y1_WW4BEG[4]
  PIN Tile_X0Y1_WW4BEG[5]
    DIRECTION OUTPUT ;
    USE SIGNAL ;
    ANTENNADIFFAREA 2.724000 ;
    PORT
      LAYER Metal3 ;
        RECT 0.000 155.620 0.400 156.020 ;
    END
  END Tile_X0Y1_WW4BEG[5]
  PIN Tile_X0Y1_WW4BEG[6]
    DIRECTION OUTPUT ;
    USE SIGNAL ;
    ANTENNADIFFAREA 2.724000 ;
    PORT
      LAYER Metal3 ;
        RECT 0.000 157.300 0.400 157.700 ;
    END
  END Tile_X0Y1_WW4BEG[6]
  PIN Tile_X0Y1_WW4BEG[7]
    DIRECTION OUTPUT ;
    USE SIGNAL ;
    ANTENNADIFFAREA 2.724000 ;
    PORT
      LAYER Metal3 ;
        RECT 0.000 158.980 0.400 159.380 ;
    END
  END Tile_X0Y1_WW4BEG[7]
  PIN Tile_X0Y1_WW4BEG[8]
    DIRECTION OUTPUT ;
    USE SIGNAL ;
    ANTENNADIFFAREA 2.724000 ;
    PORT
      LAYER Metal3 ;
        RECT 0.000 160.660 0.400 161.060 ;
    END
  END Tile_X0Y1_WW4BEG[8]
  PIN Tile_X0Y1_WW4BEG[9]
    DIRECTION OUTPUT ;
    USE SIGNAL ;
    ANTENNADIFFAREA 2.724000 ;
    PORT
      LAYER Metal3 ;
        RECT 0.000 162.340 0.400 162.740 ;
    END
  END Tile_X0Y1_WW4BEG[9]
  PIN VGND
    DIRECTION INOUT ;
    USE GROUND ;
    PORT
      LAYER Metal4 ;
        RECT 15.380 0.000 16.380 544.320 ;
    END
    PORT
      LAYER Metal4 ;
        RECT 65.380 0.000 66.380 544.320 ;
    END
    PORT
      LAYER Metal4 ;
        RECT 115.380 0.000 116.380 544.320 ;
    END
  END VGND
  PIN VPWR
    DIRECTION INOUT ;
    USE POWER ;
    PORT
      LAYER Metal4 ;
        RECT 12.380 0.000 13.380 544.320 ;
    END
    PORT
      LAYER Metal4 ;
        RECT 62.380 0.000 63.380 544.320 ;
    END
    PORT
      LAYER Metal4 ;
        RECT 112.380 0.000 113.380 544.320 ;
    END
  END VPWR
  OBS
      LAYER GatPoly ;
        RECT 2.880 3.630 133.920 540.690 ;
      LAYER Metal1 ;
        RECT 2.880 3.560 133.920 540.760 ;
      LAYER Metal2 ;
        RECT 0.375 543.710 1.990 544.045 ;
        RECT 2.810 543.710 2.950 544.045 ;
        RECT 3.770 543.710 3.910 544.045 ;
        RECT 4.730 543.710 4.870 544.045 ;
        RECT 5.690 543.710 8.710 544.045 ;
        RECT 9.530 543.710 9.670 544.045 ;
        RECT 10.490 543.710 10.630 544.045 ;
        RECT 11.450 543.710 11.590 544.045 ;
        RECT 12.410 543.710 12.550 544.045 ;
        RECT 13.370 543.710 13.510 544.045 ;
        RECT 14.330 543.710 14.470 544.045 ;
        RECT 15.290 543.710 15.430 544.045 ;
        RECT 16.250 543.710 20.230 544.045 ;
        RECT 21.050 543.710 21.190 544.045 ;
        RECT 22.010 543.710 22.150 544.045 ;
        RECT 22.970 543.710 23.110 544.045 ;
        RECT 23.930 543.710 24.070 544.045 ;
        RECT 24.890 543.710 25.030 544.045 ;
        RECT 25.850 543.710 25.990 544.045 ;
        RECT 26.810 543.710 26.950 544.045 ;
        RECT 27.770 543.710 33.670 544.045 ;
        RECT 34.490 543.710 34.630 544.045 ;
        RECT 35.450 543.710 35.590 544.045 ;
        RECT 36.410 543.710 36.550 544.045 ;
        RECT 37.370 543.710 37.510 544.045 ;
        RECT 38.330 543.710 38.470 544.045 ;
        RECT 39.290 543.710 39.430 544.045 ;
        RECT 40.250 543.710 40.390 544.045 ;
        RECT 41.210 543.710 41.350 544.045 ;
        RECT 42.170 543.710 42.310 544.045 ;
        RECT 43.130 543.710 43.270 544.045 ;
        RECT 44.090 543.710 44.230 544.045 ;
        RECT 45.050 543.710 45.190 544.045 ;
        RECT 46.010 543.710 46.150 544.045 ;
        RECT 46.970 543.710 47.110 544.045 ;
        RECT 47.930 543.710 48.070 544.045 ;
        RECT 48.890 543.710 54.790 544.045 ;
        RECT 55.610 543.710 55.750 544.045 ;
        RECT 56.570 543.710 56.710 544.045 ;
        RECT 57.530 543.710 57.670 544.045 ;
        RECT 58.490 543.710 61.510 544.045 ;
        RECT 62.330 543.710 62.470 544.045 ;
        RECT 63.290 543.710 63.430 544.045 ;
        RECT 64.250 543.710 64.390 544.045 ;
        RECT 65.210 543.710 65.350 544.045 ;
        RECT 66.170 543.710 66.310 544.045 ;
        RECT 67.130 543.710 67.270 544.045 ;
        RECT 68.090 543.710 68.230 544.045 ;
        RECT 69.050 543.710 73.030 544.045 ;
        RECT 73.850 543.710 73.990 544.045 ;
        RECT 74.810 543.710 74.950 544.045 ;
        RECT 75.770 543.710 75.910 544.045 ;
        RECT 76.730 543.710 76.870 544.045 ;
        RECT 77.690 543.710 77.830 544.045 ;
        RECT 78.650 543.710 78.790 544.045 ;
        RECT 79.610 543.710 79.750 544.045 ;
        RECT 80.570 543.710 87.430 544.045 ;
        RECT 88.250 543.710 88.390 544.045 ;
        RECT 89.210 543.710 89.350 544.045 ;
        RECT 90.170 543.710 90.310 544.045 ;
        RECT 91.130 543.710 91.270 544.045 ;
        RECT 92.090 543.710 92.230 544.045 ;
        RECT 93.050 543.710 93.190 544.045 ;
        RECT 94.010 543.710 94.150 544.045 ;
        RECT 94.970 543.710 95.110 544.045 ;
        RECT 95.930 543.710 96.070 544.045 ;
        RECT 96.890 543.710 97.030 544.045 ;
        RECT 97.850 543.710 97.990 544.045 ;
        RECT 98.810 543.710 98.950 544.045 ;
        RECT 99.770 543.710 99.910 544.045 ;
        RECT 100.730 543.710 100.870 544.045 ;
        RECT 101.690 543.710 101.830 544.045 ;
        RECT 102.650 543.710 112.390 544.045 ;
        RECT 113.210 543.710 113.350 544.045 ;
        RECT 114.170 543.710 114.310 544.045 ;
        RECT 115.130 543.710 115.270 544.045 ;
        RECT 116.090 543.710 116.230 544.045 ;
        RECT 117.050 543.710 117.190 544.045 ;
        RECT 118.010 543.710 118.150 544.045 ;
        RECT 118.970 543.710 119.110 544.045 ;
        RECT 119.930 543.710 120.070 544.045 ;
        RECT 120.890 543.710 121.030 544.045 ;
        RECT 121.850 543.710 121.990 544.045 ;
        RECT 122.810 543.710 122.950 544.045 ;
        RECT 123.770 543.710 123.910 544.045 ;
        RECT 124.730 543.710 124.870 544.045 ;
        RECT 125.690 543.710 125.830 544.045 ;
        RECT 126.650 543.710 126.790 544.045 ;
        RECT 127.610 543.710 127.750 544.045 ;
        RECT 128.570 543.710 128.710 544.045 ;
        RECT 129.530 543.710 129.670 544.045 ;
        RECT 130.490 543.710 130.630 544.045 ;
        RECT 131.450 543.710 136.425 544.045 ;
        RECT 0.375 0.610 136.425 543.710 ;
        RECT 0.375 0.320 1.990 0.610 ;
        RECT 2.810 0.320 2.950 0.610 ;
        RECT 3.770 0.320 3.910 0.610 ;
        RECT 4.730 0.320 4.870 0.610 ;
        RECT 5.690 0.320 8.710 0.610 ;
        RECT 9.530 0.320 9.670 0.610 ;
        RECT 10.490 0.320 10.630 0.610 ;
        RECT 11.450 0.320 11.590 0.610 ;
        RECT 12.410 0.320 12.550 0.610 ;
        RECT 13.370 0.320 13.510 0.610 ;
        RECT 14.330 0.320 14.470 0.610 ;
        RECT 15.290 0.320 15.430 0.610 ;
        RECT 16.250 0.320 20.230 0.610 ;
        RECT 21.050 0.320 21.190 0.610 ;
        RECT 22.010 0.320 22.150 0.610 ;
        RECT 22.970 0.320 23.110 0.610 ;
        RECT 23.930 0.320 24.070 0.610 ;
        RECT 24.890 0.320 25.030 0.610 ;
        RECT 25.850 0.320 25.990 0.610 ;
        RECT 26.810 0.320 26.950 0.610 ;
        RECT 27.770 0.320 33.670 0.610 ;
        RECT 34.490 0.320 34.630 0.610 ;
        RECT 35.450 0.320 35.590 0.610 ;
        RECT 36.410 0.320 36.550 0.610 ;
        RECT 37.370 0.320 37.510 0.610 ;
        RECT 38.330 0.320 38.470 0.610 ;
        RECT 39.290 0.320 39.430 0.610 ;
        RECT 40.250 0.320 40.390 0.610 ;
        RECT 41.210 0.320 41.350 0.610 ;
        RECT 42.170 0.320 42.310 0.610 ;
        RECT 43.130 0.320 43.270 0.610 ;
        RECT 44.090 0.320 44.230 0.610 ;
        RECT 45.050 0.320 45.190 0.610 ;
        RECT 46.010 0.320 46.150 0.610 ;
        RECT 46.970 0.320 47.110 0.610 ;
        RECT 47.930 0.320 48.070 0.610 ;
        RECT 48.890 0.320 54.790 0.610 ;
        RECT 55.610 0.320 55.750 0.610 ;
        RECT 56.570 0.320 56.710 0.610 ;
        RECT 57.530 0.320 57.670 0.610 ;
        RECT 58.490 0.320 61.510 0.610 ;
        RECT 62.330 0.320 62.470 0.610 ;
        RECT 63.290 0.320 63.430 0.610 ;
        RECT 64.250 0.320 64.390 0.610 ;
        RECT 65.210 0.320 65.350 0.610 ;
        RECT 66.170 0.320 66.310 0.610 ;
        RECT 67.130 0.320 67.270 0.610 ;
        RECT 68.090 0.320 68.230 0.610 ;
        RECT 69.050 0.320 73.030 0.610 ;
        RECT 73.850 0.320 73.990 0.610 ;
        RECT 74.810 0.320 74.950 0.610 ;
        RECT 75.770 0.320 75.910 0.610 ;
        RECT 76.730 0.320 76.870 0.610 ;
        RECT 77.690 0.320 77.830 0.610 ;
        RECT 78.650 0.320 78.790 0.610 ;
        RECT 79.610 0.320 79.750 0.610 ;
        RECT 80.570 0.320 87.430 0.610 ;
        RECT 88.250 0.320 88.390 0.610 ;
        RECT 89.210 0.320 89.350 0.610 ;
        RECT 90.170 0.320 90.310 0.610 ;
        RECT 91.130 0.320 91.270 0.610 ;
        RECT 92.090 0.320 92.230 0.610 ;
        RECT 93.050 0.320 93.190 0.610 ;
        RECT 94.010 0.320 94.150 0.610 ;
        RECT 94.970 0.320 95.110 0.610 ;
        RECT 95.930 0.320 96.070 0.610 ;
        RECT 96.890 0.320 97.030 0.610 ;
        RECT 97.850 0.320 97.990 0.610 ;
        RECT 98.810 0.320 98.950 0.610 ;
        RECT 99.770 0.320 99.910 0.610 ;
        RECT 100.730 0.320 100.870 0.610 ;
        RECT 101.690 0.320 101.830 0.610 ;
        RECT 102.650 0.320 112.390 0.610 ;
        RECT 113.210 0.320 113.350 0.610 ;
        RECT 114.170 0.320 114.310 0.610 ;
        RECT 115.130 0.320 115.270 0.610 ;
        RECT 116.090 0.320 116.230 0.610 ;
        RECT 117.050 0.320 117.190 0.610 ;
        RECT 118.010 0.320 118.150 0.610 ;
        RECT 118.970 0.320 119.110 0.610 ;
        RECT 119.930 0.320 120.070 0.610 ;
        RECT 120.890 0.320 121.030 0.610 ;
        RECT 121.850 0.320 121.990 0.610 ;
        RECT 122.810 0.320 122.950 0.610 ;
        RECT 123.770 0.320 123.910 0.610 ;
        RECT 124.730 0.320 124.870 0.610 ;
        RECT 125.690 0.320 125.830 0.610 ;
        RECT 126.650 0.320 126.790 0.610 ;
        RECT 127.610 0.320 127.750 0.610 ;
        RECT 128.570 0.320 128.710 0.610 ;
        RECT 129.530 0.320 129.670 0.610 ;
        RECT 130.490 0.320 130.630 0.610 ;
        RECT 131.450 0.320 136.425 0.610 ;
      LAYER Metal3 ;
        RECT 0.335 536.750 136.465 544.005 ;
        RECT 0.610 535.930 136.465 536.750 ;
        RECT 0.335 535.070 136.465 535.930 ;
        RECT 0.610 534.250 136.465 535.070 ;
        RECT 0.335 533.390 136.465 534.250 ;
        RECT 0.610 532.570 136.465 533.390 ;
        RECT 0.335 531.710 136.465 532.570 ;
        RECT 0.610 530.890 136.465 531.710 ;
        RECT 0.335 530.030 136.465 530.890 ;
        RECT 0.610 529.210 136.190 530.030 ;
        RECT 0.335 528.350 136.465 529.210 ;
        RECT 0.610 527.530 136.465 528.350 ;
        RECT 0.335 526.670 136.465 527.530 ;
        RECT 0.610 525.850 136.465 526.670 ;
        RECT 0.335 524.990 136.465 525.850 ;
        RECT 0.610 524.170 136.465 524.990 ;
        RECT 0.335 523.310 136.465 524.170 ;
        RECT 0.610 522.490 136.465 523.310 ;
        RECT 0.335 522.470 136.465 522.490 ;
        RECT 0.335 521.650 136.190 522.470 ;
        RECT 0.335 521.630 136.465 521.650 ;
        RECT 0.610 520.810 136.465 521.630 ;
        RECT 0.335 519.950 136.465 520.810 ;
        RECT 0.610 519.130 136.465 519.950 ;
        RECT 0.335 518.270 136.465 519.130 ;
        RECT 0.610 517.450 136.465 518.270 ;
        RECT 0.335 516.590 136.465 517.450 ;
        RECT 0.610 515.770 136.465 516.590 ;
        RECT 0.335 514.910 136.465 515.770 ;
        RECT 0.610 514.090 136.190 514.910 ;
        RECT 0.335 513.230 136.465 514.090 ;
        RECT 0.610 512.410 136.465 513.230 ;
        RECT 0.335 511.550 136.465 512.410 ;
        RECT 0.610 510.730 136.465 511.550 ;
        RECT 0.335 509.870 136.465 510.730 ;
        RECT 0.610 509.050 136.465 509.870 ;
        RECT 0.335 508.190 136.465 509.050 ;
        RECT 0.610 507.370 136.465 508.190 ;
        RECT 0.335 507.350 136.465 507.370 ;
        RECT 0.335 506.530 136.190 507.350 ;
        RECT 0.335 506.510 136.465 506.530 ;
        RECT 0.610 505.690 136.465 506.510 ;
        RECT 0.335 504.830 136.465 505.690 ;
        RECT 0.610 504.010 136.465 504.830 ;
        RECT 0.335 503.150 136.465 504.010 ;
        RECT 0.610 502.330 136.465 503.150 ;
        RECT 0.335 501.470 136.465 502.330 ;
        RECT 0.610 500.650 136.465 501.470 ;
        RECT 0.335 499.790 136.465 500.650 ;
        RECT 0.610 498.970 136.190 499.790 ;
        RECT 0.335 498.110 136.465 498.970 ;
        RECT 0.610 497.290 136.465 498.110 ;
        RECT 0.335 496.430 136.465 497.290 ;
        RECT 0.610 495.610 136.465 496.430 ;
        RECT 0.335 494.750 136.465 495.610 ;
        RECT 0.610 493.930 136.465 494.750 ;
        RECT 0.335 493.070 136.465 493.930 ;
        RECT 0.610 492.250 136.465 493.070 ;
        RECT 0.335 492.230 136.465 492.250 ;
        RECT 0.335 491.410 136.190 492.230 ;
        RECT 0.335 491.390 136.465 491.410 ;
        RECT 0.610 490.570 136.465 491.390 ;
        RECT 0.335 489.710 136.465 490.570 ;
        RECT 0.610 488.890 136.465 489.710 ;
        RECT 0.335 488.030 136.465 488.890 ;
        RECT 0.610 487.210 136.465 488.030 ;
        RECT 0.335 486.350 136.465 487.210 ;
        RECT 0.610 485.530 136.465 486.350 ;
        RECT 0.335 484.670 136.465 485.530 ;
        RECT 0.610 483.850 136.190 484.670 ;
        RECT 0.335 477.110 136.465 483.850 ;
        RECT 0.335 476.290 136.190 477.110 ;
        RECT 0.335 476.270 136.465 476.290 ;
        RECT 0.610 475.450 136.465 476.270 ;
        RECT 0.335 471.230 136.465 475.450 ;
        RECT 0.610 470.410 136.465 471.230 ;
        RECT 0.335 469.550 136.465 470.410 ;
        RECT 0.610 468.730 136.190 469.550 ;
        RECT 0.335 467.870 136.465 468.730 ;
        RECT 0.610 467.050 136.465 467.870 ;
        RECT 0.335 466.190 136.465 467.050 ;
        RECT 0.610 465.370 136.465 466.190 ;
        RECT 0.335 464.510 136.465 465.370 ;
        RECT 0.610 463.690 136.465 464.510 ;
        RECT 0.335 462.830 136.465 463.690 ;
        RECT 0.610 462.010 136.465 462.830 ;
        RECT 0.335 461.990 136.465 462.010 ;
        RECT 0.335 461.170 136.190 461.990 ;
        RECT 0.335 461.150 136.465 461.170 ;
        RECT 0.610 460.330 136.465 461.150 ;
        RECT 0.335 459.470 136.465 460.330 ;
        RECT 0.610 458.650 136.465 459.470 ;
        RECT 0.335 457.790 136.465 458.650 ;
        RECT 0.610 456.970 136.465 457.790 ;
        RECT 0.335 456.110 136.465 456.970 ;
        RECT 0.610 455.290 136.465 456.110 ;
        RECT 0.335 454.430 136.465 455.290 ;
        RECT 0.610 453.610 136.190 454.430 ;
        RECT 0.335 452.750 136.465 453.610 ;
        RECT 0.610 451.930 136.465 452.750 ;
        RECT 0.335 446.870 136.465 451.930 ;
        RECT 0.335 446.050 136.190 446.870 ;
        RECT 0.335 445.190 136.465 446.050 ;
        RECT 0.610 444.370 136.465 445.190 ;
        RECT 0.335 443.510 136.465 444.370 ;
        RECT 0.610 442.690 136.465 443.510 ;
        RECT 0.335 441.830 136.465 442.690 ;
        RECT 0.610 441.010 136.465 441.830 ;
        RECT 0.335 440.150 136.465 441.010 ;
        RECT 0.610 439.330 136.465 440.150 ;
        RECT 0.335 439.310 136.465 439.330 ;
        RECT 0.335 438.490 136.190 439.310 ;
        RECT 0.335 438.470 136.465 438.490 ;
        RECT 0.610 437.650 136.465 438.470 ;
        RECT 0.335 436.790 136.465 437.650 ;
        RECT 0.610 435.970 136.465 436.790 ;
        RECT 0.335 435.110 136.465 435.970 ;
        RECT 0.610 434.290 136.465 435.110 ;
        RECT 0.335 433.430 136.465 434.290 ;
        RECT 0.610 432.610 136.465 433.430 ;
        RECT 0.335 431.750 136.465 432.610 ;
        RECT 0.610 430.930 136.190 431.750 ;
        RECT 0.335 430.070 136.465 430.930 ;
        RECT 0.610 429.250 136.465 430.070 ;
        RECT 0.335 428.390 136.465 429.250 ;
        RECT 0.610 427.570 136.465 428.390 ;
        RECT 0.335 426.710 136.465 427.570 ;
        RECT 0.610 425.890 136.465 426.710 ;
        RECT 0.335 425.030 136.465 425.890 ;
        RECT 0.610 424.210 136.465 425.030 ;
        RECT 0.335 424.190 136.465 424.210 ;
        RECT 0.335 423.370 136.190 424.190 ;
        RECT 0.335 423.350 136.465 423.370 ;
        RECT 0.610 422.530 136.465 423.350 ;
        RECT 0.335 421.670 136.465 422.530 ;
        RECT 0.610 420.850 136.465 421.670 ;
        RECT 0.335 419.990 136.465 420.850 ;
        RECT 0.610 419.170 136.465 419.990 ;
        RECT 0.335 416.630 136.465 419.170 ;
        RECT 0.335 415.810 136.190 416.630 ;
        RECT 0.335 413.270 136.465 415.810 ;
        RECT 0.610 412.450 136.465 413.270 ;
        RECT 0.335 411.590 136.465 412.450 ;
        RECT 0.610 410.770 136.465 411.590 ;
        RECT 0.335 409.910 136.465 410.770 ;
        RECT 0.610 409.090 136.465 409.910 ;
        RECT 0.335 409.070 136.465 409.090 ;
        RECT 0.335 408.250 136.190 409.070 ;
        RECT 0.335 408.230 136.465 408.250 ;
        RECT 0.610 407.410 136.465 408.230 ;
        RECT 0.335 406.550 136.465 407.410 ;
        RECT 0.610 405.730 136.465 406.550 ;
        RECT 0.335 404.870 136.465 405.730 ;
        RECT 0.610 404.050 136.465 404.870 ;
        RECT 0.335 403.190 136.465 404.050 ;
        RECT 0.610 402.370 136.465 403.190 ;
        RECT 0.335 401.510 136.465 402.370 ;
        RECT 0.610 400.690 136.190 401.510 ;
        RECT 0.335 396.470 136.465 400.690 ;
        RECT 0.610 395.650 136.465 396.470 ;
        RECT 0.335 394.790 136.465 395.650 ;
        RECT 0.610 393.970 136.465 394.790 ;
        RECT 0.335 393.950 136.465 393.970 ;
        RECT 0.335 393.130 136.190 393.950 ;
        RECT 0.335 393.110 136.465 393.130 ;
        RECT 0.610 392.290 136.465 393.110 ;
        RECT 0.335 391.430 136.465 392.290 ;
        RECT 0.610 390.610 136.465 391.430 ;
        RECT 0.335 389.750 136.465 390.610 ;
        RECT 0.610 388.930 136.465 389.750 ;
        RECT 0.335 388.070 136.465 388.930 ;
        RECT 0.610 387.250 136.465 388.070 ;
        RECT 0.335 386.390 136.465 387.250 ;
        RECT 0.610 385.570 136.190 386.390 ;
        RECT 0.335 384.710 136.465 385.570 ;
        RECT 0.610 383.890 136.465 384.710 ;
        RECT 0.335 380.510 136.465 383.890 ;
        RECT 0.610 379.690 136.465 380.510 ;
        RECT 0.335 378.830 136.465 379.690 ;
        RECT 0.610 378.010 136.190 378.830 ;
        RECT 0.335 377.150 136.465 378.010 ;
        RECT 0.610 376.330 136.465 377.150 ;
        RECT 0.335 375.470 136.465 376.330 ;
        RECT 0.610 374.650 136.465 375.470 ;
        RECT 0.335 371.270 136.465 374.650 ;
        RECT 0.335 370.450 136.190 371.270 ;
        RECT 0.335 370.430 136.465 370.450 ;
        RECT 0.610 369.610 136.465 370.430 ;
        RECT 0.335 368.750 136.465 369.610 ;
        RECT 0.610 367.930 136.465 368.750 ;
        RECT 0.335 367.070 136.465 367.930 ;
        RECT 0.610 366.250 136.465 367.070 ;
        RECT 0.335 365.390 136.465 366.250 ;
        RECT 0.610 364.570 136.465 365.390 ;
        RECT 0.335 363.710 136.465 364.570 ;
        RECT 0.610 362.890 136.190 363.710 ;
        RECT 0.335 362.030 136.465 362.890 ;
        RECT 0.610 361.210 136.465 362.030 ;
        RECT 0.335 360.350 136.465 361.210 ;
        RECT 0.610 359.530 136.465 360.350 ;
        RECT 0.335 358.670 136.465 359.530 ;
        RECT 0.610 357.850 136.465 358.670 ;
        RECT 0.335 356.990 136.465 357.850 ;
        RECT 0.610 356.170 136.465 356.990 ;
        RECT 0.335 356.150 136.465 356.170 ;
        RECT 0.335 355.330 136.190 356.150 ;
        RECT 0.335 355.310 136.465 355.330 ;
        RECT 0.610 354.490 136.465 355.310 ;
        RECT 0.335 353.630 136.465 354.490 ;
        RECT 0.610 352.810 136.465 353.630 ;
        RECT 0.335 351.950 136.465 352.810 ;
        RECT 0.610 351.130 136.465 351.950 ;
        RECT 0.335 348.590 136.465 351.130 ;
        RECT 0.335 347.770 136.190 348.590 ;
        RECT 0.335 344.390 136.465 347.770 ;
        RECT 0.610 343.570 136.465 344.390 ;
        RECT 0.335 342.710 136.465 343.570 ;
        RECT 0.610 341.890 136.465 342.710 ;
        RECT 0.335 341.030 136.465 341.890 ;
        RECT 0.610 340.210 136.190 341.030 ;
        RECT 0.335 339.350 136.465 340.210 ;
        RECT 0.610 338.530 136.465 339.350 ;
        RECT 0.335 337.670 136.465 338.530 ;
        RECT 0.610 336.850 136.465 337.670 ;
        RECT 0.335 335.990 136.465 336.850 ;
        RECT 0.610 335.170 136.465 335.990 ;
        RECT 0.335 334.310 136.465 335.170 ;
        RECT 0.610 333.490 136.465 334.310 ;
        RECT 0.335 333.470 136.465 333.490 ;
        RECT 0.335 332.650 136.190 333.470 ;
        RECT 0.335 332.630 136.465 332.650 ;
        RECT 0.610 331.810 136.465 332.630 ;
        RECT 0.335 330.950 136.465 331.810 ;
        RECT 0.610 330.130 136.465 330.950 ;
        RECT 0.335 329.270 136.465 330.130 ;
        RECT 0.610 328.450 136.465 329.270 ;
        RECT 0.335 327.590 136.465 328.450 ;
        RECT 0.610 326.770 136.465 327.590 ;
        RECT 0.335 325.910 136.465 326.770 ;
        RECT 0.610 325.090 136.190 325.910 ;
        RECT 0.335 324.230 136.465 325.090 ;
        RECT 0.610 323.410 136.465 324.230 ;
        RECT 0.335 322.550 136.465 323.410 ;
        RECT 0.610 321.730 136.465 322.550 ;
        RECT 0.335 320.870 136.465 321.730 ;
        RECT 0.610 320.050 136.465 320.870 ;
        RECT 0.335 319.190 136.465 320.050 ;
        RECT 0.610 318.370 136.465 319.190 ;
        RECT 0.335 318.350 136.465 318.370 ;
        RECT 0.335 317.530 136.190 318.350 ;
        RECT 0.335 312.470 136.465 317.530 ;
        RECT 0.610 311.650 136.465 312.470 ;
        RECT 0.335 310.790 136.465 311.650 ;
        RECT 0.610 309.970 136.190 310.790 ;
        RECT 0.335 309.110 136.465 309.970 ;
        RECT 0.610 308.290 136.465 309.110 ;
        RECT 0.335 307.430 136.465 308.290 ;
        RECT 0.610 306.610 136.465 307.430 ;
        RECT 0.335 305.750 136.465 306.610 ;
        RECT 0.610 304.930 136.465 305.750 ;
        RECT 0.335 304.070 136.465 304.930 ;
        RECT 0.610 303.250 136.465 304.070 ;
        RECT 0.335 303.230 136.465 303.250 ;
        RECT 0.335 302.410 136.190 303.230 ;
        RECT 0.335 302.390 136.465 302.410 ;
        RECT 0.610 301.570 136.465 302.390 ;
        RECT 0.335 300.710 136.465 301.570 ;
        RECT 0.610 299.890 136.465 300.710 ;
        RECT 0.335 295.670 136.465 299.890 ;
        RECT 0.610 294.850 136.190 295.670 ;
        RECT 0.335 293.990 136.465 294.850 ;
        RECT 0.610 293.170 136.465 293.990 ;
        RECT 0.335 292.310 136.465 293.170 ;
        RECT 0.610 291.490 136.465 292.310 ;
        RECT 0.335 290.630 136.465 291.490 ;
        RECT 0.610 289.810 136.465 290.630 ;
        RECT 0.335 288.950 136.465 289.810 ;
        RECT 0.610 288.130 136.465 288.950 ;
        RECT 0.335 287.270 136.465 288.130 ;
        RECT 0.610 286.450 136.465 287.270 ;
        RECT 0.335 285.590 136.465 286.450 ;
        RECT 0.610 284.770 136.465 285.590 ;
        RECT 0.335 283.910 136.465 284.770 ;
        RECT 0.610 283.090 136.465 283.910 ;
        RECT 0.335 279.710 136.465 283.090 ;
        RECT 0.610 278.890 136.465 279.710 ;
        RECT 0.335 278.030 136.465 278.890 ;
        RECT 0.610 277.210 136.465 278.030 ;
        RECT 0.335 277.190 136.465 277.210 ;
        RECT 0.335 276.370 136.190 277.190 ;
        RECT 0.335 276.350 136.465 276.370 ;
        RECT 0.610 275.530 136.465 276.350 ;
        RECT 0.335 274.670 136.465 275.530 ;
        RECT 0.610 273.850 136.465 274.670 ;
        RECT 0.335 264.590 136.465 273.850 ;
        RECT 0.610 263.770 136.465 264.590 ;
        RECT 0.335 262.910 136.465 263.770 ;
        RECT 0.610 262.090 136.465 262.910 ;
        RECT 0.335 261.230 136.465 262.090 ;
        RECT 0.610 260.410 136.465 261.230 ;
        RECT 0.335 259.550 136.465 260.410 ;
        RECT 0.610 258.730 136.465 259.550 ;
        RECT 0.335 257.870 136.465 258.730 ;
        RECT 0.610 257.050 136.465 257.870 ;
        RECT 0.335 256.190 136.465 257.050 ;
        RECT 0.610 255.370 136.465 256.190 ;
        RECT 0.335 254.510 136.465 255.370 ;
        RECT 0.610 253.690 136.465 254.510 ;
        RECT 0.335 252.830 136.465 253.690 ;
        RECT 0.610 252.010 136.465 252.830 ;
        RECT 0.335 251.150 136.465 252.010 ;
        RECT 0.610 250.330 136.190 251.150 ;
        RECT 0.335 249.470 136.465 250.330 ;
        RECT 0.610 248.650 136.465 249.470 ;
        RECT 0.335 248.630 136.465 248.650 ;
        RECT 0.335 247.810 136.190 248.630 ;
        RECT 0.335 247.790 136.465 247.810 ;
        RECT 0.610 246.970 136.465 247.790 ;
        RECT 0.335 246.110 136.465 246.970 ;
        RECT 0.610 245.290 136.190 246.110 ;
        RECT 0.335 244.430 136.465 245.290 ;
        RECT 0.610 243.610 136.465 244.430 ;
        RECT 0.335 243.590 136.465 243.610 ;
        RECT 0.335 242.770 136.190 243.590 ;
        RECT 0.335 242.750 136.465 242.770 ;
        RECT 0.610 241.930 136.465 242.750 ;
        RECT 0.335 241.070 136.465 241.930 ;
        RECT 0.610 240.250 136.190 241.070 ;
        RECT 0.335 239.390 136.465 240.250 ;
        RECT 0.610 238.570 136.465 239.390 ;
        RECT 0.335 238.550 136.465 238.570 ;
        RECT 0.335 237.730 136.190 238.550 ;
        RECT 0.335 237.710 136.465 237.730 ;
        RECT 0.610 236.890 136.465 237.710 ;
        RECT 0.335 236.030 136.465 236.890 ;
        RECT 0.610 235.210 136.190 236.030 ;
        RECT 0.335 234.350 136.465 235.210 ;
        RECT 0.610 233.530 136.465 234.350 ;
        RECT 0.335 233.510 136.465 233.530 ;
        RECT 0.335 232.690 136.190 233.510 ;
        RECT 0.335 232.670 136.465 232.690 ;
        RECT 0.610 231.850 136.465 232.670 ;
        RECT 0.335 230.990 136.465 231.850 ;
        RECT 0.610 230.170 136.190 230.990 ;
        RECT 0.335 229.310 136.465 230.170 ;
        RECT 0.610 228.490 136.465 229.310 ;
        RECT 0.335 228.470 136.465 228.490 ;
        RECT 0.335 227.650 136.190 228.470 ;
        RECT 0.335 227.630 136.465 227.650 ;
        RECT 0.610 226.810 136.465 227.630 ;
        RECT 0.335 225.950 136.465 226.810 ;
        RECT 0.610 225.130 136.190 225.950 ;
        RECT 0.335 224.270 136.465 225.130 ;
        RECT 0.610 223.450 136.465 224.270 ;
        RECT 0.335 223.430 136.465 223.450 ;
        RECT 0.335 222.610 136.190 223.430 ;
        RECT 0.335 222.590 136.465 222.610 ;
        RECT 0.610 221.770 136.465 222.590 ;
        RECT 0.335 220.910 136.465 221.770 ;
        RECT 0.610 220.090 136.190 220.910 ;
        RECT 0.335 219.230 136.465 220.090 ;
        RECT 0.610 218.410 136.465 219.230 ;
        RECT 0.335 218.390 136.465 218.410 ;
        RECT 0.335 217.570 136.190 218.390 ;
        RECT 0.335 217.550 136.465 217.570 ;
        RECT 0.610 216.730 136.465 217.550 ;
        RECT 0.335 215.870 136.465 216.730 ;
        RECT 0.610 215.050 136.190 215.870 ;
        RECT 0.335 214.190 136.465 215.050 ;
        RECT 0.610 213.370 136.465 214.190 ;
        RECT 0.335 213.350 136.465 213.370 ;
        RECT 0.335 212.530 136.190 213.350 ;
        RECT 0.335 212.510 136.465 212.530 ;
        RECT 0.610 211.690 136.465 212.510 ;
        RECT 0.335 210.830 136.465 211.690 ;
        RECT 0.335 210.010 136.190 210.830 ;
        RECT 0.335 208.310 136.465 210.010 ;
        RECT 0.335 207.490 136.190 208.310 ;
        RECT 0.335 205.790 136.465 207.490 ;
        RECT 0.335 204.970 136.190 205.790 ;
        RECT 0.335 204.110 136.465 204.970 ;
        RECT 0.610 203.290 136.465 204.110 ;
        RECT 0.335 203.270 136.465 203.290 ;
        RECT 0.335 202.450 136.190 203.270 ;
        RECT 0.335 200.750 136.465 202.450 ;
        RECT 0.335 199.930 136.190 200.750 ;
        RECT 0.335 199.070 136.465 199.930 ;
        RECT 0.610 198.250 136.465 199.070 ;
        RECT 0.335 198.230 136.465 198.250 ;
        RECT 0.335 197.410 136.190 198.230 ;
        RECT 0.335 197.390 136.465 197.410 ;
        RECT 0.610 196.570 136.465 197.390 ;
        RECT 0.335 195.710 136.465 196.570 ;
        RECT 0.610 194.890 136.190 195.710 ;
        RECT 0.335 194.030 136.465 194.890 ;
        RECT 0.610 193.210 136.465 194.030 ;
        RECT 0.335 193.190 136.465 193.210 ;
        RECT 0.335 192.370 136.190 193.190 ;
        RECT 0.335 192.350 136.465 192.370 ;
        RECT 0.610 191.530 136.465 192.350 ;
        RECT 0.335 190.670 136.465 191.530 ;
        RECT 0.610 189.850 136.190 190.670 ;
        RECT 0.335 188.990 136.465 189.850 ;
        RECT 0.610 188.170 136.465 188.990 ;
        RECT 0.335 188.150 136.465 188.170 ;
        RECT 0.335 187.330 136.190 188.150 ;
        RECT 0.335 187.310 136.465 187.330 ;
        RECT 0.610 186.490 136.465 187.310 ;
        RECT 0.335 185.630 136.465 186.490 ;
        RECT 0.610 184.810 136.190 185.630 ;
        RECT 0.335 183.950 136.465 184.810 ;
        RECT 0.610 183.130 136.465 183.950 ;
        RECT 0.335 183.110 136.465 183.130 ;
        RECT 0.335 182.290 136.190 183.110 ;
        RECT 0.335 182.270 136.465 182.290 ;
        RECT 0.610 181.450 136.465 182.270 ;
        RECT 0.335 180.590 136.465 181.450 ;
        RECT 0.610 179.770 136.190 180.590 ;
        RECT 0.335 178.070 136.465 179.770 ;
        RECT 0.335 177.250 136.190 178.070 ;
        RECT 0.335 175.550 136.465 177.250 ;
        RECT 0.335 174.730 136.190 175.550 ;
        RECT 0.335 173.030 136.465 174.730 ;
        RECT 0.610 172.210 136.190 173.030 ;
        RECT 0.335 171.350 136.465 172.210 ;
        RECT 0.610 170.530 136.465 171.350 ;
        RECT 0.335 170.510 136.465 170.530 ;
        RECT 0.335 169.690 136.190 170.510 ;
        RECT 0.335 169.670 136.465 169.690 ;
        RECT 0.610 168.850 136.465 169.670 ;
        RECT 0.335 167.990 136.465 168.850 ;
        RECT 0.610 167.170 136.190 167.990 ;
        RECT 0.335 166.310 136.465 167.170 ;
        RECT 0.610 165.490 136.465 166.310 ;
        RECT 0.335 165.470 136.465 165.490 ;
        RECT 0.335 164.650 136.190 165.470 ;
        RECT 0.335 164.630 136.465 164.650 ;
        RECT 0.610 163.810 136.465 164.630 ;
        RECT 0.335 162.950 136.465 163.810 ;
        RECT 0.610 162.130 136.190 162.950 ;
        RECT 0.335 161.270 136.465 162.130 ;
        RECT 0.610 160.450 136.465 161.270 ;
        RECT 0.335 160.430 136.465 160.450 ;
        RECT 0.335 159.610 136.190 160.430 ;
        RECT 0.335 159.590 136.465 159.610 ;
        RECT 0.610 158.770 136.465 159.590 ;
        RECT 0.335 157.910 136.465 158.770 ;
        RECT 0.610 157.090 136.190 157.910 ;
        RECT 0.335 156.230 136.465 157.090 ;
        RECT 0.610 155.410 136.465 156.230 ;
        RECT 0.335 155.390 136.465 155.410 ;
        RECT 0.335 154.570 136.190 155.390 ;
        RECT 0.335 154.550 136.465 154.570 ;
        RECT 0.610 153.730 136.465 154.550 ;
        RECT 0.335 152.870 136.465 153.730 ;
        RECT 0.610 152.050 136.190 152.870 ;
        RECT 0.335 151.190 136.465 152.050 ;
        RECT 0.610 150.370 136.465 151.190 ;
        RECT 0.335 150.350 136.465 150.370 ;
        RECT 0.335 149.530 136.190 150.350 ;
        RECT 0.335 149.510 136.465 149.530 ;
        RECT 0.610 148.690 136.465 149.510 ;
        RECT 0.335 147.830 136.465 148.690 ;
        RECT 0.610 147.010 136.190 147.830 ;
        RECT 0.335 145.310 136.465 147.010 ;
        RECT 0.335 144.490 136.190 145.310 ;
        RECT 0.335 142.790 136.465 144.490 ;
        RECT 0.335 141.970 136.190 142.790 ;
        RECT 0.335 141.110 136.465 141.970 ;
        RECT 0.610 140.290 136.465 141.110 ;
        RECT 0.335 140.270 136.465 140.290 ;
        RECT 0.335 139.450 136.190 140.270 ;
        RECT 0.335 139.430 136.465 139.450 ;
        RECT 0.610 138.610 136.465 139.430 ;
        RECT 0.335 137.750 136.465 138.610 ;
        RECT 0.610 136.930 136.190 137.750 ;
        RECT 0.335 136.070 136.465 136.930 ;
        RECT 0.610 135.250 136.465 136.070 ;
        RECT 0.335 135.230 136.465 135.250 ;
        RECT 0.335 134.410 136.190 135.230 ;
        RECT 0.335 134.390 136.465 134.410 ;
        RECT 0.610 133.570 136.465 134.390 ;
        RECT 0.335 132.710 136.465 133.570 ;
        RECT 0.610 131.890 136.190 132.710 ;
        RECT 0.335 131.030 136.465 131.890 ;
        RECT 0.610 130.210 136.465 131.030 ;
        RECT 0.335 129.350 136.465 130.210 ;
        RECT 0.610 128.530 136.465 129.350 ;
        RECT 0.335 124.310 136.465 128.530 ;
        RECT 0.610 123.490 136.465 124.310 ;
        RECT 0.335 122.630 136.465 123.490 ;
        RECT 0.610 121.810 136.465 122.630 ;
        RECT 0.335 120.950 136.465 121.810 ;
        RECT 0.610 120.130 136.465 120.950 ;
        RECT 0.335 119.270 136.465 120.130 ;
        RECT 0.610 118.450 136.465 119.270 ;
        RECT 0.335 117.590 136.465 118.450 ;
        RECT 0.610 116.770 136.465 117.590 ;
        RECT 0.335 115.910 136.465 116.770 ;
        RECT 0.610 115.090 136.465 115.910 ;
        RECT 0.335 114.230 136.465 115.090 ;
        RECT 0.610 113.410 136.465 114.230 ;
        RECT 0.335 112.550 136.465 113.410 ;
        RECT 0.610 111.730 136.465 112.550 ;
        RECT 0.335 110.030 136.465 111.730 ;
        RECT 0.335 109.210 136.190 110.030 ;
        RECT 0.335 108.350 136.465 109.210 ;
        RECT 0.610 107.530 136.465 108.350 ;
        RECT 0.335 106.670 136.465 107.530 ;
        RECT 0.610 105.850 136.190 106.670 ;
        RECT 0.335 104.990 136.465 105.850 ;
        RECT 0.610 104.170 136.465 104.990 ;
        RECT 0.335 103.310 136.465 104.170 ;
        RECT 0.610 102.490 136.190 103.310 ;
        RECT 0.335 99.950 136.465 102.490 ;
        RECT 0.335 99.130 136.190 99.950 ;
        RECT 0.335 98.270 136.465 99.130 ;
        RECT 0.610 97.450 136.465 98.270 ;
        RECT 0.335 96.590 136.465 97.450 ;
        RECT 0.610 95.770 136.190 96.590 ;
        RECT 0.335 94.910 136.465 95.770 ;
        RECT 0.610 94.090 136.465 94.910 ;
        RECT 0.335 93.230 136.465 94.090 ;
        RECT 0.610 92.410 136.190 93.230 ;
        RECT 0.335 91.550 136.465 92.410 ;
        RECT 0.610 90.730 136.465 91.550 ;
        RECT 0.335 89.870 136.465 90.730 ;
        RECT 0.610 89.050 136.190 89.870 ;
        RECT 0.335 88.190 136.465 89.050 ;
        RECT 0.610 87.370 136.465 88.190 ;
        RECT 0.335 86.510 136.465 87.370 ;
        RECT 0.610 85.690 136.190 86.510 ;
        RECT 0.335 84.830 136.465 85.690 ;
        RECT 0.610 84.010 136.465 84.830 ;
        RECT 0.335 83.150 136.465 84.010 ;
        RECT 0.610 82.330 136.190 83.150 ;
        RECT 0.335 81.470 136.465 82.330 ;
        RECT 0.610 80.650 136.465 81.470 ;
        RECT 0.335 79.790 136.465 80.650 ;
        RECT 0.610 78.970 136.190 79.790 ;
        RECT 0.335 76.430 136.465 78.970 ;
        RECT 0.335 75.610 136.190 76.430 ;
        RECT 0.335 73.070 136.465 75.610 ;
        RECT 0.335 72.250 136.190 73.070 ;
        RECT 0.335 72.230 136.465 72.250 ;
        RECT 0.610 71.410 136.465 72.230 ;
        RECT 0.335 70.550 136.465 71.410 ;
        RECT 0.610 69.730 136.465 70.550 ;
        RECT 0.335 69.710 136.465 69.730 ;
        RECT 0.335 68.890 136.190 69.710 ;
        RECT 0.335 68.870 136.465 68.890 ;
        RECT 0.610 68.050 136.465 68.870 ;
        RECT 0.335 67.190 136.465 68.050 ;
        RECT 0.610 66.370 136.465 67.190 ;
        RECT 0.335 66.350 136.465 66.370 ;
        RECT 0.335 65.530 136.190 66.350 ;
        RECT 0.335 65.510 136.465 65.530 ;
        RECT 0.610 64.690 136.465 65.510 ;
        RECT 0.335 63.830 136.465 64.690 ;
        RECT 0.610 63.010 136.465 63.830 ;
        RECT 0.335 62.990 136.465 63.010 ;
        RECT 0.335 62.170 136.190 62.990 ;
        RECT 0.335 62.150 136.465 62.170 ;
        RECT 0.610 61.330 136.465 62.150 ;
        RECT 0.335 60.470 136.465 61.330 ;
        RECT 0.610 59.650 136.465 60.470 ;
        RECT 0.335 59.630 136.465 59.650 ;
        RECT 0.335 58.810 136.190 59.630 ;
        RECT 0.335 58.790 136.465 58.810 ;
        RECT 0.610 57.970 136.465 58.790 ;
        RECT 0.335 57.110 136.465 57.970 ;
        RECT 0.610 56.290 136.465 57.110 ;
        RECT 0.335 56.270 136.465 56.290 ;
        RECT 0.335 55.450 136.190 56.270 ;
        RECT 0.335 55.430 136.465 55.450 ;
        RECT 0.610 54.610 136.465 55.430 ;
        RECT 0.335 53.750 136.465 54.610 ;
        RECT 0.610 52.930 136.465 53.750 ;
        RECT 0.335 52.910 136.465 52.930 ;
        RECT 0.335 52.090 136.190 52.910 ;
        RECT 0.335 52.070 136.465 52.090 ;
        RECT 0.610 51.250 136.465 52.070 ;
        RECT 0.335 50.390 136.465 51.250 ;
        RECT 0.610 49.570 136.465 50.390 ;
        RECT 0.335 49.550 136.465 49.570 ;
        RECT 0.335 48.730 136.190 49.550 ;
        RECT 0.335 48.710 136.465 48.730 ;
        RECT 0.610 47.890 136.465 48.710 ;
        RECT 0.335 47.030 136.465 47.890 ;
        RECT 0.610 46.210 136.465 47.030 ;
        RECT 0.335 46.190 136.465 46.210 ;
        RECT 0.335 45.370 136.190 46.190 ;
        RECT 0.335 42.830 136.465 45.370 ;
        RECT 0.335 42.010 136.190 42.830 ;
        RECT 0.335 40.310 136.465 42.010 ;
        RECT 0.610 39.490 136.465 40.310 ;
        RECT 0.335 39.470 136.465 39.490 ;
        RECT 0.335 38.650 136.190 39.470 ;
        RECT 0.335 38.630 136.465 38.650 ;
        RECT 0.610 37.810 136.465 38.630 ;
        RECT 0.335 36.950 136.465 37.810 ;
        RECT 0.610 36.130 136.465 36.950 ;
        RECT 0.335 36.110 136.465 36.130 ;
        RECT 0.335 35.290 136.190 36.110 ;
        RECT 0.335 35.270 136.465 35.290 ;
        RECT 0.610 34.450 136.465 35.270 ;
        RECT 0.335 33.590 136.465 34.450 ;
        RECT 0.610 32.770 136.465 33.590 ;
        RECT 0.335 32.750 136.465 32.770 ;
        RECT 0.335 31.930 136.190 32.750 ;
        RECT 0.335 31.910 136.465 31.930 ;
        RECT 0.610 31.090 136.465 31.910 ;
        RECT 0.335 30.230 136.465 31.090 ;
        RECT 0.610 29.410 136.465 30.230 ;
        RECT 0.335 29.390 136.465 29.410 ;
        RECT 0.335 28.570 136.190 29.390 ;
        RECT 0.335 28.550 136.465 28.570 ;
        RECT 0.610 27.730 136.465 28.550 ;
        RECT 0.335 26.030 136.465 27.730 ;
        RECT 0.335 25.210 136.190 26.030 ;
        RECT 0.335 23.510 136.465 25.210 ;
        RECT 0.610 22.690 136.465 23.510 ;
        RECT 0.335 22.670 136.465 22.690 ;
        RECT 0.335 21.850 136.190 22.670 ;
        RECT 0.335 21.830 136.465 21.850 ;
        RECT 0.610 21.010 136.465 21.830 ;
        RECT 0.335 20.150 136.465 21.010 ;
        RECT 0.610 19.330 136.465 20.150 ;
        RECT 0.335 19.310 136.465 19.330 ;
        RECT 0.335 18.490 136.190 19.310 ;
        RECT 0.335 18.470 136.465 18.490 ;
        RECT 0.610 17.650 136.465 18.470 ;
        RECT 0.335 16.790 136.465 17.650 ;
        RECT 0.610 15.970 136.465 16.790 ;
        RECT 0.335 15.950 136.465 15.970 ;
        RECT 0.335 15.130 136.190 15.950 ;
        RECT 0.335 15.110 136.465 15.130 ;
        RECT 0.610 14.290 136.465 15.110 ;
        RECT 0.335 13.430 136.465 14.290 ;
        RECT 0.610 12.610 136.465 13.430 ;
        RECT 0.335 12.590 136.465 12.610 ;
        RECT 0.335 11.770 136.190 12.590 ;
        RECT 0.335 11.750 136.465 11.770 ;
        RECT 0.610 10.930 136.465 11.750 ;
        RECT 0.335 9.230 136.465 10.930 ;
        RECT 0.335 8.410 136.190 9.230 ;
        RECT 0.335 7.550 136.465 8.410 ;
        RECT 0.610 6.730 136.465 7.550 ;
        RECT 0.335 5.870 136.465 6.730 ;
        RECT 0.610 5.050 136.190 5.870 ;
        RECT 0.335 4.190 136.465 5.050 ;
        RECT 0.610 3.370 136.465 4.190 ;
        RECT 0.335 2.510 136.465 3.370 ;
        RECT 0.610 1.690 136.190 2.510 ;
        RECT 0.335 0.315 136.465 1.690 ;
      LAYER Metal4 ;
        RECT 0.380 0.275 12.170 544.045 ;
        RECT 13.590 0.275 15.170 544.045 ;
        RECT 16.590 0.275 62.170 544.045 ;
        RECT 63.590 0.275 65.170 544.045 ;
        RECT 66.590 0.275 112.170 544.045 ;
        RECT 113.590 0.275 115.170 544.045 ;
        RECT 116.590 0.275 135.940 544.045 ;
      LAYER TopMetal1 ;
        RECT 48.620 78.340 108.820 148.380 ;
  END
END NPU_SLICE
END LIBRARY

